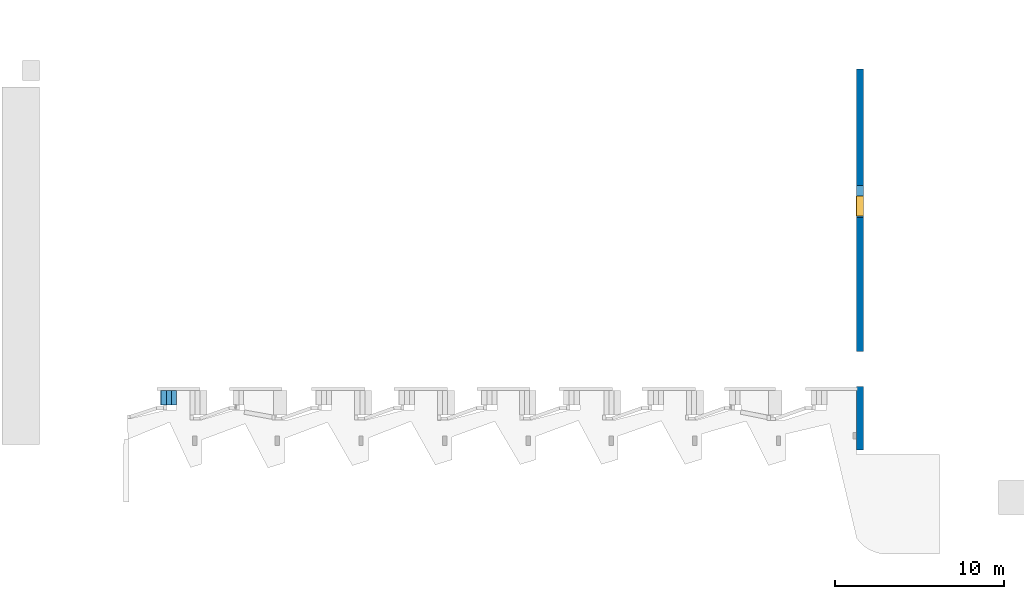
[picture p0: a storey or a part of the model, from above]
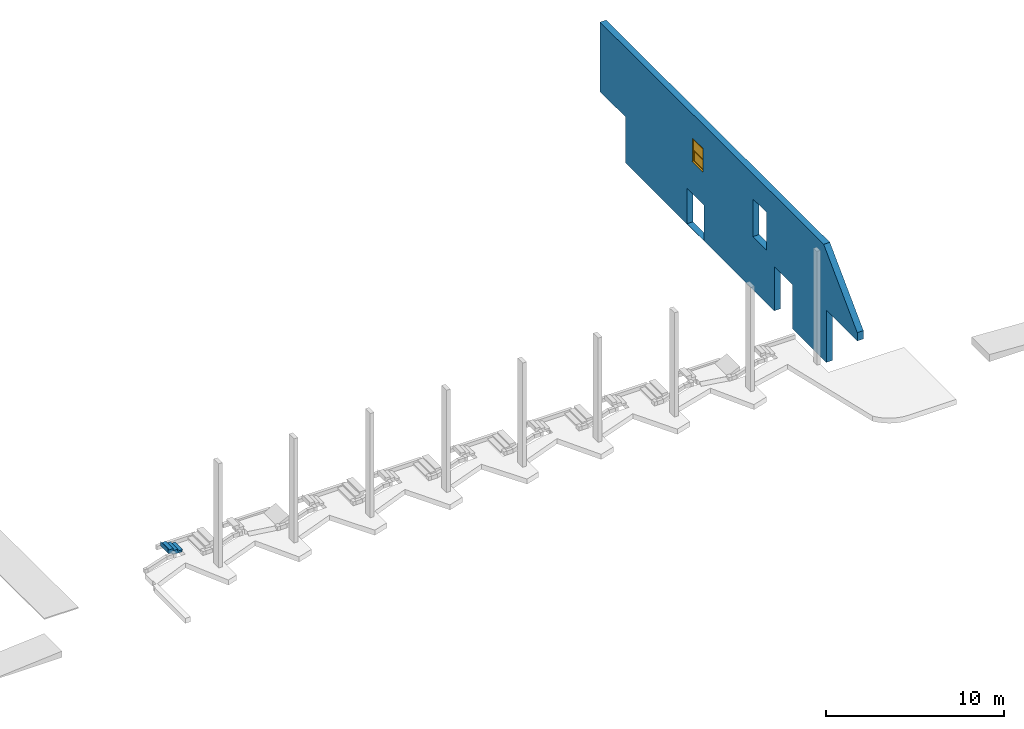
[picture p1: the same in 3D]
Properties of the parts of a building model (IFC4), part 1 of 3

# File
Description: ViewDefinition [ReferenceView_V1.2]
File name: 0001
Time: 2023-06-13T15:23:03-03:00
Written by: ODA SDAI 22.12
Made in: 23.0.11.19 - Exporter 23.0.11.19 - IU alternativa 23.0.11.19

# IfcProject, 0001
LongName: Nombre de proyecto; Phase: Estado de proyecto

# IfcSite, Superficie:305161
RefLatitude: 40, 25, 13, 9643; RefLongitude: -3, -42, -20, -772056; RefElevation: 0 m
Pset_SiteCommon - Reference: Superficie

# IfcBuilding
Pset_BuildingCommon - Reference: Información de proyecto; NumberOfStoreys: 5
Pset_BuildingElementProxyCommon - IsExternal: no; Reference: Información de proyecto
Pset_BuildingStoreyCommon - Reference: Información de proyecto; sets with these values: 2

# IfcBuildingStorey: Nivel:Nivel 1 (4)
Pset_BuildingStoreyCommon - Reference: Nivel 1
Name | LongName | Elevation (m)
Nivel -1 | Nivel -1 | -0.56
Nivel 0 | Nivel 0 | 0
Nivel 1 | Nivel 1 | 3.6
Nivel 2 | Nivel 2 | 7.25

# IfcSpace: Área:508666
In: Nivel 0
LongName: Área; PredefinedType: SPACE; Group: Área construida bruta
Pset_SpaceCommon - Reference: Área; IsExternal: no
Pset_SpaceHeaterTypeCommon - Reference: Área

# IfcSpace: Área:508668
In: Nivel 0
LongName: Área; PredefinedType: SPACE; Group: Área construida bruta
Pset_SpaceCommon - Reference: Área; IsExternal: no
Pset_SpaceHeaterTypeCommon - Reference: Área

# IfcSpace: Área:508670
In: Nivel 0
LongName: Área; PredefinedType: SPACE; Group: Área construida bruta
Pset_SpaceCommon - Reference: Área; IsExternal: no
Pset_SpaceHeaterTypeCommon - Reference: Área

# IfcSpace: Área:508672
In: Nivel 0
LongName: Área; PredefinedType: SPACE; Group: Área construida bruta
Pset_SpaceCommon - Reference: Área; IsExternal: no
Pset_SpaceHeaterTypeCommon - Reference: Área

# IfcSpace: Área:508674
In: Nivel 0
LongName: Área; PredefinedType: SPACE; Group: Área construida bruta
Pset_SpaceCommon - Reference: Área; IsExternal: no
Pset_SpaceHeaterTypeCommon - Reference: Área

# IfcSpace: Área:508676
In: Nivel 0
LongName: Área; PredefinedType: SPACE; Group: Área construida bruta
Pset_SpaceCommon - Reference: Área; IsExternal: no
Pset_SpaceHeaterTypeCommon - Reference: Área

# IfcSpace: Área:508678
In: Nivel 0
LongName: Área; PredefinedType: SPACE; Group: Área construida bruta
Pset_SpaceCommon - Reference: Área; IsExternal: no
Pset_SpaceHeaterTypeCommon - Reference: Área

# IfcSpace: Área:508680
In: Nivel 0
LongName: Área; PredefinedType: SPACE; Group: Área construida bruta
Pset_SpaceCommon - Reference: Área; IsExternal: no
Pset_SpaceHeaterTypeCommon - Reference: Área

# IfcSpace: Área:508682
In: Nivel 0
LongName: Área; PredefinedType: SPACE; Group: Área construida bruta
Pset_SpaceCommon - Reference: Área; IsExternal: no
Pset_SpaceHeaterTypeCommon - Reference: Área

# IfcSpace: Área:508726
In: Nivel 1
LongName: Área; PredefinedType: SPACE; Group: Área construida bruta
Pset_SpaceCommon - Reference: Área; IsExternal: no
Pset_SpaceHeaterTypeCommon - Reference: Área

# IfcSpace: Área:508728
In: Nivel 1
LongName: Área; PredefinedType: SPACE; Group: Área construida bruta
Pset_SpaceCommon - Reference: Área; IsExternal: no
Pset_SpaceHeaterTypeCommon - Reference: Área

# IfcSpace: Área:508730
In: Nivel 1
LongName: Área; PredefinedType: SPACE; Group: Área construida bruta
Pset_SpaceCommon - Reference: Área; IsExternal: no
Pset_SpaceHeaterTypeCommon - Reference: Área

# IfcSpace: Área:508752
In: Nivel -1
LongName: Área; PredefinedType: SPACE; Group: Área construida bruta
Pset_SpaceCommon - Reference: Área; IsExternal: no
Pset_SpaceHeaterTypeCommon - Reference: Área

# IfcSpace: Área:508754
In: Nivel -1
LongName: Área; PredefinedType: SPACE; Group: Área construida bruta
Pset_SpaceCommon - Reference: Área; IsExternal: no
Pset_SpaceHeaterTypeCommon - Reference: Área

# IfcSpace: Área:524344
In: Nivel 0
LongName: Área; PredefinedType: SPACE; Group: De alquiler
Pset_SpaceCommon - Reference: Área; IsExternal: no
Pset_SpaceHeaterTypeCommon - Reference: Área

# IfcSpace: Área:524351
In: Nivel 0
LongName: Área; PredefinedType: SPACE; Group: De alquiler
Pset_SpaceCommon - Reference: Área; IsExternal: no
Pset_SpaceHeaterTypeCommon - Reference: Área

# IfcSpace: Área:524354
In: Nivel 0
LongName: Área; PredefinedType: SPACE; Group: De alquiler
Pset_SpaceCommon - Reference: Área; IsExternal: no
Pset_SpaceHeaterTypeCommon - Reference: Área

# IfcSpace: Área:524357
In: Nivel 0
LongName: Área; PredefinedType: SPACE; Group: De alquiler
Pset_SpaceCommon - Reference: Área; IsExternal: no
Pset_SpaceHeaterTypeCommon - Reference: Área

# IfcSpace: Área:524360
In: Nivel 0
LongName: Área; PredefinedType: SPACE; Group: De alquiler
Pset_SpaceCommon - Reference: Área; IsExternal: no
Pset_SpaceHeaterTypeCommon - Reference: Área

# IfcSpace: Área:524363
In: Nivel 0
LongName: Área; PredefinedType: SPACE; Group: De alquiler
Pset_SpaceCommon - Reference: Área; IsExternal: no
Pset_SpaceHeaterTypeCommon - Reference: Área

# IfcSpace: Área:524366
In: Nivel 0
LongName: Área; PredefinedType: SPACE; Group: De alquiler
Pset_SpaceCommon - Reference: Área; IsExternal: no
Pset_SpaceHeaterTypeCommon - Reference: Área

# IfcSpace: Área:524373
In: Nivel 0
LongName: Área; PredefinedType: SPACE; Group: De alquiler
Pset_SpaceCommon - Reference: Área; IsExternal: no
Pset_SpaceHeaterTypeCommon - Reference: Área

# IfcSpace: Área:524435
In: Nivel 1
LongName: Área; PredefinedType: SPACE; Group: De alquiler
Pset_SpaceCommon - Reference: Área; IsExternal: no
Pset_SpaceHeaterTypeCommon - Reference: Área

# IfcSpace: Área:524438
In: Nivel 1
LongName: Área; PredefinedType: SPACE; Group: De alquiler
Pset_SpaceCommon - Reference: Área; IsExternal: no
Pset_SpaceHeaterTypeCommon - Reference: Área

# IfcSpace: Área:524441
In: Nivel 1
LongName: Área; PredefinedType: SPACE; Group: De alquiler
Pset_SpaceCommon - Reference: Área; IsExternal: no
Pset_SpaceHeaterTypeCommon - Reference: Área

# IfcSpace: Área:525715
In: Nivel 1
LongName: Área; PredefinedType: SPACE; Group: De alquiler
Pset_SpaceCommon - Reference: Área; IsExternal: no
Pset_SpaceHeaterTypeCommon - Reference: Área

# IfcSpace: Área:529661
In: Nivel 0
LongName: Área; PredefinedType: SPACE; Group: De alquiler
Pset_SpaceCommon - Reference: Área; IsExternal: no
Pset_SpaceHeaterTypeCommon - Reference: Área

# IfcBeam: Calibre delgado-Ángulos:L140 x 40 (64)
In: Nivel 1
Type - PredefinedType: BEAM; Classification: B10 Superstructure (Uniformat); Material: Metal - Calibre delgado
Type - Pset_BeamCommon - IsExternal: no; LoadBearing: yes
Pset_BeamCommon - Slope: 0 deg; Roll: 0 deg; Reference: L140 x 40
Pset_EnvironmentalImpactIndicators - Reference: L140 x 40; sets with these values: 2
Name (Calibre delgado-Ángulos:L140 x 40:...) | Span (m)
473266 | 5.8
473267 | 5.8
475000 | 5.8
475001 | 5.8
475056 | 5.8
475057 | 5.8
475089 | 5.8
475090 | 5.8
475131 | 5.8
475132 | 5.8
475164 | 5.8
475165 | 5.8
475208 | 5.8
475209 | 5.8
475241 | 5.8
475242 | 5.8
475287 | 5.8
475288 | 5.8
475320 | 5.8
475321 | 5.8
475362 | 5.8
475363 | 5.8
475395 | 5.8
475396 | 5.8
475441 | 5.8
475442 | 5.8
475474 | 5.8
475475 | 5.8
475514 | 5.8
475515 | 5.8
475547 | 5.8
475548 | 5.8
476010 | 3.745
476011 | 3.745
476043 | 3.245
476044 | 3.245
484346 | 3.745
484347 | 3.745
484379 | 3.245
484380 | 3.245
484423 | 3.745
484424 | 3.745
484456 | 3.245
484457 | 3.245
484496 | 3.745
484497 | 3.745
484529 | 3.245
484530 | 3.245
484571 | 3.745
484572 | 3.745
484604 | 3.245
484605 | 3.245
484646 | 3.745
484647 | 3.745
484679 | 3.245
484680 | 3.245
484721 | 3.745
484722 | 3.745
484754 | 3.245
484755 | 3.245
484798 | 3.745
484799 | 3.745
484831 | 3.245
484832 | 3.245

# IfcBeam: Familia4:Familia4, Familia4:Familia4:477913
In: Nivel 2
Type - PredefinedType: BEAM; Material: <Unnamed>
Type - Pset_BeamCommon - IsExternal: no; LoadBearing: yes
Pset_BeamCommon - Slope: 0 deg; Roll: 0 deg; Reference: Familia4; Span: 34.29 m
Pset_EnvironmentalImpactIndicators - Reference: Familia4; sets with these values: 2

# IfcBeam: Glulam-Pino del sur:127X279 (14)
In: Nivel 2
Type - PredefinedType: BEAM; Material: Madera - Madera de construcción
Type - Pset_BeamCommon - IsExternal: no; LoadBearing: yes
Pset_BeamCommon - Slope: 0 deg; Roll: 0 deg; Reference: 127X279; Span: 31.09 m
Pset_EnvironmentalImpactIndicators - Reference: 127X279; sets with these values: 2
Name (Glulam-Pino del sur:127X279:...)
500644
500646
500648
500650
500652
500654
500905
502043
502045
502047
502049
502051
502053
502055

# IfcBeam: Glulam-Pino del sur:76X140 (20)
Type - PredefinedType: BEAM; Material: Madera - Madera de construcción
Type - Pset_BeamCommon - IsExternal: no; LoadBearing: yes
Pset_BeamCommon - Roll: 0 deg; Reference: 76X140
Pset_EnvironmentalImpactIndicators - Reference: 76X140; sets with these values: 2
Name (Glulam-Pino del sur:76X140:...) | In | Span (m) | Slope (deg)
502747 | Nivel 1 | 2.012 | 29.5898
502748 | Nivel 1 | 2.018 | 29.8998
503400 | Nivel 1 | 2.012 | 29.5898
503401 | Nivel 1 | 2.018 | 29.8998
503442 | Nivel 1 | 2.012 | 29.5898
503443 | Nivel 1 | 2.018 | 29.8998
503513 | Nivel 1 | 2.012 | 29.5898
503514 | Nivel 1 | 2.018 | 29.8998
503559 | Nivel 1 | 2.012 | 29.5898
503560 | Nivel 1 | 2.018 | 29.8998
503611 | Nivel 1 | 2.012 | 29.5898
503612 | Nivel 1 | 2.018 | 29.8998
503664 | Nivel 1 | 2.012 | 29.5898
503665 | Nivel 1 | 2.018 | 29.8998
503721 | Nivel 1 | 2.012 | 29.5898
503722 | Nivel 1 | 2.018 | 29.8998
505065 | Nivel 0 | 34.1 | 0
505956 | Nivel 1 | 18 | 0
506497 | Nivel 1 | 4.8 | 0
506699 | Nivel 1 | 4.8 | 0

# IfcBeam: Hormigón-Viga rectangular:500 x 550mm 2 (3)
In: Nivel 1
Type - PredefinedType: BEAM; Material: <Unnamed>
Type - Pset_BeamCommon - IsExternal: no; LoadBearing: yes
Pset_BeamCommon - Slope: 0 deg; Roll: 0 deg; Reference: 500 x 550mm 2
Pset_EnvironmentalImpactIndicators - Reference: 500 x 550mm 2; sets with these values: 2
Name (Hormigón-Viga rectangular:500 x 550mm 2:...) | Span (m)
478072 | 43.197
478593 | 4.33
478989 | 4

# IfcBeam: MT-T estructural:MT65X14.05 (40)
In: Nivel 2
Type - PredefinedType: BEAM; Material: Metal - Acero - 345 MPa
Type - Pset_BeamCommon - IsExternal: no; LoadBearing: yes
Pset_BeamCommon - Roll: 0 deg; Reference: MT65X14.05
Pset_EnvironmentalImpactIndicators - Reference: MT65X14.05; sets with these values: 2
Name (MT-T estructural:MT65X14.05:...) | Slope (deg) | Span (m)
482733 | 0 | 7.735
482734 | 0 | 7.735
482735 | 28.4535 | 8.797
482736 | 28.4535 | 8.797
483913 | 1.20936 | 9.804
483914 | 24.2173 | 10.747
483987 | 0.636424 | 9.786
483988 | 23.772 | 10.693
484069 | 1.21062 | 9.793
484070 | 24.2396 | 10.738
484078 | 0.641706 | 9.706
484079 | 23.9472 | 10.619
499890 | 0 | 7.735
499891 | 0 | 7.735
499892 | 28.4535 | 8.797
499893 | 28.4535 | 8.797
499908 | 0 | 7.735
499909 | 0 | 7.735
499910 | 28.4535 | 8.797
499911 | 28.4535 | 8.797
588031 | 0 | 7.735
588032 | 0 | 7.735
588033 | 28.4535 | 8.797
588034 | 28.4535 | 8.797
588049 | 0 | 7.735
588050 | 0 | 7.735
588051 | 28.4535 | 8.797
588052 | 28.4535 | 8.797
588069 | 0 | 7.735
588070 | 0 | 7.735
588071 | 28.4535 | 8.797
588072 | 28.4535 | 8.797
588089 | 0 | 7.735
588090 | 0 | 7.735
588091 | 28.4535 | 8.797
588092 | 28.4535 | 8.797
588111 | 0 | 7.735
588112 | 0 | 7.735
588113 | 28.4535 | 8.797
588114 | 28.4535 | 8.797

# IfcBeam: UB-Perfil universal:203x133x25UB (2)
In: Nivel 0
Type - PredefinedType: BEAM; Material: Metal - Acero - 345 MPa
Type - Pset_BeamCommon - IsExternal: no; LoadBearing: yes
Pset_BeamCommon - Slope: 0 deg; Reference: 203x133x25UB; Span: 11.76 m; Roll: 0 deg
Pset_EnvironmentalImpactIndicators - Reference: 203x133x25UB; sets with these values: 2
Name (UB-Perfil universal:203x133x25UB:...)
254423
257939

# IfcBeam: UB-Perfil universal:305x165x40UB (9)
Type - PredefinedType: BEAM; Material: Metal - Acero - 345 MPa
Type - Pset_BeamCommon - IsExternal: no; LoadBearing: yes
Pset_BeamCommon - Roll: 0 deg; Reference: 305x165x40UB
Pset_EnvironmentalImpactIndicators - Reference: 305x165x40UB; sets with these values: 2
Name (UB-Perfil universal:305x165x40UB:...) | In | Slope (deg) | Span (m)
258424 | Nivel 0 | 0 | 11.71
484929 | Nivel 1 | 42.7094 | 4.422
485413 | Nivel 1 | 42.7094 | 4.422
485424 | Nivel 1 | 42.7094 | 4.422
485439 | Nivel 1 | 42.7094 | 4.422
485452 | Nivel 1 | 42.7094 | 4.422
485461 | Nivel 1 | 42.7094 | 4.422
485474 | Nivel 1 | 42.7094 | 4.422
485487 | Nivel 1 | 42.7094 | 4.422

# IfcColumn: Pilar rectangular hormigón:100 x 180 mm 2 (9)
In: Nivel 0
Type - PredefinedType: COLUMN; Material: <Unnamed>
Type - Pset_ColumnCommon - IsExternal: no; LoadBearing: yes
Pset_ColumnCommon - Reference: 100 x 180 mm 2
Pset_EnvironmentalImpactIndicators - Reference: 100 x 180 mm 2; sets with these values: 2
Name (Pilar rectangular hormigón:100 x 180 mm 2:...)
185699
185760
307513
307828
307911
307978
307991
310705 | Pset_ColumnCommon - Slope: 0 deg
313675

# IfcColumn: Pilar rectangular hormigón:100 x 200 mm 3, Pilar rectangular hormigón:100 x 200 mm 3:292656
In: Nivel 0
Type - PredefinedType: COLUMN; Material: <Unnamed>
Type - Pset_ColumnCommon - IsExternal: no; LoadBearing: yes
Pset_ColumnCommon - Reference: 100 x 200 mm 3
Pset_EnvironmentalImpactIndicators - Reference: 100 x 200 mm 3; sets with these values: 2

# IfcColumn: Pilar rectangular hormigón:110 x 110 mm 3 (10)
In: Nivel 1
Type - PredefinedType: COLUMN; Material: <Unnamed>
Type - Pset_ColumnCommon - IsExternal: no; LoadBearing: yes
Pset_ColumnCommon - Reference: 110 x 110 mm 3
Pset_EnvironmentalImpactIndicators - Reference: 110 x 110 mm 3; sets with these values: 2
Name (Pilar rectangular hormigón:110 x 110 mm 3:...)
356811
357788
362148
362694
366528
366587
405644
405647
405773
405776

# IfcColumn: Pilar rectangular hormigón:120 x 160 mm 4 (8)
In: Nivel 0
Type - PredefinedType: COLUMN; Material: <Unnamed>
Type - Pset_ColumnCommon - IsExternal: no; LoadBearing: yes
Pset_ColumnCommon - Reference: 120 x 160 mm 4
Pset_EnvironmentalImpactIndicators - Reference: 120 x 160 mm 4; sets with these values: 2
Name (Pilar rectangular hormigón:120 x 160 mm 4:...)
185893
185971
186019
186042
186062
186096
219436
219437

# IfcColumn: Pilar rectangular hormigón:120 x 180 mm 3 (6)
In: Nivel 0
Type - PredefinedType: COLUMN; Material: <Unnamed>
Type - Pset_ColumnCommon - IsExternal: no; LoadBearing: yes
Pset_ColumnCommon - Reference: 120 x 180 mm 3
Pset_EnvironmentalImpactIndicators - Reference: 120 x 180 mm 3; sets with these values: 2
Name (Pilar rectangular hormigón:120 x 180 mm 3:...)
185724
185850
267552
267672
267702
279104

# IfcColumn: Pilar rectangular hormigón:160 x 250 mm 4 (2)
In: Nivel 0
Type - PredefinedType: COLUMN; Material: <Unnamed>
Type - Pset_ColumnCommon - IsExternal: no; LoadBearing: yes
Pset_ColumnCommon - Reference: 160 x 250 mm 4
Pset_EnvironmentalImpactIndicators - Reference: 160 x 250 mm 4; sets with these values: 2
Name (Pilar rectangular hormigón:160 x 250 mm 4:...)
214045
214521

# IfcColumn: Pilar rectangular hormigón:180 x 180 mm 3 (5)
In: Nivel 0
Type - PredefinedType: COLUMN; Material: <Unnamed>
Type - Pset_ColumnCommon - IsExternal: no; LoadBearing: yes
Pset_ColumnCommon - Reference: 180 x 180 mm 3
Pset_EnvironmentalImpactIndicators - Reference: 180 x 180 mm 3; sets with these values: 2
Name (Pilar rectangular hormigón:180 x 180 mm 3:...)
186938
187138
226451
267727
327475

# IfcColumn: Pilar rectangular hormigón:200 x 370 mm 3 (2)
Type - PredefinedType: COLUMN; Material: <Unnamed>
Type - Pset_ColumnCommon - IsExternal: no; LoadBearing: yes
Pset_ColumnCommon - Reference: 200 x 370 mm 3
Pset_EnvironmentalImpactIndicators - Reference: 200 x 370 mm 3; sets with these values: 2
Name (Pilar rectangular hormigón:200 x 370 mm 3:...) | In
184023 | Nivel 0
184345 | Nivel -1

# IfcColumn: Pilar rectangular hormigón:250 x 500 mm 4, Pilar rectangular hormigón:250 x 500 mm 4:272511
In: Nivel 0
Type - PredefinedType: COLUMN; Material: <Unnamed>
Type - Pset_ColumnCommon - IsExternal: no; LoadBearing: yes
Pset_ColumnCommon - Reference: 250 x 500 mm 4
Pset_EnvironmentalImpactIndicators - Reference: 250 x 500 mm 4; sets with these values: 2

# IfcColumn: Pilar rectangular hormigón:250 x 560 mm 2 (16)
Type - PredefinedType: COLUMN; Material: <Unnamed>
Type - Pset_ColumnCommon - IsExternal: no; LoadBearing: yes
Pset_ColumnCommon - Reference: 250 x 560 mm 2
Pset_EnvironmentalImpactIndicators - Reference: 250 x 560 mm 2; sets with these values: 2
Name (Pilar rectangular hormigón:250 x 560 mm 2:...) | In
181776 | Nivel -1
181876 | Nivel -1
182387 | Nivel -1
182528 | Nivel -1
182604 | Nivel -1
182714 | Nivel -1
182718 | Nivel -1
182881 | Nivel -1
182939 | Nivel 0
183344 | Nivel 0
183365 | Nivel 0
183386 | Nivel 0
183398 | Nivel 0
183424 | Nivel 0
183438 | Nivel 0
183450 | Nivel 0

# IfcColumn: Pilar rectangular hormigón:280 x 280 mm 2 (4)
In: Nivel 0
Type - PredefinedType: COLUMN; Material: <Unnamed>
Type - Pset_ColumnCommon - IsExternal: no; LoadBearing: yes
Pset_ColumnCommon - Reference: 280 x 280 mm 2
Pset_EnvironmentalImpactIndicators - Reference: 280 x 280 mm 2; sets with these values: 2
Name (Pilar rectangular hormigón:280 x 280 mm 2:...)
185399
185660
185670
225717 | Pset_ColumnCommon - Slope: 0 deg

# IfcColumn: Pilar rectangular hormigón:300 x 300 mm (6)
In: Nivel 0
Type - PredefinedType: COLUMN; Material: <Unnamed>
Type - Pset_ColumnCommon - IsExternal: no; LoadBearing: yes
Pset_ColumnCommon - Reference: 300 x 300 mm
Pset_EnvironmentalImpactIndicators - Reference: 300 x 300 mm; sets with these values: 2
Name (Pilar rectangular hormigón:300 x 300 mm:...)
185258
185382
275395
275464
275476
275490

# IfcColumn: Pilar rectangular hormigón:310 x 560 mm 2 (10)
In: Nivel 0
Type - PredefinedType: COLUMN; Material: <Unnamed>
Type - Pset_ColumnCommon - IsExternal: no; LoadBearing: yes
Pset_ColumnCommon - Reference: 310 x 560 mm 2
Pset_EnvironmentalImpactIndicators - Reference: 310 x 560 mm 2; sets with these values: 2
Name (Pilar rectangular hormigón:310 x 560 mm 2:...)
428051
428371
428669
428751
428786
428787
428956
428984
429018
429059

# IfcColumn: Pilar rectangular hormigón:600 x 700 mm 5, Pilar rectangular hormigón:600 x 700 mm 5:427090
In: Nivel 0
Type - PredefinedType: COLUMN; Material: <Unnamed>
Type - Pset_ColumnCommon - IsExternal: no; LoadBearing: yes
Pset_ColumnCommon - Reference: 600 x 700 mm 5
Pset_EnvironmentalImpactIndicators - Reference: 600 x 700 mm 5; sets with these values: 2

# IfcColumn: Pilar rectangular hormigón:630 x 740 mm 4, Pilar rectangular hormigón:630 x 740 mm 4:314824
In: Nivel 0
Type - PredefinedType: COLUMN; Material: <Unnamed>
Type - Pset_ColumnCommon - IsExternal: no; LoadBearing: yes
Pset_ColumnCommon - Reference: 630 x 740 mm 4
Pset_EnvironmentalImpactIndicators - Reference: 630 x 740 mm 4; sets with these values: 2

# IfcCovering: Techo compuesto:Falso techo 2 de placa de yeso laminado (6)
Type - PredefinedType: CEILING
Type - Pset_CoveringCommon - IsExternal: no
Material: Lámina de enlucido perforada
Pset_CoveringCommon - Reference: Falso techo 2 de placa de yeso laminado; Finish: Lámina de enlucido perforada;
Pset_EnvironmentalImpactIndicators - Reference: Falso techo 2 de placa de yeso laminado
Name (Techo compuesto:Falso techo 2 de placa de yeso laminado:...) | In
222428 | Nivel 1
224767 | Nivel 0
253870 | Nivel 0
409967 | Nivel 1
509764 | Nivel 0
564613 | Nivel 1

# IfcCurtainWall: Muro básico:Por defecto - 10 cm (90)
Type - Pset_CurtainWallCommon - IsExternal: yes
Material: <Unnamed>
Pset_CurtainWallCommon - Reference: Por defecto - 10 cm
Pset_EnvironmentalImpactIndicators - Reference: Por defecto - 10 cm
Name (Muro básico:Por defecto - 10 cm:...) | In
250650 | Nivel 0
250606 | Nivel 0
250574 | Nivel 0
253623 | Nivel 0
252925 | Nivel 0
269627 | Nivel 0
269625 | Nivel 0
270698 | Nivel 0
272088 | Nivel 0
271545 | Nivel 0
271903 | Nivel 0
271904 | Nivel 0
273407 | Nivel 0
274762 | Nivel 0
275557 | Nivel 0
275646 | Nivel 0
275693 | Nivel 0
279073 | Nivel 0
276852 | Nivel 0
277248 | Nivel 0
277247 | Nivel 0
289521 | Nivel 0
289540 | Nivel 0
289566 | Nivel 0
289577 | Nivel 0
289587 | Nivel 0
289594 | Nivel 0
289596 | Nivel 0
519957 | Nivel 0
519993 | Nivel 0
510679 | Nivel 0
308412 | Nivel 0
432963 | Nivel 0
432965 | Nivel 0
515756 | Nivel 0
310866 | Nivel 0
326347 | Nivel 0
326358 | Nivel 0
326326 | Nivel 0
326357 | Nivel 0
329254 | Nivel 0
329256 | Nivel 0
329252 | Nivel 0
329257 | Nivel 0
357591 | Nivel 1
358342 | Nivel 1
361881 | Nivel 1
359012 | Nivel 1
362881 | Nivel 1
362736 | Nivel 1
362778 | Nivel 1
366689 | Nivel 1
366627 | Nivel 1
367036 | Nivel 1
366669 | Nivel 1
386155 | Nivel 0
386154 | Nivel 0
389050 | Nivel 0
389048 | Nivel 0
389031 | Nivel 0
389051 | Nivel 0
389053 | Nivel 0
389237 | Nivel 0
389172 | Nivel 0
389198 | Nivel 0
389215 | Nivel 0
405749 | Nivel 1
405687 | Nivel 1
632068 | Nivel 1
405729 | Nivel 1
405816 | Nivel 1
535234 | Nivel 1
405883 | Nivel 1
405858 | Nivel 1
512644 | Nivel 0
512694 | Nivel 0
512769 | Nivel 0
513380 | Nivel 0
513801 | Nivel 0
513947 | Nivel 0
514220 | Nivel 0
516324 | Nivel 0
518640 | Nivel 0
518642 | Nivel 0
516101 | Nivel 0
519531 | Nivel 0
519533 | Nivel 0
532224 | Nivel 0
532621 | Nivel 0
532585 | Nivel 0

# IfcCurtainWall: Muro básico:Por defecto - 12 cm 2 (15)
In: Nivel 0
Type - Pset_CurtainWallCommon - IsExternal: yes
Material: <Unnamed>
Pset_CurtainWallCommon - Reference: Por defecto - 12 cm 2
Pset_EnvironmentalImpactIndicators - Reference: Por defecto - 12 cm 2
Name (Muro básico:Por defecto - 12 cm 2:...)
222609
222542
211875
212557
212708
215758
215760
215864
215865
216034
216035
219531
219886
220863
220864

# IfcCurtainWall: Muro básico:Por defecto - 5 cm 2 (2)
In: Nivel 0
Type - Pset_CurtainWallCommon - IsExternal: yes
Material: <Unnamed>
Pset_CurtainWallCommon - Reference: Por defecto - 5 cm 2
Pset_EnvironmentalImpactIndicators - Reference: Por defecto - 5 cm 2
Name (Muro básico:Por defecto - 5 cm 2:...)
396029
433225

# IfcCurtainWall: Muro cortina:Muro cortina - simple (69)
Type - Pset_CurtainWallCommon - IsExternal: yes
Pset_CurtainWallCommon - Reference: Muro cortina - simple
Pset_EnvironmentalImpactIndicators - Reference: Muro cortina - simple
Name (Muro cortina:Muro cortina - simple:...) | In
206558 | Nivel 0
211066 | Nivel 0
212552 | Nivel 0
212704 | Nivel 0
214658 | Nivel 0
215856 | Nivel 0
216026 | Nivel 0
219526 | Nivel 0
219882 | Nivel 0
220350 | Nivel 0
233194 | Nivel 0
240171 | Nivel 0
249432 | Nivel 0
251173 | Nivel 0
252332 | Nivel 0
268531 | Nivel 0
270169 | Nivel 0
271016 | Nivel 0
271862 | Nivel 0
273371 | Nivel 0
274169 | Nivel 0
275532 | Nivel 0
275621 | Nivel 0
275668 | Nivel 0
275809 | Nivel 0
277203 | Nivel 0
278219 | Nivel 0
280223 | Nivel 0
280855 | Nivel 0
288782 | Nivel 0
289975 | Nivel 0
293080 | Nivel 0
308048 | Nivel 0
308113 | Nivel 0
310834 | Nivel 0
325444 | Nivel 0
328564 | Nivel 0
352709 | Nivel 1
355699 | Nivel 1
357075 | Nivel 1
357720 | Nivel 1
358403 | Nivel 1
362692 | Nivel 1
362737 | Nivel 1
363124 | Nivel 1
366585 | Nivel 1
366628 | Nivel 1
385507 | Nivel 0
387263 | Nivel 0
387446 | Nivel 0
387636 | Nivel 0
387770 | Nivel 0
390942 | Nivel 0
404725 | Nivel 1
405645 | Nivel 1
405688 | Nivel 1
405750 | Nivel 1
405774 | Nivel 1
405817 | Nivel 1
405885 | Nivel 1
408320 | Nivel 1
408454 | Nivel 1
409654 | Nivel 1
511763 | Nivel 0
516071 | Nivel 0
530913 | Nivel 0
531747 | Nivel 0
589380 | Nivel 1
589845 | Nivel 1

# IfcDoor: Puerta atamborada de 2 hojas:1200 x 2100 mm 2 (4)
In: Nivel 1
Type - PredefinedType: DOOR; Material: Puerta - Panel, Puerta - Marco
Type - Pset_DoorCommon - IsExternal: no; ThermalTransmittance: 3.7021 kg/K/s3
OverallHeight: 2.1 m; OverallWidth: 1.2 m
Pset_DoorCommon - Reference: 1200 x 2100 mm 2
Pset_EnvironmentalImpactIndicators - Reference: 1200 x 2100 mm 2
Name (Puerta atamborada de 2 hojas:1200 x 2100 mm 2:...)
419465
419806
419989
632473

# IfcDoor: Puerta corredera simple con guía deslizante:1330 x 2100mm 2, Puerta corredera simple con guía deslizante:1330 x 2100mm 2:195537
In: Nivel 0
Type - PredefinedType: DOOR; Material: <Unnamed>, Madera - Castaño (3)
Type - Pset_DoorCommon - IsExternal: no; ThermalTransmittance: 3.7021 kg/K/s3
OverallHeight: 2.1 m; OverallWidth: 1.33 m; Material: <Unnamed>, Madera - Castaño
Pset_DoorCommon - Reference: 1330 x 2100mm 2
Pset_EnvironmentalImpactIndicators - Reference: 1330 x 2100mm 2

# IfcDoor: Puerta de 1 hoja:116 x 210 cm 2, Puerta de 1 hoja:116 x 210 cm 2:424842
In: Nivel 1
Type - PredefinedType: DOOR; Material: Madera - Castaño
Type - Pset_DoorCommon - IsExternal: no
OverallHeight: 2.1 m; OverallWidth: 1.16 m
Pset_DoorCommon - IsExternal: yes; Reference: 116 x 210 cm 2
Pset_EnvironmentalImpactIndicators - Reference: 116 x 210 cm 2

# IfcDoor: Puerta de 1 hoja:120 x 210 cm 3 (2)
In: Nivel 1
Type - PredefinedType: DOOR; Material: Madera - Castaño
Type - Pset_DoorCommon - IsExternal: no
OverallHeight: 2.1 m; OverallWidth: 1.2 m
Pset_DoorCommon - Reference: 120 x 210 cm 3
Pset_EnvironmentalImpactIndicators - Reference: 120 x 210 cm 3
Name (Puerta de 1 hoja:120 x 210 cm 3:...)
485995 | Pset_DoorCommon - IsExternal: yes
632139

# IfcDoor: Puerta de 1 hoja:70 x 210 cm (2)
In: Nivel 1
Type - PredefinedType: DOOR; Material: Madera - Castaño
Type - Pset_DoorCommon - IsExternal: no; ThermalTransmittance: 3.7021 kg/K/s3
OverallHeight: 2.1 m; OverallWidth: 0.7 m
Pset_DoorCommon - Reference: 70 x 210 cm
Pset_EnvironmentalImpactIndicators - Reference: 70 x 210 cm
Name (Puerta de 1 hoja:70 x 210 cm:...)
487238
487425

# IfcDoor: Puerta de 1 hoja:80 x 210 cm (7)
Type - PredefinedType: DOOR; Material: Madera - Castaño
Type - Pset_DoorCommon - IsExternal: no; ThermalTransmittance: 3.7021 kg/K/s3
OverallHeight: 2.1 m; OverallWidth: 0.8 m
Pset_DoorCommon - Reference: 80 x 210 cm
Pset_EnvironmentalImpactIndicators - Reference: 80 x 210 cm
Name (Puerta de 1 hoja:80 x 210 cm:...) | In
186584 | Nivel 0
230418 | Nivel 0
230466 | Nivel 0
284672 | Nivel 0
485675 | Nivel 1
549885 | Nivel 1
628626 | Nivel 0

# IfcDoor: Puerta de 1 hoja:83 x 210 cm 3 (3)
In: Nivel 1
Type - PredefinedType: DOOR; Material: Madera - Castaño
Type - Pset_DoorCommon - IsExternal: no
OverallHeight: 2.1 m; OverallWidth: 0.83 m
Pset_DoorCommon - Reference: 83 x 210 cm 3
Pset_EnvironmentalImpactIndicators - Reference: 83 x 210 cm 3
Name (Puerta de 1 hoja:83 x 210 cm 3:...)
485802 | Pset_DoorCommon - IsExternal: yes
487307
487385

# IfcDoor: Puerta de 1 hoja:85 x 210 cm 2 (8)
Type - PredefinedType: DOOR; Material: Madera - Castaño
Type - Pset_DoorCommon - IsExternal: no
OverallHeight: 2.1 m; OverallWidth: 0.85 m
Pset_DoorCommon - Reference: 85 x 210 cm 2
Pset_EnvironmentalImpactIndicators - Reference: 85 x 210 cm 2
Name (Puerta de 1 hoja:85 x 210 cm 2:...) | In
425604 | Nivel 1 | Pset_DoorCommon - IsExternal: yes
487824 | Nivel 1
550014 | Nivel 1
552133 | Nivel 1
626463 | Nivel 0
626503 | Nivel 0
628042 | Nivel 1
630606 | Nivel 0

# IfcDoor: Puerta de 1 hoja:88 x 210 cm 3, Puerta de 1 hoja:88 x 210 cm 3:536665
In: Nivel 1
Type - PredefinedType: DOOR; Material: Madera - Castaño
Type - Pset_DoorCommon - IsExternal: no
OverallHeight: 2.1 m; OverallWidth: 0.88 m
Pset_DoorCommon - IsExternal: yes; Reference: 88 x 210 cm 3
Pset_EnvironmentalImpactIndicators - Reference: 88 x 210 cm 3

# IfcDoor: Puerta de 1 hoja:90 x 210 cm (5)
Type - PredefinedType: DOOR; Material: Madera - Castaño
Type - Pset_DoorCommon - IsExternal: no; ThermalTransmittance: 3.7021 kg/K/s3
OverallHeight: 2.1 m; OverallWidth: 0.9 m
Pset_DoorCommon - Reference: 90 x 210 cm
Pset_EnvironmentalImpactIndicators - Reference: 90 x 210 cm
Name (Puerta de 1 hoja:90 x 210 cm:...) | In
223377 | Nivel 0
226842 | Nivel 0
230336 | Nivel 0
281908 | Nivel 0
632253 | Nivel 1

# IfcDoor: Puerta de cristal abatible en muro cortina:Puerta de chapa abatible en muro cortina 2 (4)
In: Nivel 0
Type - PredefinedType: DOOR; Material: Metal - Aluminio, Acero
Type - Pset_DoorCommon - IsExternal: yes; ThermalTransmittance: 5.5617 kg/K/s3
Pset_DoorCommon - Reference: Puerta de chapa abatible en muro cortina 2
Pset_EnvironmentalImpactIndicators - Reference: Puerta de chapa abatible en muro cortina 2
Name (Puerta de cristal abatible en muro cortina:Puerta de chapa abatible en muro cortina 2:...) | OverallHeight (m) | OverallWidth (m)
214659 | 2.35 | 0.875
215857 | 2.35 | 0.895
216027 | 2.3 | 0.91
220351 | 2.35 | 1.4258

# IfcDoor: Puerta de cristal abatible en muro cortina:Puerta de cristal abatible en muro cortina (23)
Type - PredefinedType: DOOR; Material: Metal - Aluminio, Vidrio
Type - Pset_DoorCommon - IsExternal: yes; ThermalTransmittance: 5.5617 kg/K/s3
Pset_DoorCommon - Reference: Puerta de cristal abatible en muro cortina
Pset_EnvironmentalImpactIndicators - Reference: Puerta de cristal abatible en muro cortina
Name (Puerta de cristal abatible en muro cortina:Puerta de cristal abatible en muro cortina:...) | In | OverallHeight (m) | OverallWidth (m)
398405 | Nivel 0 | 2.305 | 0.775
271036 | Nivel 0 | 2.255 | 0.85
271873 | Nivel 0 | 2.255 | 0.85
273378 | Nivel 0 | 2.255 | 0.825
400330 | Nivel 0 | 2.255 | 0.8
276440 | Nivel 0 | 2.285 | 0.85
277215 | Nivel 0 | 2.285 | 0.85
278709 | Nivel 0 | 2.285 | 0.85
395787 | Nivel 0 | 2.285 | 0.9
280662 | Nivel 0 | 2.285 | 1.075
328785 | Nivel 0 | 2.285 | 0.875
358215 | Nivel 1 | 2.235 | 0.85
362749 | Nivel 1 | 2.255 | 0.91
363386 | Nivel 1 | 2.25 | 0.825
385508 | Nivel 0 | 2.25 | 1.125
391729 | Nivel 0 | 2.25 | 0.9
404732 | Nivel 1 | 2.25 | 0.825
405757 | Nivel 1 | 2.25 | 0.825
405890 | Nivel 1 | 2.25 | 0.825
409252 | Nivel 1 | 2.25 | 0.95
409130 | Nivel 1 | 2.25 | 0.95
518969 | Nivel 0 | 2.34 | 0.745
531748 | Nivel 0 | 2.47903 | 0.825

# IfcElementAssembly: Cercha 3:Cercha 3 (8)
In: Nivel 2
PredefinedType: TRUSS
Pset_ElementAssemblyCommon - Reference: Cercha 3; sets with these values: 2
Name (Cercha 3:Cercha 3:...)
482732
499889
499907
588030
588048
588068
588088
588110

# IfcElementAssembly: Cercha esquina:Cercha esquina (4)
In: Nivel 2
PredefinedType: TRUSS
Pset_ElementAssemblyCommon - Reference: Cercha esquina; sets with these values: 2
Name (Cercha esquina:Cercha esquina:...)
483911
483986
484068
484077

# IfcElementAssembly: Cercha superior:Cercha superior (8)
In: Nivel 1
PredefinedType: TRUSS
Pset_ElementAssemblyCommon - Reference: Cercha superior; sets with these values: 2
Name (Cercha superior:Cercha superior:...)
502745
503399
503441
503512
503558
503610
503663
503720

# IfcElementAssembly: Sistema de vigas estructurales:Sistema de vigas estructurales (2)
In: Nivel 2
PredefinedType: BEAM_GRID
Pset_ElementAssemblyCommon - Reference: Sistema de vigas estructurales; sets with these values: 2
Name (Sistema de vigas estructurales:Sistema de vigas estructurales:...)
500557
501715

# IfcElementAssembly: Viga de celosia 13:Viga de celosia 13 (32)
In: Nivel 1
PredefinedType: TRUSS
Pset_ElementAssemblyCommon - Reference: Viga de celosia 13; sets with these values: 2
Name (Viga de celosia 13:Viga de celosia 13:...)
473264
474999
475055
475088
475130
475163
475207
475240
475286
475319
475361
475394
475440
475473
475513
475546
476009
476042
484345
484378
484422
484455
484495
484528
484570
484603
484645
484678
484720
484753
484797
484830

# IfcFlowTerminal: Asiento de WC con cisterna - Basado en muro (1):700 x 370 mm (16)
In: Nivel 0
Type - Material: <Unnamed>
Pset_EnvironmentalImpactIndicators - Reference: 700 x 370 mm
Name (Asiento de WC con cisterna - Basado en muro (1):700 x 370 mm:...)
623194
623218
623241
625145
625169
625190
626348
626388
626406
626971
627004
627030
627457
627473
627494
627529

# IfcFlowTerminal: Grifo:Grifo (21)
Type - Material: <Unnamed>
Pset_EnvironmentalImpactIndicators - Reference: Grifo
Name (Grifo:Grifo:...) | In
562905 | Nivel 1
562997 | Nivel 1
563027 | Nivel 1
565132 | Nivel 1
565296 | Nivel 1
565433 | Nivel 1
565471 | Nivel 1
621730 | Nivel 0
621760 | Nivel 0
621781 | Nivel 0
621794 | Nivel 0
621813 | Nivel 0
625254 | Nivel 0
625290 | Nivel 0
626241 | Nivel 0
626298 | Nivel 0
626318 | Nivel 0
626560 | Nivel 0
626588 | Nivel 0
626661 | Nivel 0
626794 | Nivel 0

# IfcFlowTerminal: Lavamanos suspendido-3D:450 x 390mm (21)
Type - Material: <Unnamed>
Pset_EnvironmentalImpactIndicators - Reference: 450 x 390mm
Name (Lavamanos suspendido-3D:450 x 390mm:...) | In
562903 | Nivel 1
562996 | Nivel 1
563026 | Nivel 1
565130 | Nivel 1
565294 | Nivel 1
565431 | Nivel 1
565469 | Nivel 1
621728 | Nivel 0
621758 | Nivel 0
621779 | Nivel 0
621792 | Nivel 0
621811 | Nivel 0
625252 | Nivel 0
625288 | Nivel 0
626239 | Nivel 0
626296 | Nivel 0
626316 | Nivel 0
626558 | Nivel 0
626586 | Nivel 0
626660 | Nivel 0
626793 | Nivel 0

# IfcFlowTerminal: Urinario:Urinario (7)
In: Nivel 0
Type - Material: Metal - Cromo pulido, Porcelana
Pset_EnvironmentalImpactIndicators - Reference: Urinario
Name (Urinario:Urinario:...)
624132
624201
624386
624604
624703
624738
625027

# IfcFurniture: Aberturas1:Aberturas, Aberturas1:Aberturas:490165
In: Nivel 1
Type - Material: Madera - Listel
Pset_EnvironmentalImpactIndicators - Reference: Aberturas; sets with these values: 2

# IfcFurniture: Aberturas2:Aberturas, Aberturas2:Aberturas:491270
In: Nivel 1
Type - Material: Madera - Listel
Pset_EnvironmentalImpactIndicators - Reference: Aberturas; sets with these values: 2

# IfcFurniture: Aberturas3:Aberturas, Aberturas3:Aberturas:491869
In: Nivel 1
Type - Material: Madera - Listel
Pset_EnvironmentalImpactIndicators - Reference: Aberturas; sets with these values: 2

# IfcFurniture: Aberturas4:Aberturas, Aberturas4:Aberturas:498450
In: Nivel 1
Type - Material: Madera - Listel
Pset_EnvironmentalImpactIndicators - Reference: Aberturas; sets with these values: 2

# IfcFurniture: Aberturas5:Aberturas, Aberturas5:Aberturas:492102
In: Nivel 1
Type - Material: Madera - Listel
Pset_EnvironmentalImpactIndicators - Reference: Aberturas; sets with these values: 2

# IfcFurniture: Aberturas6:Aberturas, Aberturas6:Aberturas:492195
In: Nivel 1
Type - Material: Madera - Listel
Pset_EnvironmentalImpactIndicators - Reference: Aberturas; sets with these values: 2

# IfcFurniture: Aberturas7:Aberturas, Aberturas7:Aberturas:492298
In: Nivel 1
Type - Material: Madera - Listel
Pset_EnvironmentalImpactIndicators - Reference: Aberturas; sets with these values: 2

# IfcFurniture: Aberturas8:Aberturas, Aberturas8:Aberturas:498536
In: Nivel 1
Type - Material: Madera - Listel
Pset_EnvironmentalImpactIndicators - Reference: Aberturas; sets with these values: 2

# IfcFurniture: Aberturas9:Aberturas, Aberturas9:Aberturas:635416
In: Nivel 1
Type - Material: Madera - Listel
Pset_EnvironmentalImpactIndicators - Reference: Aberturas; sets with these values: 2

# IfcFurniture: Aberturas:Aberturas, Aberturas:Aberturas:489963
In: Nivel 1
Type - Material: Madera - Listel
Pset_EnvironmentalImpactIndicators - Reference: Aberturas; sets with these values: 2

# IfcFurniture: Baranda n1:Baranda n1, Baranda n1:Baranda n1:434863
In: Nivel 1
Type - Material: Madera - Listel
Pset_EnvironmentalImpactIndicators - Reference: Baranda n1; sets with these values: 2

# IfcFurniture: Mobiliario 10:Mobiliario 4, Mobiliario 10:Mobiliario 4:329585
In: Nivel 0
Type - Material: Madera - Listel
Pset_EnvironmentalImpactIndicators - Reference: Mobiliario 4; sets with these values: 2

# IfcFurniture: Mobiliario 11:Mobiliario 4, Mobiliario 11:Mobiliario 4:330382
In: Nivel 0
Type - Material: Madera - Listel
Pset_EnvironmentalImpactIndicators - Reference: Mobiliario 4; sets with these values: 2

# IfcFurniture: Mobiliario 12:Mobiliario 4, Mobiliario 12:Mobiliario 4:330767
In: Nivel 0
Type - Material: Madera - Listel
Pset_EnvironmentalImpactIndicators - Reference: Mobiliario 4; sets with these values: 2

# IfcFurniture: Mobiliario 13:Mobiliario 4, Mobiliario 13:Mobiliario 4:330915
In: Nivel 0
Type - Material: Madera - Listel
Pset_EnvironmentalImpactIndicators - Reference: Mobiliario 4; sets with these values: 2

# IfcFurniture: Mobiliario 14:Mobiliario 4, Mobiliario 14:Mobiliario 4:331273
In: Nivel 0
Type - Material: Madera - Listel
Pset_EnvironmentalImpactIndicators - Reference: Mobiliario 4; sets with these values: 2

# IfcFurniture: Mobiliario 15:Mobiliario 15, Mobiliario 15:Mobiliario 15:365632
In: Nivel 1
Type - Material: Madera - Listel
Pset_EnvironmentalImpactIndicators - Reference: Mobiliario 15; sets with these values: 2

# IfcFurniture: Mobiliario 16:Mobiliario 4, Mobiliario 16:Mobiliario 4:386492
In: Nivel 0
Type - Material: Madera - Listel
Pset_EnvironmentalImpactIndicators - Reference: Mobiliario 4; sets with these values: 2

# IfcFurniture: Mobiliario 17:Mobiliario 4, Mobiliario 17:Mobiliario 4:396938
In: Nivel 0
Type - Material: Madera - Listel
Pset_EnvironmentalImpactIndicators - Reference: Mobiliario 4; sets with these values: 2

# IfcFurniture: Mobiliario 18:Mobiliario 15, Mobiliario 18:Mobiliario 15:406033
In: Nivel 1
Type - Material: Madera - Listel
Pset_EnvironmentalImpactIndicators - Reference: Mobiliario 15; sets with these values: 2

# IfcFurniture: Mobiliario 3:Mobiliario 4, Mobiliario 3:Mobiliario 4:323959
In: Nivel 0
Type - Material: Madera - Listel
Pset_EnvironmentalImpactIndicators - Reference: Mobiliario 4; sets with these values: 2

# IfcFurniture: Mobiliario 4:Mobiliario 4, Mobiliario 4:Mobiliario 4:322888
In: Nivel 0
Type - Material: Madera - Listel
Pset_EnvironmentalImpactIndicators - Reference: Mobiliario 4; sets with these values: 2

# IfcFurniture: Mobiliario 5:Mobiliario 4, Mobiliario 5:Mobiliario 4:323998
In: Nivel 0
Type - Material: Madera - Listel
Pset_EnvironmentalImpactIndicators - Reference: Mobiliario 4; sets with these values: 2

# IfcFurniture: Mobiliario 6:Mobiliario 4, Mobiliario 6:Mobiliario 4:326470
In: Nivel 0
Type - Material: Madera - Listel
Pset_EnvironmentalImpactIndicators - Reference: Mobiliario 4; sets with these values: 2

# IfcFurniture: Mobiliario 7:Mobiliario 4, Mobiliario 7:Mobiliario 4:327865
In: Nivel 0
Type - Material: Madera - Listel
Pset_EnvironmentalImpactIndicators - Reference: Mobiliario 4; sets with these values: 2

# IfcFurniture: Mobiliario 8:Mobiliario 4, Mobiliario 8:Mobiliario 4:327900
In: Nivel 0
Type - Material: Madera - Listel
Pset_EnvironmentalImpactIndicators - Reference: Mobiliario 4; sets with these values: 2

# IfcFurniture: Mobiliario 9:Mobiliario 4, Mobiliario 9:Mobiliario 4:329458
In: Nivel 0
Type - Material: Madera - Listel
Pset_EnvironmentalImpactIndicators - Reference: Mobiliario 4; sets with these values: 2

# IfcFurniture: Mostrador:Mostrador, Mostrador:Mostrador:391982
In: Nivel 0
Type - Material: Madera - Listel
Pset_EnvironmentalImpactIndicators - Reference: Mostrador; sets with these values: 2

# IfcFurniture: Pasamanos escalera1:Pasamanos escalera, Pasamanos escalera1:Pasamanos escalera:465624
In: Nivel 0
Type - Material: Madera - Listel
Pset_EnvironmentalImpactIndicators - Reference: Pasamanos escalera; sets with these values: 2

# IfcFurniture: Pasamanos escalera2:Pasamanos escalera, Pasamanos escalera2:Pasamanos escalera:466609
In: Nivel 0
Type - Material: Madera - Listel
Pset_EnvironmentalImpactIndicators - Reference: Pasamanos escalera; sets with these values: 2

# IfcFurniture: Pasamanos escalera6:Pasamanos escalera, Pasamanos escalera6:Pasamanos escalera:467864
In: Nivel 0
Type - Material: Madera - Listel
Pset_EnvironmentalImpactIndicators - Reference: Pasamanos escalera; sets with these values: 2

# IfcFurniture: Pasamanos escalera:Pasamanos escalera, Pasamanos escalera:Pasamanos escalera:464051
In: Nivel 0
Type - Material: Madera - Listel
Pset_EnvironmentalImpactIndicators - Reference: Pasamanos escalera; sets with these values: 2

# IfcFurniture: baranda andenes10:baranda andenes, baranda andenes10:baranda andenes:451687
In: Nivel 0
Type - Material: Madera - Listel
Pset_EnvironmentalImpactIndicators - Reference: baranda andenes; sets with these values: 2

# IfcFurniture: baranda andenes11:baranda andenes, baranda andenes11:baranda andenes:452551
In: Nivel 0
Type - Material: Madera - Listel
Pset_EnvironmentalImpactIndicators - Reference: baranda andenes; sets with these values: 2

# IfcFurniture: baranda andenes12:baranda andenes, baranda andenes12:baranda andenes:452738
In: Nivel 0
Type - Material: Madera - Listel
Pset_EnvironmentalImpactIndicators - Reference: baranda andenes; sets with these values: 2

# IfcFurniture: baranda andenes13:baranda andenes, baranda andenes13:baranda andenes:453983
In: Nivel 0
Type - Material: Madera - Listel
Pset_EnvironmentalImpactIndicators - Reference: baranda andenes; sets with these values: 2

# IfcFurniture: baranda andenes14:baranda andenes, baranda andenes14:baranda andenes:454493
In: Nivel 0
Type - Material: Madera - Listel
Pset_EnvironmentalImpactIndicators - Reference: baranda andenes; sets with these values: 2

# IfcFurniture: baranda andenes15:baranda andenes, baranda andenes15:baranda andenes:455679
In: Nivel 0
Type - Material: Madera - Listel
Pset_EnvironmentalImpactIndicators - Reference: baranda andenes; sets with these values: 2

# IfcFurniture: baranda andenes16:baranda andenes, baranda andenes16:baranda andenes:456913
In: Nivel 0
Type - Material: Madera - Listel
Pset_EnvironmentalImpactIndicators - Reference: baranda andenes; sets with these values: 2

# IfcFurniture: baranda andenes17:baranda andenes, baranda andenes17:baranda andenes:457929
In: Nivel 0
Type - Material: Madera - Listel
Pset_EnvironmentalImpactIndicators - Reference: baranda andenes; sets with these values: 2

# IfcFurniture: baranda andenes1:baranda andenes, baranda andenes1:baranda andenes:445004
In: Nivel 0
Type - Material: Madera - Listel
Pset_EnvironmentalImpactIndicators - Reference: baranda andenes; sets with these values: 2

# IfcFurniture: baranda andenes2:baranda andenes, baranda andenes2:baranda andenes:445253
In: Nivel 0
Type - Material: Madera - Listel
Pset_EnvironmentalImpactIndicators - Reference: baranda andenes; sets with these values: 2

# IfcFurniture: baranda andenes3:baranda andenes, baranda andenes3:baranda andenes:445381
In: Nivel 0
Type - Material: Madera - Listel
Pset_EnvironmentalImpactIndicators - Reference: baranda andenes; sets with these values: 2

# IfcFurniture: baranda andenes4:baranda andenes, baranda andenes4:baranda andenes:445509
In: Nivel 0
Type - Material: Madera - Listel
Pset_EnvironmentalImpactIndicators - Reference: baranda andenes; sets with these values: 2

# IfcFurniture: baranda andenes5:baranda andenes, baranda andenes5:baranda andenes:445641
In: Nivel 0
Type - Material: Madera - Listel
Pset_EnvironmentalImpactIndicators - Reference: baranda andenes; sets with these values: 2

# IfcFurniture: baranda andenes6:baranda andenes, baranda andenes6:baranda andenes:445978
In: Nivel 0
Type - Material: Madera - Listel
Pset_EnvironmentalImpactIndicators - Reference: baranda andenes; sets with these values: 2

# IfcFurniture: baranda andenes7:baranda andenes, baranda andenes7:baranda andenes:446546
In: Nivel 0
Type - Material: Madera - Listel
Pset_EnvironmentalImpactIndicators - Reference: baranda andenes; sets with these values: 2

# IfcFurniture: baranda andenes8:baranda andenes, baranda andenes8:baranda andenes:447317
In: Nivel 0
Type - Material: Madera - Listel
Pset_EnvironmentalImpactIndicators - Reference: baranda andenes; sets with these values: 2

# IfcFurniture: baranda andenes9:baranda andenes, baranda andenes9:baranda andenes:447842
In: Nivel 0
Type - Material: Madera - Listel
Pset_EnvironmentalImpactIndicators - Reference: baranda andenes; sets with these values: 2

# IfcFurniture: baranda andenes:baranda andenes, baranda andenes:baranda andenes:442400
In: Nivel 0
Type - Material: Madera - Listel
Pset_EnvironmentalImpactIndicators - Reference: baranda andenes; sets with these values: 2

# IfcFurniture: baranda hueco1:baranda hueco, baranda hueco1:baranda hueco:439424
In: Nivel 1
Type - Material: Madera - Listel
Pset_EnvironmentalImpactIndicators - Reference: baranda hueco; sets with these values: 2

# IfcFurniture: baranda hueco2:baranda hueco, baranda hueco2:baranda hueco:439885
In: Nivel 1
Type - Material: Madera - Listel
Pset_EnvironmentalImpactIndicators - Reference: baranda hueco; sets with these values: 2

# IfcFurniture: baranda hueco:baranda hueco, baranda hueco:baranda hueco:439282
In: Nivel 1
Type - Material: Madera - Listel
Pset_EnvironmentalImpactIndicators - Reference: baranda hueco; sets with these values: 2

# IfcFurniture: fachada:fachada, fachada:fachada:494475
In: Nivel 0
Type - Material: Madera - Listel
Pset_EnvironmentalImpactIndicators - Reference: fachada; sets with these values: 2

# IfcFurniture: tramo 2:tramo 1, tramo 2:tramo 1:219288
In: Nivel 0
Type - Material: Madera - Listel
Pset_EnvironmentalImpactIndicators - Reference: tramo 1; sets with these values: 2

# IfcMember: Glulam-Pino del sur:76X140 (24)
In: Nivel 1
Type - PredefinedType: BRACE; Material: Madera - Madera de construcción
Type - Pset_MemberCommon - IsExternal: no; LoadBearing: yes
Pset_EnvironmentalImpactIndicators - Reference: 76X140
Pset_MemberCommon - Slope: 0 deg; Roll: 0 deg; Reference: 76X140
Name (Glulam-Pino del sur:76X140:...) | Span (m)
502749 | 1
502750 | 1
502751 | 1
503402 | 1
503403 | 1
503404 | 1
503444 | 1
503445 | 1
503446 | 1
503515 | 1
503516 | 1
503517 | 1
503561 | 1
503562 | 1
503563 | 1
503613 | 1
503614 | 1
503615 | 1
503666 | 1
503667 | 1
503668 | 1
503723 | 1
503724 | 1.022
503725 | 1

# IfcMember: HSS-Sección estructural hueca:HSS41.3X41.3X4.8 (60)
In: Nivel 2
Type - PredefinedType: BRACE; Material: Metal - Acero - 345 MPa
Type - Pset_MemberCommon - IsExternal: no; LoadBearing: yes
Pset_EnvironmentalImpactIndicators - Reference: HSS41.3X41.3X4.8
Pset_MemberCommon - Roll: 0 deg; Reference: HSS41.3X41.3X4.8
Name (HSS-Sección estructural hueca:HSS41.3X41.3X4.8:...) | Slope (deg) | Span (m)
482737 | 0 | 4.192
482738 | 67.5111 | 2.268
482739 | 67.5111 | 2.268
482740 | 54.4061 | 5.154
482741 | 54.4061 | 5.154
483915 | 0 | 4.202
483916 | 0 | 1.4
483917 | 0 | 2.801
483918 | 52.5826 | 5.377
483919 | 41.2977 | 4.349
483989 | 0 | 4.202
483990 | 0 | 1.401
483991 | 0 | 2.801
483992 | 52.4141 | 5.348
483993 | 41.0177 | 4.323
484071 | 0 | 4.202
484072 | 0 | 1.4
484073 | 0 | 2.801
484074 | 52.6114 | 5.375
484075 | 41.3273 | 4.346
484080 | 0 | 4.202
484081 | 0 | 1.401
484082 | 0 | 2.801
484083 | 52.6428 | 5.332
484084 | 41.2523 | 4.303
499894 | 0 | 4.192
499895 | 67.5111 | 2.268
499896 | 67.5111 | 2.268
499897 | 54.4061 | 5.154
499898 | 54.4061 | 5.154
499912 | 0 | 4.192
499913 | 67.5111 | 2.268
499914 | 67.5111 | 2.268
499915 | 54.4061 | 5.154
499916 | 54.4061 | 5.154
588035 | 0 | 4.192
588036 | 67.5111 | 2.268
588037 | 67.5111 | 2.268
588038 | 54.4061 | 5.154
588039 | 54.4061 | 5.154
588053 | 0 | 4.192
588054 | 67.5111 | 2.268
588055 | 67.5111 | 2.268
588056 | 54.4061 | 5.154
588057 | 54.4061 | 5.154
588073 | 0 | 4.192
588074 | 67.5111 | 2.268
588075 | 67.5111 | 2.268
588076 | 54.4061 | 5.154
588077 | 54.4061 | 5.154
588093 | 0 | 4.192
588094 | 67.5111 | 2.268
588095 | 67.5111 | 2.268
588096 | 54.4061 | 5.154
588097 | 54.4061 | 5.154
588115 | 0 | 4.192
588116 | 67.5111 | 2.268
588117 | 67.5111 | 2.268
588118 | 54.4061 | 5.154
588119 | 54.4061 | 5.154

# IfcMember: HSS-Tubo estructural redondo:HSS 0.01 (928)
In: Nivel 1
Type - PredefinedType: BRACE; Material: Metal - Calibre delgado
Type - Pset_MemberCommon - IsExternal: no; LoadBearing: yes
Pset_EnvironmentalImpactIndicators - Reference: HSS 0.01
Pset_MemberCommon - Roll: 0 deg; Reference: HSS 0.01
Name (HSS-Tubo estructural redondo:HSS 0.01:...) | Slope (deg) | Span (m)
473268 | 0 | 0.5
473269 | 0 | 0.5
473270 | 0 | 0.5
473271 | 0 | 0.5
473272 | 0 | 0.5
473273 | 0 | 0.5
473274 | 0 | 0.5
473275 | 0 | 0.5
473276 | 0 | 0.5
473277 | 0 | 0.5
473278 | 0 | 0.5
473279 | 0 | 0.5
473280 | 0 | 0.5
473281 | 0 | 0.5
473282 | 0 | 0.5
473283 | 50.3517 | 0.65
473284 | 50.3517 | 0.65
473285 | 50.3517 | 0.65
473286 | 50.3517 | 0.65
473287 | 50.3517 | 0.65
473288 | 50.3517 | 0.65
473289 | 50.3517 | 0.65
473290 | 50.3517 | 0.65
473291 | 50.3517 | 0.65
473292 | 50.3517 | 0.65
473293 | 50.3517 | 0.65
473294 | 50.3517 | 0.65
473295 | 50.3517 | 0.65
473296 | 50.3517 | 0.65
475002 | 0 | 0.5
475003 | 0 | 0.5
475004 | 0 | 0.5
475005 | 0 | 0.5
475006 | 0 | 0.5
475007 | 0 | 0.5
475008 | 0 | 0.5
475009 | 0 | 0.5
475010 | 0 | 0.5
475011 | 0 | 0.5
475012 | 0 | 0.5
475013 | 0 | 0.5
475014 | 0 | 0.5
475015 | 0 | 0.5
475016 | 0 | 0.5
475017 | 50.3517 | 0.65
475018 | 50.3517 | 0.65
475019 | 50.3517 | 0.65
475020 | 50.3517 | 0.65
475021 | 50.3517 | 0.65
475022 | 50.3517 | 0.65
475023 | 50.3517 | 0.65
475024 | 50.3517 | 0.65
475025 | 50.3517 | 0.65
475026 | 50.3517 | 0.65
475027 | 50.3517 | 0.65
475028 | 50.3517 | 0.65
475029 | 50.3517 | 0.65
475030 | 50.3517 | 0.65
475058 | 0 | 0.5
475059 | 0 | 0.5
475060 | 0 | 0.5
475061 | 0 | 0.5
475062 | 0 | 0.5
475063 | 0 | 0.5
475064 | 0 | 0.5
475065 | 0 | 0.5
475066 | 0 | 0.5
475067 | 0 | 0.5
475068 | 0 | 0.5
475069 | 0 | 0.5
475070 | 0 | 0.5
475071 | 0 | 0.5
475072 | 0 | 0.5
475073 | 50.3517 | 0.65
475074 | 50.3517 | 0.65
475075 | 50.3517 | 0.65
475076 | 50.3517 | 0.65
475077 | 50.3517 | 0.65
475078 | 50.3517 | 0.65
475079 | 50.3517 | 0.65
475080 | 50.3517 | 0.65
475081 | 50.3517 | 0.65
475082 | 50.3517 | 0.65
475083 | 50.3517 | 0.65
475084 | 50.3517 | 0.65
475085 | 50.3517 | 0.65
475086 | 50.3517 | 0.65
475091 | 0 | 0.5
475092 | 0 | 0.5
475093 | 0 | 0.5
475094 | 0 | 0.5
475095 | 0 | 0.5
475096 | 0 | 0.5
475097 | 0 | 0.5
475098 | 0 | 0.5
475099 | 0 | 0.5
475100 | 0 | 0.5
475101 | 0 | 0.5
475102 | 0 | 0.5
475103 | 0 | 0.5
475104 | 0 | 0.5
475105 | 0 | 0.5
475106 | 50.3517 | 0.65
475107 | 50.3517 | 0.65
475108 | 50.3517 | 0.65
475109 | 50.3517 | 0.65
475110 | 50.3517 | 0.65
475111 | 50.3517 | 0.65
475112 | 50.3517 | 0.65
475113 | 50.3517 | 0.65
475114 | 50.3517 | 0.65
475115 | 50.3517 | 0.65
475116 | 50.3517 | 0.65
475117 | 50.3517 | 0.65
475118 | 50.3517 | 0.65
475119 | 50.3517 | 0.65
475133 | 0 | 0.5
475134 | 0 | 0.5
475135 | 0 | 0.5
475136 | 0 | 0.5
475137 | 0 | 0.5
475138 | 0 | 0.5
475139 | 0 | 0.5
475140 | 0 | 0.5
475141 | 0 | 0.5
475142 | 0 | 0.5
475143 | 0 | 0.5
475144 | 0 | 0.5
475145 | 0 | 0.5
475146 | 0 | 0.5
475147 | 0 | 0.5
475148 | 50.3517 | 0.65
475149 | 50.3517 | 0.65
475150 | 50.3517 | 0.65
475151 | 50.3517 | 0.65
475152 | 50.3517 | 0.65
475153 | 50.3517 | 0.65
475154 | 50.3517 | 0.65
475155 | 50.3517 | 0.65
475156 | 50.3517 | 0.65
475157 | 50.3517 | 0.65
475158 | 50.3517 | 0.65
475159 | 50.3517 | 0.65
475160 | 50.3517 | 0.65
475161 | 50.3517 | 0.65
475166 | 0 | 0.5
475167 | 0 | 0.5
475168 | 0 | 0.5
475169 | 0 | 0.5
475170 | 0 | 0.5
475171 | 0 | 0.5
475172 | 0 | 0.5
475173 | 0 | 0.5
475174 | 0 | 0.5
475175 | 0 | 0.5
475176 | 0 | 0.5
475177 | 0 | 0.5
475178 | 0 | 0.5
475179 | 0 | 0.5
475180 | 0 | 0.5
475181 | 50.3517 | 0.65
475182 | 50.3517 | 0.65
475183 | 50.3517 | 0.65
475184 | 50.3517 | 0.65
475185 | 50.3517 | 0.65
475186 | 50.3517 | 0.65
475187 | 50.3517 | 0.65
475188 | 50.3517 | 0.65
475189 | 50.3517 | 0.65
475190 | 50.3517 | 0.65
475191 | 50.3517 | 0.65
475192 | 50.3517 | 0.65
475193 | 50.3517 | 0.65
475194 | 50.3517 | 0.65
475210 | 0 | 0.5
475211 | 0 | 0.5
475212 | 0 | 0.5
475213 | 0 | 0.5
475214 | 0 | 0.5
475215 | 0 | 0.5
475216 | 0 | 0.5
475217 | 0 | 0.5
475218 | 0 | 0.5
475219 | 0 | 0.5
475220 | 0 | 0.5
475221 | 0 | 0.5
475222 | 0 | 0.5
475223 | 0 | 0.5
475224 | 0 | 0.5
475225 | 50.3517 | 0.65
475226 | 50.3517 | 0.65
475227 | 50.3517 | 0.65
475228 | 50.3517 | 0.65
475229 | 50.3517 | 0.65
475230 | 50.3517 | 0.65
475231 | 50.3517 | 0.65
475232 | 50.3517 | 0.65
475233 | 50.3517 | 0.65
475234 | 50.3517 | 0.65
475235 | 50.3517 | 0.65
475236 | 50.3517 | 0.65
475237 | 50.3517 | 0.65
475238 | 50.3517 | 0.65
475243 | 0 | 0.5
475244 | 0 | 0.5
475245 | 0 | 0.5
475246 | 0 | 0.5
475247 | 0 | 0.5
475248 | 0 | 0.5
475249 | 0 | 0.5
475250 | 0 | 0.5
475251 | 0 | 0.5
475252 | 0 | 0.5
475253 | 0 | 0.5
475254 | 0 | 0.5
475255 | 0 | 0.5
475256 | 0 | 0.5
475257 | 0 | 0.5
475258 | 50.3517 | 0.65
475259 | 50.3517 | 0.65
475260 | 50.3517 | 0.65
475261 | 50.3517 | 0.65
475262 | 50.3517 | 0.65
475263 | 50.3517 | 0.65
475264 | 50.3517 | 0.65
475265 | 50.3517 | 0.65
475266 | 50.3517 | 0.65
475267 | 50.3517 | 0.65
475268 | 50.3517 | 0.65
475269 | 50.3517 | 0.65
475270 | 50.3517 | 0.65
475271 | 50.3517 | 0.65
475289 | 0 | 0.5
475290 | 0 | 0.5
475291 | 0 | 0.5
475292 | 0 | 0.5
475293 | 0 | 0.5
475294 | 0 | 0.5
475295 | 0 | 0.5
475296 | 0 | 0.5
475297 | 0 | 0.5
475298 | 0 | 0.5
475299 | 0 | 0.5
475300 | 0 | 0.5
475301 | 0 | 0.5
475302 | 0 | 0.5
475303 | 0 | 0.5
475304 | 50.3517 | 0.65
475305 | 50.3517 | 0.65
475306 | 50.3517 | 0.65
475307 | 50.3517 | 0.65
475308 | 50.3517 | 0.65
475309 | 50.3517 | 0.65
475310 | 50.3517 | 0.65
475311 | 50.3517 | 0.65
475312 | 50.3517 | 0.65
475313 | 50.3517 | 0.65
475314 | 50.3517 | 0.65
475315 | 50.3517 | 0.65
475316 | 50.3517 | 0.65
475317 | 50.3517 | 0.65
475322 | 0 | 0.5
475323 | 0 | 0.5
475324 | 0 | 0.5
475325 | 0 | 0.5
475326 | 0 | 0.5
475327 | 0 | 0.5
475328 | 0 | 0.5
475329 | 0 | 0.5
475330 | 0 | 0.5
475331 | 0 | 0.5
475332 | 0 | 0.5
475333 | 0 | 0.5
475334 | 0 | 0.5
475335 | 0 | 0.5
475336 | 0 | 0.5
475337 | 50.3517 | 0.65
475338 | 50.3517 | 0.65
475339 | 50.3517 | 0.65
475340 | 50.3517 | 0.65
475341 | 50.3517 | 0.65
475342 | 50.3517 | 0.65
475343 | 50.3517 | 0.65
475344 | 50.3517 | 0.65
475345 | 50.3517 | 0.65
475346 | 50.3517 | 0.65
475347 | 50.3517 | 0.65
475348 | 50.3517 | 0.65
475349 | 50.3517 | 0.65
475350 | 50.3517 | 0.65
475364 | 0 | 0.5
475365 | 0 | 0.5
475366 | 0 | 0.5
475367 | 0 | 0.5
475368 | 0 | 0.5
475369 | 0 | 0.5
475370 | 0 | 0.5
475371 | 0 | 0.5
475372 | 0 | 0.5
475373 | 0 | 0.5
475374 | 0 | 0.5
475375 | 0 | 0.5
475376 | 0 | 0.5
475377 | 0 | 0.5
475378 | 0 | 0.5
475379 | 50.3517 | 0.65
475380 | 50.3517 | 0.65
475381 | 50.3517 | 0.65
475382 | 50.3517 | 0.65
475383 | 50.3517 | 0.65
475384 | 50.3517 | 0.65
475385 | 50.3517 | 0.65
475386 | 50.3517 | 0.65
475387 | 50.3517 | 0.65
475388 | 50.3517 | 0.65
475389 | 50.3517 | 0.65
475390 | 50.3517 | 0.65
475391 | 50.3517 | 0.65
475392 | 50.3517 | 0.65
475397 | 0 | 0.5
475398 | 0 | 0.5
475399 | 0 | 0.5
475400 | 0 | 0.5
475401 | 0 | 0.5
475402 | 0 | 0.5
475403 | 0 | 0.5
475404 | 0 | 0.5
475405 | 0 | 0.5
475406 | 0 | 0.5
475407 | 0 | 0.5
475408 | 0 | 0.5
475409 | 0 | 0.5
475410 | 0 | 0.5
475411 | 0 | 0.5
475412 | 50.3517 | 0.65
475413 | 50.3517 | 0.65
475414 | 50.3517 | 0.65
475415 | 50.3517 | 0.65
475416 | 50.3517 | 0.65
475417 | 50.3517 | 0.65
475418 | 50.3517 | 0.65
475419 | 50.3517 | 0.65
475420 | 50.3517 | 0.65
475421 | 50.3517 | 0.65
475422 | 50.3517 | 0.65
475423 | 50.3517 | 0.65
475424 | 50.3517 | 0.65
475425 | 50.3517 | 0.65
475443 | 0 | 0.5
475444 | 0 | 0.5
475445 | 0 | 0.5
475446 | 0 | 0.5
475447 | 0 | 0.5
475448 | 0 | 0.5
475449 | 0 | 0.5
475450 | 0 | 0.5
475451 | 0 | 0.5
475452 | 0 | 0.5
475453 | 0 | 0.5
475454 | 0 | 0.5
475455 | 0 | 0.5
475456 | 0 | 0.5
475457 | 0 | 0.5
475458 | 50.3517 | 0.65
475459 | 50.3517 | 0.65
475460 | 50.3517 | 0.65
475461 | 50.3517 | 0.65
475462 | 50.3517 | 0.65
475463 | 50.3517 | 0.65
475464 | 50.3517 | 0.65
475465 | 50.3517 | 0.65
475466 | 50.3517 | 0.65
475467 | 50.3517 | 0.65
475468 | 50.3517 | 0.65
475469 | 50.3517 | 0.65
475470 | 50.3517 | 0.65
475471 | 50.3517 | 0.65
475476 | 0 | 0.5
475477 | 0 | 0.5
475478 | 0 | 0.5
475479 | 0 | 0.5
475480 | 0 | 0.5
475481 | 0 | 0.5
475482 | 0 | 0.5
475483 | 0 | 0.5
475484 | 0 | 0.5
475485 | 0 | 0.5
475486 | 0 | 0.5
475487 | 0 | 0.5
475488 | 0 | 0.5
475489 | 0 | 0.5
475490 | 0 | 0.5
475491 | 50.3517 | 0.65
475492 | 50.3517 | 0.65
475493 | 50.3517 | 0.65
475494 | 50.3517 | 0.65
475495 | 50.3517 | 0.65
475496 | 50.3517 | 0.65
475497 | 50.3517 | 0.65
475498 | 50.3517 | 0.65
475499 | 50.3517 | 0.65
475500 | 50.3517 | 0.65
475501 | 50.3517 | 0.65
475502 | 50.3517 | 0.65
475503 | 50.3517 | 0.65
475504 | 50.3517 | 0.65
475516 | 0 | 0.5
475517 | 0 | 0.5
475518 | 0 | 0.5
475519 | 0 | 0.5
475520 | 0 | 0.5
475521 | 0 | 0.5
475522 | 0 | 0.5
475523 | 0 | 0.5
475524 | 0 | 0.5
475525 | 0 | 0.5
475526 | 0 | 0.5
475527 | 0 | 0.5
475528 | 0 | 0.5
475529 | 0 | 0.5
475530 | 0 | 0.5
475531 | 50.3517 | 0.65
475532 | 50.3517 | 0.65
475533 | 50.3517 | 0.65
475534 | 50.3517 | 0.65
475535 | 50.3517 | 0.65
475536 | 50.3517 | 0.65
475537 | 50.3517 | 0.65
475538 | 50.3517 | 0.65
475539 | 50.3517 | 0.65
475540 | 50.3517 | 0.65
475541 | 50.3517 | 0.65
475542 | 50.3517 | 0.65
475543 | 50.3517 | 0.65
475544 | 50.3517 | 0.65
475549 | 0 | 0.5
475550 | 0 | 0.5
475551 | 0 | 0.5
475552 | 0 | 0.5
475553 | 0 | 0.5
475554 | 0 | 0.5
475555 | 0 | 0.5
475556 | 0 | 0.5
475557 | 0 | 0.5
475558 | 0 | 0.5
475559 | 0 | 0.5
475560 | 0 | 0.5
475561 | 0 | 0.5
475562 | 0 | 0.5
475563 | 0 | 0.5
475564 | 50.3517 | 0.65
475565 | 50.3517 | 0.65
475566 | 50.3517 | 0.65
475567 | 50.3517 | 0.65
475568 | 50.3517 | 0.65
475569 | 50.3517 | 0.65
475570 | 50.3517 | 0.65
475571 | 50.3517 | 0.65
475572 | 50.3517 | 0.65
475573 | 50.3517 | 0.65
475574 | 50.3517 | 0.65
475575 | 50.3517 | 0.65
475576 | 50.3517 | 0.65
475577 | 50.3517 | 0.65
476012 | 0 | 0.5
476013 | 0 | 0.5
476014 | 0 | 0.5
476015 | 0 | 0.5
476016 | 0 | 0.5
476017 | 0 | 0.5
476018 | 0 | 0.5
476019 | 0 | 0.5
476020 | 0 | 0.5
476021 | 0 | 0.5
476022 | 0 | 0.5
476023 | 0 | 0.5
476024 | 0 | 0.5
476025 | 0 | 0.5
476026 | 0 | 0.5
476027 | 61.8532 | 0.567
476028 | 61.8532 | 0.567
476029 | 61.8532 | 0.567
476030 | 61.8532 | 0.567
476031 | 61.8532 | 0.567
476032 | 61.8532 | 0.567
476033 | 61.8532 | 0.567
476034 | 61.8532 | 0.567
476035 | 61.8532 | 0.567
476036 | 61.8532 | 0.567
476037 | 61.8532 | 0.567
476038 | 61.8532 | 0.567
476039 | 61.8532 | 0.567
476040 | 61.8532 | 0.567
476045 | 0 | 0.5
476046 | 0 | 0.5
476047 | 0 | 0.5
476048 | 0 | 0.5
476049 | 0 | 0.5
476050 | 0 | 0.5
476051 | 0 | 0.5
476052 | 0 | 0.5
476053 | 0 | 0.5
476054 | 0 | 0.5
476055 | 0 | 0.5
476056 | 0 | 0.5
476057 | 0 | 0.5
476058 | 0 | 0.5
476059 | 0 | 0.5
476060 | 65.1289 | 0.551
476061 | 65.1289 | 0.551
476062 | 65.1289 | 0.551
476063 | 65.1289 | 0.551
476064 | 65.1289 | 0.551
476065 | 65.1289 | 0.551
476066 | 65.1289 | 0.551
476067 | 65.1289 | 0.551
476068 | 65.1289 | 0.551
476069 | 65.1289 | 0.551
476070 | 65.1289 | 0.551
476071 | 65.1289 | 0.551
476072 | 65.1289 | 0.551
476073 | 65.1289 | 0.551
484348 | 0 | 0.5
484349 | 0 | 0.5
484350 | 0 | 0.5
484351 | 0 | 0.5
484352 | 0 | 0.5
484353 | 0 | 0.5
484354 | 0 | 0.5
484355 | 0 | 0.5
484356 | 0 | 0.5
484357 | 0 | 0.5
484358 | 0 | 0.5
484359 | 0 | 0.5
484360 | 0 | 0.5
484361 | 0 | 0.5
484362 | 0 | 0.5
484363 | 61.8532 | 0.567
484364 | 61.8532 | 0.567
484365 | 61.8532 | 0.567
484366 | 61.8532 | 0.567
484367 | 61.8532 | 0.567
484368 | 61.8532 | 0.567
484369 | 61.8532 | 0.567
484370 | 61.8532 | 0.567
484371 | 61.8532 | 0.567
484372 | 61.8532 | 0.567
484373 | 61.8532 | 0.567
484374 | 61.8532 | 0.567
484375 | 61.8532 | 0.567
484376 | 61.8532 | 0.567
484381 | 0 | 0.5
484382 | 0 | 0.5
484383 | 0 | 0.5
484384 | 0 | 0.5
484385 | 0 | 0.5
484386 | 0 | 0.5
484387 | 0 | 0.5
484388 | 0 | 0.5
484389 | 0 | 0.5
484390 | 0 | 0.5
484391 | 0 | 0.5
484392 | 0 | 0.5
484393 | 0 | 0.5
484394 | 0 | 0.5
484395 | 0 | 0.5
484396 | 65.1289 | 0.551
484397 | 65.1289 | 0.551
484398 | 65.1289 | 0.551
484399 | 65.1289 | 0.551
484400 | 65.1289 | 0.551
484401 | 65.1289 | 0.551
484402 | 65.1289 | 0.551
484403 | 65.1289 | 0.551
484404 | 65.1289 | 0.551
484405 | 65.1289 | 0.551
484406 | 65.1289 | 0.551
484407 | 65.1289 | 0.551
484408 | 65.1289 | 0.551
484409 | 65.1289 | 0.551
484425 | 0 | 0.5
484426 | 0 | 0.5
484427 | 0 | 0.5
484428 | 0 | 0.5
484429 | 0 | 0.5
484430 | 0 | 0.5
484431 | 0 | 0.5
484432 | 0 | 0.5
484433 | 0 | 0.5
484434 | 0 | 0.5
484435 | 0 | 0.5
484436 | 0 | 0.5
484437 | 0 | 0.5
484438 | 0 | 0.5
484439 | 0 | 0.5
484440 | 61.8532 | 0.567
484441 | 61.8532 | 0.567
484442 | 61.8532 | 0.567
484443 | 61.8532 | 0.567
484444 | 61.8532 | 0.567
484445 | 61.8532 | 0.567
484446 | 61.8532 | 0.567
484447 | 61.8532 | 0.567
484448 | 61.8532 | 0.567
484449 | 61.8532 | 0.567
484450 | 61.8532 | 0.567
484451 | 61.8532 | 0.567
484452 | 61.8532 | 0.567
484453 | 61.8532 | 0.567
484458 | 0 | 0.5
484459 | 0 | 0.5
484460 | 0 | 0.5
484461 | 0 | 0.5
484462 | 0 | 0.5
484463 | 0 | 0.5
484464 | 0 | 0.5
484465 | 0 | 0.5
484466 | 0 | 0.5
484467 | 0 | 0.5
484468 | 0 | 0.5
484469 | 0 | 0.5
484470 | 0 | 0.5
484471 | 0 | 0.5
484472 | 0 | 0.5
484473 | 65.1289 | 0.551
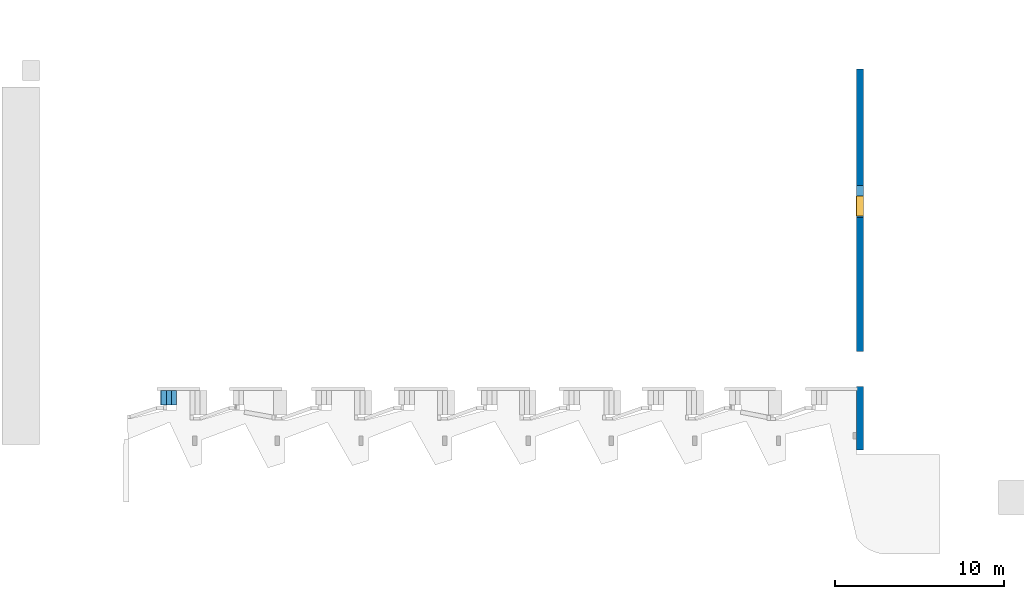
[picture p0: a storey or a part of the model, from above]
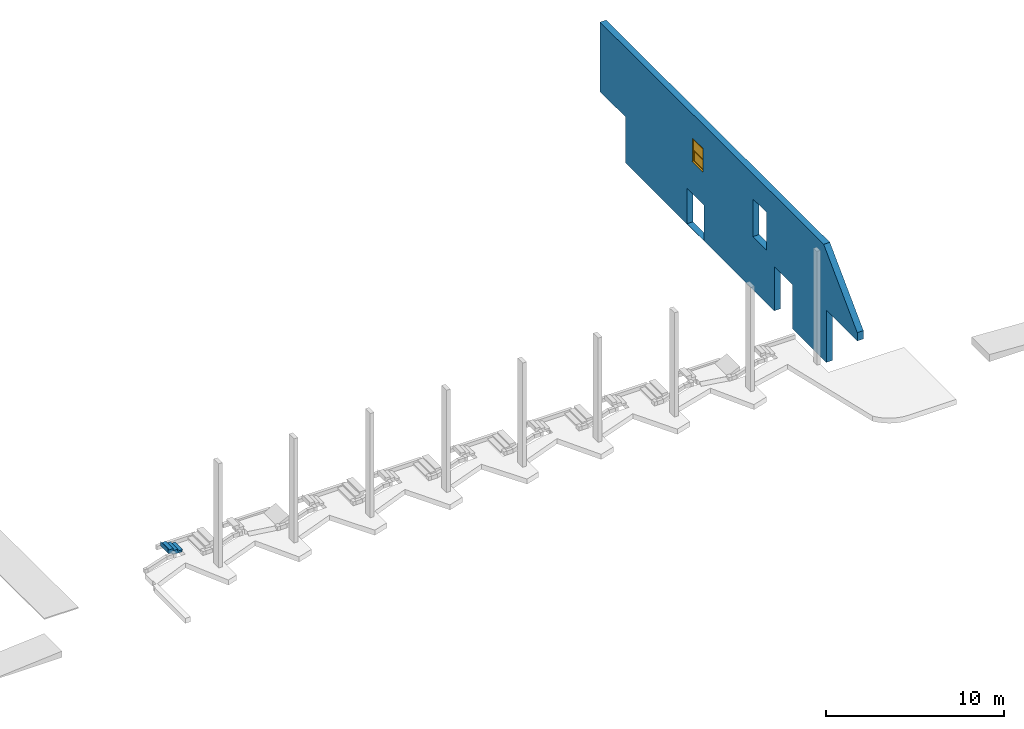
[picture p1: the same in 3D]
Properties of the parts of a building model (IFC4), part 2 of 3

# IfcMember: HSS-Tubo estructural redondo:HSS 0.01 (928)
Name (HSS-Tubo estructural redondo:HSS 0.01:...) | Slope (deg) | Span (m)
484474 | 65.1289 | 0.551
484475 | 65.1289 | 0.551
484476 | 65.1289 | 0.551
484477 | 65.1289 | 0.551
484478 | 65.1289 | 0.551
484479 | 65.1289 | 0.551
484480 | 65.1289 | 0.551
484481 | 65.1289 | 0.551
484482 | 65.1289 | 0.551
484483 | 65.1289 | 0.551
484484 | 65.1289 | 0.551
484485 | 65.1289 | 0.551
484486 | 65.1289 | 0.551
484498 | 0 | 0.5
484499 | 0 | 0.5
484500 | 0 | 0.5
484501 | 0 | 0.5
484502 | 0 | 0.5
484503 | 0 | 0.5
484504 | 0 | 0.5
484505 | 0 | 0.5
484506 | 0 | 0.5
484507 | 0 | 0.5
484508 | 0 | 0.5
484509 | 0 | 0.5
484510 | 0 | 0.5
484511 | 0 | 0.5
484512 | 0 | 0.5
484513 | 61.8532 | 0.567
484514 | 61.8532 | 0.567
484515 | 61.8532 | 0.567
484516 | 61.8532 | 0.567
484517 | 61.8532 | 0.567
484518 | 61.8532 | 0.567
484519 | 61.8532 | 0.567
484520 | 61.8532 | 0.567
484521 | 61.8532 | 0.567
484522 | 61.8532 | 0.567
484523 | 61.8532 | 0.567
484524 | 61.8532 | 0.567
484525 | 61.8532 | 0.567
484526 | 61.8532 | 0.567
484531 | 0 | 0.5
484532 | 0 | 0.5
484533 | 0 | 0.5
484534 | 0 | 0.5
484535 | 0 | 0.5
484536 | 0 | 0.5
484537 | 0 | 0.5
484538 | 0 | 0.5
484539 | 0 | 0.5
484540 | 0 | 0.5
484541 | 0 | 0.5
484542 | 0 | 0.5
484543 | 0 | 0.5
484544 | 0 | 0.5
484545 | 0 | 0.5
484546 | 65.1289 | 0.551
484547 | 65.1289 | 0.551
484548 | 65.1289 | 0.551
484549 | 65.1289 | 0.551
484550 | 65.1289 | 0.551
484551 | 65.1289 | 0.551
484552 | 65.1289 | 0.551
484553 | 65.1289 | 0.551
484554 | 65.1289 | 0.551
484555 | 65.1289 | 0.551
484556 | 65.1289 | 0.551
484557 | 65.1289 | 0.551
484558 | 65.1289 | 0.551
484559 | 65.1289 | 0.551
484573 | 0 | 0.5
484574 | 0 | 0.5
484575 | 0 | 0.5
484576 | 0 | 0.5
484577 | 0 | 0.5
484578 | 0 | 0.5
484579 | 0 | 0.5
484580 | 0 | 0.5
484581 | 0 | 0.5
484582 | 0 | 0.5
484583 | 0 | 0.5
484584 | 0 | 0.5
484585 | 0 | 0.5
484586 | 0 | 0.5
484587 | 0 | 0.5
484588 | 61.8532 | 0.567
484589 | 61.8532 | 0.567
484590 | 61.8532 | 0.567
484591 | 61.8532 | 0.567
484592 | 61.8532 | 0.567
484593 | 61.8532 | 0.567
484594 | 61.8532 | 0.567
484595 | 61.8532 | 0.567
484596 | 61.8532 | 0.567
484597 | 61.8532 | 0.567
484598 | 61.8532 | 0.567
484599 | 61.8532 | 0.567
484600 | 61.8532 | 0.567
484601 | 61.8532 | 0.567
484606 | 0 | 0.5
484607 | 0 | 0.5
484608 | 0 | 0.5
484609 | 0 | 0.5
484610 | 0 | 0.5
484611 | 0 | 0.5
484612 | 0 | 0.5
484613 | 0 | 0.5
484614 | 0 | 0.5
484615 | 0 | 0.5
484616 | 0 | 0.5
484617 | 0 | 0.5
484618 | 0 | 0.5
484619 | 0 | 0.5
484620 | 0 | 0.5
484621 | 65.1289 | 0.551
484622 | 65.1289 | 0.551
484623 | 65.1289 | 0.551
484624 | 65.1289 | 0.551
484625 | 65.1289 | 0.551
484626 | 65.1289 | 0.551
484627 | 65.1289 | 0.551
484628 | 65.1289 | 0.551
484629 | 65.1289 | 0.551
484630 | 65.1289 | 0.551
484631 | 65.1289 | 0.551
484632 | 65.1289 | 0.551
484633 | 65.1289 | 0.551
484634 | 65.1289 | 0.551
484648 | 0 | 0.5
484649 | 0 | 0.5
484650 | 0 | 0.5
484651 | 0 | 0.5
484652 | 0 | 0.5
484653 | 0 | 0.5
484654 | 0 | 0.5
484655 | 0 | 0.5
484656 | 0 | 0.5
484657 | 0 | 0.5
484658 | 0 | 0.5
484659 | 0 | 0.5
484660 | 0 | 0.5
484661 | 0 | 0.5
484662 | 0 | 0.5
484663 | 61.8532 | 0.567
484664 | 61.8532 | 0.567
484665 | 61.8532 | 0.567
484666 | 61.8532 | 0.567
484667 | 61.8532 | 0.567
484668 | 61.8532 | 0.567
484669 | 61.8532 | 0.567
484670 | 61.8532 | 0.567
484671 | 61.8532 | 0.567
484672 | 61.8532 | 0.567
484673 | 61.8532 | 0.567
484674 | 61.8532 | 0.567
484675 | 61.8532 | 0.567
484676 | 61.8532 | 0.567
484681 | 0 | 0.5
484682 | 0 | 0.5
484683 | 0 | 0.5
484684 | 0 | 0.5
484685 | 0 | 0.5
484686 | 0 | 0.5
484687 | 0 | 0.5
484688 | 0 | 0.5
484689 | 0 | 0.5
484690 | 0 | 0.5
484691 | 0 | 0.5
484692 | 0 | 0.5
484693 | 0 | 0.5
484694 | 0 | 0.5
484695 | 0 | 0.5
484696 | 65.1289 | 0.551
484697 | 65.1289 | 0.551
484698 | 65.1289 | 0.551
484699 | 65.1289 | 0.551
484700 | 65.1289 | 0.551
484701 | 65.1289 | 0.551
484702 | 65.1289 | 0.551
484703 | 65.1289 | 0.551
484704 | 65.1289 | 0.551
484705 | 65.1289 | 0.551
484706 | 65.1289 | 0.551
484707 | 65.1289 | 0.551
484708 | 65.1289 | 0.551
484709 | 65.1289 | 0.551
484723 | 0 | 0.5
484724 | 0 | 0.5
484725 | 0 | 0.5
484726 | 0 | 0.5
484727 | 0 | 0.5
484728 | 0 | 0.5
484729 | 0 | 0.5
484730 | 0 | 0.5
484731 | 0 | 0.5
484732 | 0 | 0.5
484733 | 0 | 0.5
484734 | 0 | 0.5
484735 | 0 | 0.5
484736 | 0 | 0.5
484737 | 0 | 0.5
484738 | 61.8532 | 0.567
484739 | 61.8532 | 0.567
484740 | 61.8532 | 0.567
484741 | 61.8532 | 0.567
484742 | 61.8532 | 0.567
484743 | 61.8532 | 0.567
484744 | 61.8532 | 0.567
484745 | 61.8532 | 0.567
484746 | 61.8532 | 0.567
484747 | 61.8532 | 0.567
484748 | 61.8532 | 0.567
484749 | 61.8532 | 0.567
484750 | 61.8532 | 0.567
484751 | 61.8532 | 0.567
484756 | 0 | 0.5
484757 | 0 | 0.5
484758 | 0 | 0.5
484759 | 0 | 0.5
484760 | 0 | 0.5
484761 | 0 | 0.5
484762 | 0 | 0.5
484763 | 0 | 0.5
484764 | 0 | 0.5
484765 | 0 | 0.5
484766 | 0 | 0.5
484767 | 0 | 0.5
484768 | 0 | 0.5
484769 | 0 | 0.5
484770 | 0 | 0.5
484771 | 65.1289 | 0.551
484772 | 65.1289 | 0.551
484773 | 65.1289 | 0.551
484774 | 65.1289 | 0.551
484775 | 65.1289 | 0.551
484776 | 65.1289 | 0.551
484777 | 65.1289 | 0.551
484778 | 65.1289 | 0.551
484779 | 65.1289 | 0.551
484780 | 65.1289 | 0.551
484781 | 65.1289 | 0.551
484782 | 65.1289 | 0.551
484783 | 65.1289 | 0.551
484784 | 65.1289 | 0.551
484800 | 0 | 0.5
484801 | 0 | 0.5
484802 | 0 | 0.5
484803 | 0 | 0.5
484804 | 0 | 0.5
484805 | 0 | 0.5
484806 | 0 | 0.5
484807 | 0 | 0.5
484808 | 0 | 0.5
484809 | 0 | 0.5
484810 | 0 | 0.5
484811 | 0 | 0.5
484812 | 0 | 0.5
484813 | 0 | 0.5
484814 | 0 | 0.5
484815 | 61.8532 | 0.567
484816 | 61.8532 | 0.567
484817 | 61.8532 | 0.567
484818 | 61.8532 | 0.567
484819 | 61.8532 | 0.567
484820 | 61.8532 | 0.567
484821 | 61.8532 | 0.567
484822 | 61.8532 | 0.567
484823 | 61.8532 | 0.567
484824 | 61.8532 | 0.567
484825 | 61.8532 | 0.567
484826 | 61.8532 | 0.567
484827 | 61.8532 | 0.567
484828 | 61.8532 | 0.567
484833 | 0 | 0.5
484834 | 0 | 0.5
484835 | 0 | 0.5
484836 | 0 | 0.5
484837 | 0 | 0.5
484838 | 0 | 0.5
484839 | 0 | 0.5
484840 | 0 | 0.5
484841 | 0 | 0.5
484842 | 0 | 0.5
484843 | 0 | 0.5
484844 | 0 | 0.5
484845 | 0 | 0.5
484846 | 0 | 0.5
484847 | 0 | 0.5
484848 | 65.1289 | 0.551
484849 | 65.1289 | 0.551
484850 | 65.1289 | 0.551
484851 | 65.1289 | 0.551
484852 | 65.1289 | 0.551
484853 | 65.1289 | 0.551
484854 | 65.1289 | 0.551
484855 | 65.1289 | 0.551
484856 | 65.1289 | 0.551
484857 | 65.1289 | 0.551
484858 | 65.1289 | 0.551
484859 | 65.1289 | 0.551
484860 | 65.1289 | 0.551
484861 | 65.1289 | 0.551

# IfcMember: Montante circular:Montante circular 1 (2)
In: Nivel 0
Type - PredefinedType: MULLION; Material: <Unnamed>
Type - Pset_MemberCommon - IsExternal: no
Pset_EnvironmentalImpactIndicators - Reference: Montante circular 1
Pset_MemberCommon - Reference: Montante circular 1
Name (Montante circular:Montante circular 1:...) | Span (m)
209721 | 0.015
219548 | 0.02

# IfcMember: Montante rectangular:Montante rectangular - 5 x 10 cm (1038)
Type - PredefinedType: MULLION; Material: <Unnamed>
Type - Pset_MemberCommon - IsExternal: no
Pset_EnvironmentalImpactIndicators - Reference: Montante rectangular - 5 x 10 cm
Pset_MemberCommon - Reference: Montante rectangular - 5 x 10 cm
Name (Montante rectangular:Montante rectangular - 5 x 10 cm:...) | In | Span (m)
206809 | Nivel 0 | 0.015
208829 | Nivel 0 | 1.25
209052 | Nivel 0 | 1.655
209390 | Nivel 0 | 1.25
209640 | Nivel 0 | 0.025
209641 | Nivel 0 | 0.025
209720 | Nivel 0 | 1.655
222634 | Nivel 0 | 1.705
222635 | Nivel 0 | 0.04
211328 | Nivel 0 | 0.02
211435 | Nivel 0 | 2.33
211522 | Nivel 0 | 1.87647
211642 | Nivel 0 | 2.355
212562 | Nivel 0 | 1.79853
212571 | Nivel 0 | 0.025
212573 | Nivel 0 | 1.79853
212644 | Nivel 0 | 1.25
213123 | Nivel 0 | 1.275
213291 | Nivel 0 | 0.02
213376 | Nivel 0 | 1.23
213511 | Nivel 0 | 1.71635
213573 | Nivel 0 | 1.255
213583 | Nivel 0 | 1.71635
214994 | Nivel 0 | 2.35
214998 | Nivel 0 | 2.35
215862 | Nivel 0 | 2.35
215863 | Nivel 0 | 2.35
216032 | Nivel 0 | 2.35
216033 | Nivel 0 | 2.35
387981 | Nivel 0 | 1.105
387982 | Nivel 0 | 1.71
387983 | Nivel 0 | 0.91
219530 | Nivel 0 | 0.02
219535 | Nivel 0 | 1.25
219536 | Nivel 0 | 1.655
219540 | Nivel 0 | 1.25
219545 | Nivel 0 | 0.025
219546 | Nivel 0 | 0.025
219547 | Nivel 0 | 1.655
219893 | Nivel 0 | 0.02
219897 | Nivel 0 | 1.23
219903 | Nivel 0 | 1.89488
219905 | Nivel 0 | 1.89488
220163 | Nivel 0 | 1.255
221190 | Nivel 0 | 2.26
221273 | Nivel 0 | 2.26
221229 | Nivel 0 | 0.809203
220356 | Nivel 0 | 0.025
220357 | Nivel 0 | 0.025
220593 | Nivel 0 | 1.35
220594 | Nivel 0 | 1.35
220728 | Nivel 0 | 0.809203
220729 | Nivel 0 | 2.26
220866 | Nivel 0 | 0.975
220867 | Nivel 0 | 0.975
220956 | Nivel 0 | 0.809203
220957 | Nivel 0 | 2.26
390321 | Nivel 0 | 2.0469
390324 | Nivel 0 | 2.35
390348 | Nivel 0 | 2.0469
241494 | Nivel 0 | 0.02
310116 | Nivel 0 | 2.025
310117 | Nivel 0 | 0.02
310231 | Nivel 0 | 2.05
310232 | Nivel 0 | 0.02
310328 | Nivel 0 | 2.315
250117 | Nivel 0 | 0.875
250169 | Nivel 0 | 1
250255 | Nivel 0 | 0.875
250438 | Nivel 0 | 1.13
250439 | Nivel 0 | 0.834435
250440 | Nivel 0 | 0.834435
250498 | Nivel 0 | 1.155
250499 | Nivel 0 | 1.13
250500 | Nivel 0 | 0.875
250538 | Nivel 0 | 0.665
250539 | Nivel 0 | 1.025
250550 | Nivel 0 | 0.665
250551 | Nivel 0 | 1.025
250682 | Nivel 0 | 0.665
250683 | Nivel 0 | 0.665
250711 | Nivel 0 | 1.13
250712 | Nivel 0 | 0.834435
250713 | Nivel 0 | 0.875
250820 | Nivel 0 | 1.13
250821 | Nivel 0 | 1.155
250822 | Nivel 0 | 1.13
250823 | Nivel 0 | 1.13
250857 | Nivel 0 | 0.665
250858 | Nivel 0 | 0.69
252058 | Nivel 0 | 1.57128
252060 | Nivel 0 | 1.31
252062 | Nivel 0 | 1.025
252108 | Nivel 0 | 1.025
252109 | Nivel 0 | 1.31
253574 | Nivel 0 | 1.49628
253605 | Nivel 0 | 1.49628
252746 | Nivel 0 | 1.025
252749 | Nivel 0 | 1.72298
252753 | Nivel 0 | 1.025
252756 | Nivel 0 | 1.72298
252881 | Nivel 0 | 1.335
252882 | Nivel 0 | 1.335
252910 | Nivel 0 | 1.72298
269160 | Nivel 0 | 0.875
269246 | Nivel 0 | 0.875
269247 | Nivel 0 | 1.85
269323 | Nivel 0 | 1.85
269324 | Nivel 0 | 0.775
269358 | Nivel 0 | 1.025
269531 | Nivel 0 | 0.665
269603 | Nivel 0 | 1.85
269604 | Nivel 0 | 0.875
270732 | Nivel 0 | 0.665
270938 | Nivel 0 | 1.85
398533 | Nivel 0 | 0.665
398534 | Nivel 0 | 0.665
398535 | Nivel 0 | 1.025
270600 | Nivel 0 | 1.87723
270602 | Nivel 0 | 1.025
270605 | Nivel 0 | 1.82723
270609 | Nivel 0 | 1.025
270666 | Nivel 0 | 1.31
270667 | Nivel 0 | 1.31
270688 | Nivel 0 | 1.82723
271026 | Nivel 0 | 0.85
271027 | Nivel 0 | 1.025
271037 | Nivel 0 | 2.41953
271038 | Nivel 0 | 0.85
271040 | Nivel 0 | 1.025
271047 | Nivel 0 | 0.665
271049 | Nivel 0 | 0.665
271060 | Nivel 0 | 0.665
271062 | Nivel 0 | 0.665
271408 | Nivel 0 | 0.83
271409 | Nivel 0 | 2.41953
271410 | Nivel 0 | 2.41953
271473 | Nivel 0 | 0.665
271474 | Nivel 0 | 0.665
271475 | Nivel 0 | 1.025
271488 | Nivel 0 | 2.41953
272089 | Nivel 0 | 0.83
272090 | Nivel 0 | 0.83
272176 | Nivel 0 | 0.665
272177 | Nivel 0 | 0.665
272178 | Nivel 0 | 1.025
271869 | Nivel 0 | 0.85
271870 | Nivel 0 | 1.025
271874 | Nivel 0 | 1.91047
271875 | Nivel 0 | 0.85
271876 | Nivel 0 | 1.025
271881 | Nivel 0 | 0.665
271882 | Nivel 0 | 0.665
271887 | Nivel 0 | 0.665
271888 | Nivel 0 | 0.665
271889 | Nivel 0 | 0.875
271890 | Nivel 0 | 0.875
271896 | Nivel 0 | 0.875
271897 | Nivel 0 | 1.91047
271898 | Nivel 0 | 1.91047
271902 | Nivel 0 | 1.91047
399874 | Nivel 0 | 0.665
399875 | Nivel 0 | 0.665
399876 | Nivel 0 | 1.025
400488 | Nivel 0 | 2.305
400491 | Nivel 0 | 0.8
400614 | Nivel 0 | 2.305
273387 | Nivel 0 | 0.825
273388 | Nivel 0 | 2.425
273392 | Nivel 0 | 2.425
273393 | Nivel 0 | 0.9
273405 | Nivel 0 | 2.425
400595 | Nivel 0 | 0.665
400596 | Nivel 0 | 1.025
400597 | Nivel 0 | 0.665
400603 | Nivel 0 | 0.825
400608 | Nivel 0 | 0.9
400609 | Nivel 0 | 2.45
400610 | Nivel 0 | 0.9
400621 | Nivel 0 | 0.665
400622 | Nivel 0 | 0.665
400623 | Nivel 0 | 1.025
274576 | Nivel 0 | 1.81609
274580 | Nivel 0 | 1.29
274581 | Nivel 0 | 1.025
274586 | Nivel 0 | 1.81609
274588 | Nivel 0 | 1.29
274589 | Nivel 0 | 1.025
274613 | Nivel 0 | 0.02
274614 | Nivel 0 | 0.02
274742 | Nivel 0 | 1.81609
275546 | Nivel 0 | 1.87723
275547 | Nivel 0 | 1.025
275549 | Nivel 0 | 1.025
275554 | Nivel 0 | 1.31
275555 | Nivel 0 | 1.31
275556 | Nivel 0 | 1.82723
594707 | Nivel 0 | 1.82723
275635 | Nivel 0 | 1.87723
275636 | Nivel 0 | 1.025
275637 | Nivel 0 | 1.82723
275638 | Nivel 0 | 1.025
275643 | Nivel 0 | 1.31
275644 | Nivel 0 | 1.31
275645 | Nivel 0 | 1.82723
275682 | Nivel 0 | 1.87723
275683 | Nivel 0 | 1.025
275684 | Nivel 0 | 1.82723
275685 | Nivel 0 | 1.025
275690 | Nivel 0 | 1.31
275691 | Nivel 0 | 1.31
275692 | Nivel 0 | 1.82723
279069 | Nivel 0 | 0.85
276363 | Nivel 0 | 0.9
276365 | Nivel 0 | 1.025
276368 | Nivel 0 | 0.85
276372 | Nivel 0 | 1.025
276448 | Nivel 0 | 1.68
276449 | Nivel 0 | 0.85
276555 | Nivel 0 | 1.63
276556 | Nivel 0 | 0.9
276585 | Nivel 0 | 1.025
276589 | Nivel 0 | 1.025
276653 | Nivel 0 | 0.655
276654 | Nivel 0 | 0.655
276655 | Nivel 0 | 0.655
276656 | Nivel 0 | 0.655
276735 | Nivel 0 | 1.63
276903 | Nivel 0 | 0.655
276904 | Nivel 0 | 0.655
276905 | Nivel 0 | 0.655
276906 | Nivel 0 | 0.655
276993 | Nivel 0 | 1.63
277219 | Nivel 0 | 0.85
277220 | Nivel 0 | 1.025
277225 | Nivel 0 | 1.81025
277226 | Nivel 0 | 0.825
277231 | Nivel 0 | 1.76025
277232 | Nivel 0 | 0.9
277233 | Nivel 0 | 1.025
277242 | Nivel 0 | 0.655
277243 | Nivel 0 | 0.655
277245 | Nivel 0 | 1.76025
277246 | Nivel 0 | 0.825
277256 | Nivel 0 | 0.655
277257 | Nivel 0 | 0.655
277259 | Nivel 0 | 1.76025
277486 | Nivel 0 | 0.655
277487 | Nivel 0 | 0.655
277488 | Nivel 0 | 1.025
277495 | Nivel 0 | 0.9
277497 | Nivel 0 | 0.825
277501 | Nivel 0 | 0.655
277502 | Nivel 0 | 0.655
277503 | Nivel 0 | 1.025
278640 | Nivel 0 | 1.025
278643 | Nivel 0 | 0.9
278645 | Nivel 0 | 0.85
278649 | Nivel 0 | 1.025
278717 | Nivel 0 | 2.02
278718 | Nivel 0 | 0.85
278818 | Nivel 0 | 1.97
278819 | Nivel 0 | 0.9
278844 | Nivel 0 | 1.025
278848 | Nivel 0 | 1.025
278900 | Nivel 0 | 1.31
278901 | Nivel 0 | 1.31
278902 | Nivel 0 | 1.31
278903 | Nivel 0 | 1.31
278957 | Nivel 0 | 1.97
278958 | Nivel 0 | 0.85
395820 | Nivel 0 | 2.285
280607 | Nivel 0 | 0.95
280608 | Nivel 0 | 2.365
280670 | Nivel 0 | 2.39
280671 | Nivel 0 | 1.075
280781 | Nivel 0 | 2.365
395723 | Nivel 0 | 0.95
395825 | Nivel 0 | 1.1
395877 | Nivel 0 | 1.31
395878 | Nivel 0 | 0.825
395954 | Nivel 0 | 0.2
396025 | Nivel 0 | 2.365
280869 | Nivel 0 | 1.93853
280871 | Nivel 0 | 1.88853
280872 | Nivel 0 | 1.025
280878 | Nivel 0 | 1.31
280879 | Nivel 0 | 1.93853
280959 | Nivel 0 | 1.285
280960 | Nivel 0 | 1
289186 | Nivel 0 | 0.425
289189 | Nivel 0 | 0.57821
289195 | Nivel 0 | 0.425
289235 | Nivel 0 | 1.51
289236 | Nivel 0 | 1.51
289300 | Nivel 0 | 0.57821
289301 | Nivel 0 | 0.62821
289349 | Nivel 0 | 0.62821
289350 | Nivel 0 | 0.44858
289401 | Nivel 0 | 0.4
289402 | Nivel 0 | 0.4
289484 | Nivel 0 | 0.4
289485 | Nivel 0 | 1.51
289486 | Nivel 0 | 0.425
289492 | Nivel 0 | 0.57821
289497 | Nivel 0 | 0.4
289498 | Nivel 0 | 1.51
289499 | Nivel 0 | 0.425
289502 | Nivel 0 | 0.44858
289503 | Nivel 0 | 0.57821
289504 | Nivel 0 | 0.57821
289989 | Nivel 0 | 1.78762
289990 | Nivel 0 | 1.025
289997 | Nivel 0 | 1.31
616844 | Nivel 0 | 1.025
616845 | Nivel 0 | 1.31
616850 | Nivel 0 | 1.71262
519790 | Nivel 0 | 2.155
519791 | Nivel 0 | 1.045
519792 | Nivel 0 | 0.875
519794 | Nivel 0 | 0.125
519803 | Nivel 0 | 0.2
519804 | Nivel 0 | 1.325
519805 | Nivel 0 | 0.835
519815 | Nivel 0 | 0.2
519816 | Nivel 0 | 1.325
519817 | Nivel 0 | 0.835
519836 | Nivel 0 | 0.2
519837 | Nivel 0 | 1.325
519838 | Nivel 0 | 0.835
519863 | Nivel 0 | 2.155
519864 | Nivel 0 | 1.045
519876 | Nivel 0 | 2.155
519877 | Nivel 0 | 1.045
519887 | Nivel 0 | 2.155
519888 | Nivel 0 | 1.045
519889 | Nivel 0 | 0.875
519890 | Nivel 0 | 0.125
617863 | Nivel 0 | 0.2
617864 | Nivel 0 | 1.325
617865 | Nivel 0 | 0.835
510549 | Nivel 0 | 1.71872
308320 | Nivel 0 | 0.65
308321 | Nivel 0 | 0.65
308413 | Nivel 0 | 0.95
308414 | Nivel 0 | 0.975
308526 | Nivel 0 | 1.71872
308531 | Nivel 0 | 1.71872
431126 | Nivel 0 | 0.383867
510351 | Nivel 0 | 0.72612
510410 | Nivel 0 | 1.76872
320576 | Nivel 0 | 0.2
320593 | Nivel 0 | 0.2
320614 | Nivel 0 | 1.90402
320615 | Nivel 0 | 0.89
320617 | Nivel 0 | 0.88
431761 | Nivel 0 | 0.593649
431765 | Nivel 0 | 0.566816
431769 | Nivel 0 | 1.9542
431770 | Nivel 0 | 0.940089
431772 | Nivel 0 | 0.95509
432447 | Nivel 0 | 0.0500047
433015 | Nivel 0 | 0.606763
433018 | Nivel 0 | 2.13571
433047 | Nivel 0 | 0.89
433048 | Nivel 0 | 0.88
433049 | Nivel 0 | 1.90402
433050 | Nivel 0 | 0.025
433106 | Nivel 0 | 2.13571
433107 | Nivel 0 | 2.13571
433109 | Nivel 0 | 0.2
511463 | Nivel 0 | 0.2
511464 | Nivel 0 | 2.13571
511465 | Nivel 0 | 0.553908
310848 | Nivel 0 | 0.71
310849 | Nivel 0 | 1.705
310851 | Nivel 0 | 0.71
310860 | Nivel 0 | 0.65
310861 | Nivel 0 | 0.65
310867 | Nivel 0 | 0.95
310868 | Nivel 0 | 0.95
310869 | Nivel 0 | 1.705
310870 | Nivel 0 | 1.705
515643 | Nivel 0 | 1.80543
515646 | Nivel 0 | 0.331414
515733 | Nivel 0 | 0.292177
326267 | Nivel 0 | 0.2
326268 | Nivel 0 | 1.435
326269 | Nivel 0 | 0.725
326279 | Nivel 0 | 0.2
326280 | Nivel 0 | 1.435
326281 | Nivel 0 | 0.725
326285 | Nivel 0 | 0.85
326286 | Nivel 0 | 1.91
326295 | Nivel 0 | 0.85
326296 | Nivel 0 | 1.91
326302 | Nivel 0 | 0.2
326303 | Nivel 0 | 1.435
326304 | Nivel 0 | 0.725
326308 | Nivel 0 | 0.85
326309 | Nivel 0 | 1.91
326318 | Nivel 0 | 0.85
326319 | Nivel 0 | 1.91
329179 | Nivel 0 | 2.29
329180 | Nivel 0 | 0.930292
329189 | Nivel 0 | 2.29
329190 | Nivel 0 | 0.930292
329196 | Nivel 0 | 0.2
329197 | Nivel 0 | 1.41
329198 | Nivel 0 | 0.725
329207 | Nivel 0 | 0.2
329208 | Nivel 0 | 1.41
329209 | Nivel 0 | 0.725
329214 | Nivel 0 | 2.29
329215 | Nivel 0 | 0.930292
329216 | Nivel 0 | 0.875
329225 | Nivel 0 | 0.9
329226 | Nivel 0 | 2.34
329229 | Nivel 0 | 0.7
329230 | Nivel 0 | 0.2
329231 | Nivel 0 | 1.41
353873 | Nivel 1 | 1.02139
353876 | Nivel 1 | 0.35
353883 | Nivel 1 | 1.02139
354491 | Nivel 1 | 0.4
354534 | Nivel 1 | 0.35
354535 | Nivel 1 | 1.185
354604 | Nivel 1 | 1.135
354605 | Nivel 1 | 0.4
354651 | Nivel 1 | 0.4
354652 | Nivel 1 | 0.4
354773 | Nivel 1 | 0.4
354774 | Nivel 1 | 1.02139
354781 | Nivel 1 | 1.135
354782 | Nivel 1 | 0.35
354783 | Nivel 1 | 0.35
354792 | Nivel 1 | 0.4
354793 | Nivel 1 | 1.02139
356232 | Nivel 1 | 0.425
356233 | Nivel 1 | 1.05948
356240 | Nivel 1 | 0.425
356241 | Nivel 1 | 1.05948
356244 | Nivel 1 | 1.1
356245 | Nivel 1 | 0.35
356246 | Nivel 1 | 0.35
356255 | Nivel 1 | 1.1
356256 | Nivel 1 | 0.35
356257 | Nivel 1 | 0.35
356261 | Nivel 1 | 0.425
356262 | Nivel 1 | 1.05948
356264 | Nivel 1 | 0.425
356265 | Nivel 1 | 1.05948
356266 | Nivel 1 | 1.1
356267 | Nivel 1 | 0.35
356268 | Nivel 1 | 0.35
357571 | Nivel 1 | 2.295
357573 | Nivel 1 | 0.2
357574 | Nivel 1 | 1.25
357575 | Nivel 1 | 0.81
357579 | Nivel 1 | 2.295
357585 | Nivel 1 | 2.295
357588 | Nivel 1 | 2.295
361430 | Nivel 1 | 0.2
361431 | Nivel 1 | 1.25
361432 | Nivel 1 | 0.835
361433 | Nivel 1 | 0.07
361444 | Nivel 1 | 0.07
403375 | Nivel 1 | 0.2
403376 | Nivel 1 | 1.25
403377 | Nivel 1 | 0.835
358304 | Nivel 1 | 0.2
358305 | Nivel 1 | 1.25
358306 | Nivel 1 | 0.835
358311 | Nivel 1 | 0.2
358312 | Nivel 1 | 1.25
358313 | Nivel 1 | 0.835
358324 | Nivel 1 | 1.895
358329 | Nivel 1 | 1.895
358332 | Nivel 1 | 0.85
358333 | Nivel 1 | 1.895
358337 | Nivel 1 | 0.81
358338 | Nivel 1 | 0.2
358339 | Nivel 1 | 1.25
361361 | Nivel 1 | 1.92
361362 | Nivel 1 | 0.875
361408 | Nivel 1 | 0.07
361441 | Nivel 1 | 0.07
358973 | Nivel 1 | 2.15616
358978 | Nivel 1 | 2.15616
358981 | Nivel 1 | 0.2
358982 | Nivel 1 | 1.32
358983 | Nivel 1 | 0.835
358988 | Nivel 1 | 2.15616
358989 | Nivel 1 | 0.91
358993 | Nivel 1 | 0.91
358997 | Nivel 1 | 0.81
358998 | Nivel 1 | 0.2
360148 | Nivel 1 | 0.2
360149 | Nivel 1 | 1.32
360150 | Nivel 1 | 0.835
361413 | Nivel 1 | 0.2
361414 | Nivel 1 | 1.32
361416 | Nivel 1 | 0.835
361872 | Nivel 1 | 0.91
361875 | Nivel 1 | 0.91
536141 | Nivel 1 | 2.15616
362876 | Nivel 1 | 0.85
362721 | Nivel 1 | 0.2
362722 | Nivel 1 | 1.25
362723 | Nivel 1 | 0.835
362724 | Nivel 1 | 0.2
362725 | Nivel 1 | 1.25
362726 | Nivel 1 | 0.835
362729 | Nivel 1 | 1.895
362730 | Nivel 1 | 1.895
362731 | Nivel 1 | 0.85
362732 | Nivel 1 | 1.895
362733 | Nivel 1 | 0.81
362734 | Nivel 1 | 0.2
362735 | Nivel 1 | 1.25
362782 | Nivel 1 | 1.92
362783 | Nivel 1 | 0.875
362786 | Nivel 1 | 0.07
362871 | Nivel 1 | 0.85
362766 | Nivel 1 | 2.14431
362767 | Nivel 1 | 2.14431
362768 | Nivel 1 | 0.2
362769 | Nivel 1 | 1.32
362770 | Nivel 1 | 0.835
362771 | Nivel 1 | 2.14431
362772 | Nivel 1 | 0.91
362773 | Nivel 1 | 0.91
362775 | Nivel 1 | 0.81
362776 | Nivel 1 | 0.2
362779 | Nivel 1 | 0.2
362780 | Nivel 1 | 1.32
362781 | Nivel 1 | 0.835
362787 | Nivel 1 | 0.2
362788 | Nivel 1 | 1.32
362790 | Nivel 1 | 0.835
536274 | Nivel 1 | 2.14431
363460 | Nivel 1 | 2.3
363466 | Nivel 1 | 1.675
363467 | Nivel 1 | 0.9
363477 | Nivel 1 | 0.825
363478 | Nivel 1 | 1.625
363479 | Nivel 1 | 0.875
363489 | Nivel 1 | 2.3
364244 | Nivel 1 | 2.3
364245 | Nivel 1 | 0.05
404577 | Nivel 1 | 2.3
366688 | Nivel 1 | 0.85
366614 | Nivel 1 | 0.2
366615 | Nivel 1 | 1.25
366616 | Nivel 1 | 0.835
366617 | Nivel 1 | 0.2
366618 | Nivel 1 | 1.25
366619 | Nivel 1 | 0.835
366620 | Nivel 1 | 1.895
366621 | Nivel 1 | 1.895
366622 | Nivel 1 | 0.85
366623 | Nivel 1 | 1.895
366624 | Nivel 1 | 0.81
366625 | Nivel 1 | 0.2
366626 | Nivel 1 | 1.25
366673 | Nivel 1 | 1.92
366674 | Nivel 1 | 0.875
366675 | Nivel 1 | 0.07
366687 | Nivel 1 | 0.85
366657 | Nivel 1 | 2.14431
366658 | Nivel 1 | 2.14431
366659 | Nivel 1 | 0.2
366660 | Nivel 1 | 1.32
366661 | Nivel 1 | 0.835
366662 | Nivel 1 | 2.14431
366663 | Nivel 1 | 0.91
366664 | Nivel 1 | 0.91
366666 | Nivel 1 | 0.81
366667 | Nivel 1 | 0.2
366670 | Nivel 1 | 0.2
366671 | Nivel 1 | 1.32
366672 | Nivel 1 | 0.835
366676 | Nivel 1 | 0.2
366677 | Nivel 1 | 1.32
366679 | Nivel 1 | 0.835
366720 | Nivel 1 | 0.91
367026 | Nivel 1 | 0.91
535799 | Nivel 1 | 2.14431
385822 | Nivel 0 | 0.55
385825 | Nivel 0 | 0.675
386047 | Nivel 0 | 1.125
386048 | Nivel 0 | 0.55
386098 | Nivel 0 | 1.125
386099 | Nivel 0 | 0.55
386106 | Nivel 0 | 0.875
386107 | Nivel 0 | 2.37
386123 | Nivel 0 | 1.125
386124 | Nivel 0 | 0.55
386131 | Nivel 0 | 2.37
386132 | Nivel 0 | 1.125
386133 | Nivel 0 | 0.875
386142 | Nivel 0 | 0.875
386143 | Nivel 0 | 2.37
386144 | Nivel 0 | 1.125
386219 | Nivel 0 | 1.125
386220 | Nivel 0 | 0.675
386221 | Nivel 0 | 0.675
386222 | Nivel 0 | 0.675
386273 | Nivel 0 | 2.37
387970 | Nivel 0 | 1.05
387973 | Nivel 0 | 1.19333
387977 | Nivel 0 | 0.65
387991 | Nivel 0 | 1.19333
388252 | Nivel 0 | 1.21833
388253 | Nivel 0 | 1.19333
388331 | Nivel 0 | 1.21833
388332 | Nivel 0 | 1.19333
388819 | Nivel 0 | 0.65
388820 | Nivel 0 | 1.05
388848 | Nivel 0 | 0.65
388849 | Nivel 0 | 1.05
388860 | Nivel 0 | 0.65
388861 | Nivel 0 | 1.05
388864 | Nivel 0 | 1.19333
388865 | Nivel 0 | 1.21833
388866 | Nivel 0 | 1.19333
389378 | Nivel 0 | 0.65
389379 | Nivel 0 | 0.65
389380 | Nivel 0 | 0.65
389381 | Nivel 0 | 0.65
389596 | Nivel 0 | 1.19333
389597 | Nivel 0 | 1.21833
389598 | Nivel 0 | 1.19333
387996 | Nivel 0 | 0.885
388002 | Nivel 0 | 0.65
388006 | Nivel 0 | 1.05
388010 | Nivel 0 | 0.885
388404 | Nivel 0 | 0.885
388405 | Nivel 0 | 0.885
388737 | Nivel 0 | 1.05
388738 | Nivel 0 | 0.65
388879 | Nivel 0 | 0.65
388880 | Nivel 0 | 1.05
388891 | Nivel 0 | 0.885
388892 | Nivel 0 | 0.885
389443 | Nivel 0 | 0.65
389444 | Nivel 0 | 0.65
389445 | Nivel 0 | 0.65
389607 | Nivel 0 | 0.885
389608 | Nivel 0 | 0.885
387999 | Nivel 0 | 1.6
388013 | Nivel 0 | 0.65
388017 | Nivel 0 | 1.05
388021 | Nivel 0 | 1.6
388674 | Nivel 0 | 1.05
388675 | Nivel 0 | 0.65
388887 | Nivel 0 | 1.6
389506 | Nivel 0 | 0.65
389507 | Nivel 0 | 0.65
389610 | Nivel 0 | 1.6
388024 | Nivel 0 | 0.875
388027 | Nivel 0 | 0.65
388031 | Nivel 0 | 0.875
388034 | Nivel 0 | 1.05
388488 | Nivel 0 | 1.725
388489 | Nivel 0 | 0.875
388537 | Nivel 0 | 1.725
388538 | Nivel 0 | 0.875
388607 | Nivel 0 | 1.05
388608 | Nivel 0 | 0.65
388896 | Nivel 0 | 0.65
388897 | Nivel 0 | 1.05
388905 | Nivel 0 | 0.65
388906 | Nivel 0 | 1.05
388911 | Nivel 0 | 1.725
388912 | Nivel 0 | 0.875
388913 | Nivel 0 | 0.875
389552 | Nivel 0 | 0.65
389553 | Nivel 0 | 0.65
389554 | Nivel 0 | 0.65
389555 | Nivel 0 | 0.65
389612 | Nivel 0 | 1.725
389613 | Nivel 0 | 0.875
389614 | Nivel 0 | 0.875
391328 | Nivel 0 | 1.43
391329 | Nivel 0 | 0.38
391393 | Nivel 0 | 2.77843
391394 | Nivel 0 | 0.919828
391401 | Nivel 0 | 0.975
391529 | Nivel 0 | 0.919828
391530 | Nivel 0 | 1.84
391658 | Nivel 0 | 1.84
391659 | Nivel 0 | 1.125
391679 | Nivel 0 | 1.125
391680 | Nivel 0 | 1.31174
391697 | Nivel 0 | 0.975
391704 | Nivel 0 | 0.975
391737 | Nivel 0 | 0.9
391738 | Nivel 0 | 0.43
391786 | Nivel 0 | 0.9
391787 | Nivel 0 | 2.77843
391812 | Nivel 0 | 0.975
391819 | Nivel 0 | 0.975
392240 | Nivel 0 | 1.175
392241 | Nivel 0 | 1.43
392297 | Nivel 0 | 1.15
392298 | Nivel 0 | 1.33674
392439 | Nivel 0 | 0.975
392570 | Nivel 0 | 0.5875
392571 | Nivel 0 | 0.5875
392572 | Nivel 0 | 0.5875
392573 | Nivel 0 | 0.5875
392574 | Nivel 0 | 0.5875
392575 | Nivel 0 | 0.5875
392655 | Nivel 0 | 0.919828
392656 | Nivel 0 | 1.43
392657 | Nivel 0 | 0.38
392729 | Nivel 0 | 0.2
392730 | Nivel 0 | 0.2
392731 | Nivel 0 | 0.2
392732 | Nivel 0 | 0.2
392733 | Nivel 0 | 0.2
392734 | Nivel 0 | 0.2
392817 | Nivel 0 | 1.15
392831 | Nivel 0 | 0.225
392832 | Nivel 0 | 0.5875
392931 | Nivel 0 | 1.31174
393513 | Nivel 0 | 0.5875
393514 | Nivel 0 | 0.5875
393515 | Nivel 0 | 0.5875
393516 | Nivel 0 | 0.5875
393517 | Nivel 0 | 0.5875
393518 | Nivel 0 | 0.5875
393519 | Nivel 0 | 0.5875
393602 | Nivel 0 | 1.43
404734 | Nivel 1 | 1.89
404735 | Nivel 1 | 0.9
404736 | Nivel 1 | 0.825
404737 | Nivel 1 | 1.84
404739 | Nivel 1 | 2.3
404745 | Nivel 1 | 2.3
404746 | Nivel 1 | 0.05
404747 | Nivel 1 | 2.3
404871 | Nivel 1 | 2.3
404876 | Nivel 1 | 0.825
405748 | Nivel 1 | 0.825
405677 | Nivel 1 | 0.2
405679 | Nivel 1 | 0.835
405680 | Nivel 1 | 2.04116
405681 | Nivel 1 | 2.04116
405682 | Nivel 1 | 0.72884
405683 | Nivel 1 | 2.04116
405684 | Nivel 1 | 0.81
405685 | Nivel 1 | 0.2
405686 | Nivel 1 | 1.25
405733 | Nivel 1 | 2.06616
405734 | Nivel 1 | 0.72884
405735 | Nivel 1 | 0.07
631976 | Nivel 1 | 1.25
631982 | Nivel 1 | 0.75384
631983 | Nivel 1 | 2.06616
631984 | Nivel 1 | 0.14616
632012 | Nivel 1 | 0.2
632013 | Nivel 1 | 1.25
632014 | Nivel 1 | 0.81
632015 | Nivel 1 | 0.07
632022 | Nivel 1 | 0.72884
632023 | Nivel 1 | 0.0961604
405717 | Nivel 1 | 2.15616
405718 | Nivel 1 | 2.15616
405719 | Nivel 1 | 0.2
405720 | Nivel 1 | 1.32
405721 | Nivel 1 | 0.835
405722 | Nivel 1 | 2.15616
405724 | Nivel 1 | 0.77884
405726 | Nivel 1 | 0.835
405727 | Nivel 1 | 0.2
405730 | Nivel 1 | 0.2
405731 | Nivel 1 | 1.32
405732 | Nivel 1 | 0.835
535826 | Nivel 1 | 2.15616
632029 | Nivel 1 | 0.77884
632034 | Nivel 1 | 0.77884
632039 | Nivel 1 | 1.32
632070 | Nivel 1 | 0.77884
405758 | Nivel 1 | 2.3
405759 | Nivel 1 | 1.675
405760 | Nivel 1 | 0.9
405761 | Nivel 1 | 0.825
405762 | Nivel 1 | 1.625
405763 | Nivel 1 | 0.875
405764 | Nivel 1 | 2.3
405771 | Nivel 1 | 2.3
405772 | Nivel 1 | 0.05
405884 | Nivel 1 | 2.3
535157 | Nivel 1 | 0.825
405806 | Nivel 1 | 0.2
405809 | Nivel 1 | 2.04616
405810 | Nivel 1 | 2.04616
405811 | Nivel 1 | 0.825
405812 | Nivel 1 | 2.04616
405813 | Nivel 1 | 0.81
405814 | Nivel 1 | 0.2
405815 | Nivel 1 | 1.25
405862 | Nivel 1 | 2.07116
405876 | Nivel 1 | 0.825
535213 | Nivel 1 | 0.2
535214 | Nivel 1 | 1.25
535215 | Nivel 1 | 0.835
535216 | Nivel 1 | 0.07
535236 | Nivel 1 | 1.25
535237 | Nivel 1 | 0.835
405845 | Nivel 1 | 0.175
405846 | Nivel 1 | 1.93
405847 | Nivel 1 | 1.88
405848 | Nivel 1 | 0.2
405849 | Nivel 1 | 1.25
405850 | Nivel 1 | 0.835
405851 | Nivel 1 | 1.88
405852 | Nivel 1 | 0.91
405853 | Nivel 1 | 0.935
405854 | Nivel 1 | 1.905
405855 | Nivel 1 | 0.81
405856 | Nivel 1 | 0.2
405857 | Nivel 1 | 1.25
405859 | Nivel 1 | 0.2
405860 | Nivel 1 | 1.25
405861 | Nivel 1 | 0.81
405865 | Nivel 1 | 0.2
405866 | Nivel 1 | 1.25
405867 | Nivel 1 | 0.07
405868 | Nivel 1 | 0.835
405869 | Nivel 1 | 1.225
405870 | Nivel 1 | 0.07
405871 | Nivel 1 | 0.835
405881 | Nivel 1 | 0.91
405882 | Nivel 1 | 0.91
405891 | Nivel 1 | 1.89
405892 | Nivel 1 | 0.9
405893 | Nivel 1 | 0.825
405894 | Nivel 1 | 1.84
405895 | Nivel 1 | 2.3
405900 | Nivel 1 | 2.3
405901 | Nivel 1 | 0.05
405902 | Nivel 1 | 2.3
405903 | Nivel 1 | 2.3
405904 | Nivel 1 | 0.825
408800 | Nivel 1 | 1.875
408803 | Nivel 1 | 1.35
408892 | Nivel 1 | 1
408941 | Nivel 1 | 1.875
409040 | Nivel 1 | 0.95
409264 | Nivel 1 | 0.95
409266 | Nivel 1 | 1.875
409401 | Nivel 1 | 1.35
409402 | Nivel 1 | 1
409423 | Nivel 1 | 1.35
409424 | Nivel 1 | 1
408782 | Nivel 1 | 1.35
408785 | Nivel 1 | 2.55
408789 | Nivel 1 | 2.55
408793 | Nivel 1 | 1
408831 | Nivel 1 | 1
408832 | Nivel 1 | 1.35
408934 | Nivel 1 | 2.55
408797 | Nivel 1 | 1.95115
409141 | Nivel 1 | 0.95
409346 | Nivel 1 | 0.95
409347 | Nivel 1 | 1.95115
409348 | Nivel 1 | 1.95115
409413 | Nivel 1 | 1.35
409414 | Nivel 1 | 1
409435 | Nivel 1 | 1.35
409436 | Nivel 1 | 1
512000 | Nivel 0 | 0.100973
512001 | Nivel 0 | 2.52648
512006 | Nivel 0 | 0.825
512695 | Nivel 0 | 2.15
512697 | Nivel 0 | 0.825
512770 | Nivel 0 | 2.15
512771 | Nivel 0 | 0.85
512803 | Nivel 0 | 2.52648
512804 | Nivel 0 | 0.100973
512811 | Nivel 0 | 2.52648
512812 | Nivel 0 | 0.100973
513381 | Nivel 0 | 0.85
513382 | Nivel 0 | 0.1
513411 | Nivel 0 | 2.52648
513412 | Nivel 0 | 0.100973
513802 | Nivel 0 | 0.1
513803 | Nivel 0 | 0.85
513899 | Nivel 0 | 2.52648
513900 | Nivel 0 | 0.100973
513948 | Nivel 0 | 0.85
513949 | Nivel 0 | 1.84
513992 | Nivel 0 | 2.52648
513993 | Nivel 0 | 0.100973
514077 | Nivel 0 | 0.85
514179 | Nivel 0 | 2.52648
514180 | Nivel 0 | 0.100973
514221 | Nivel 0 | 0.85
514223 | Nivel 0 | 1.84
514260 | Nivel 0 | 2.52648
514261 | Nivel 0 | 0.100973
517977 | Nivel 0 | 0.155
518135 | Nivel 0 | 0.865
518179 | Nivel 0 | 0.7
518291 | Nivel 0 | 1.49
518370 | Nivel 0 | 0.2
518409 | Nivel 0 | 0.155
518418 | Nivel 0 | 0.155
518083 | Nivel 0 | 2.15
518626 | Nivel 0 | 2.15
518630 | Nivel 0 | 2.15
518086 | Nivel 0 | 0.805
518249 | Nivel 0 | 0.7
518548 | Nivel 0 | 1.49
518607 | Nivel 0 | 0.2
518633 | Nivel 0 | 0.805
518637 | Nivel 0 | 0.805
518938 | Nivel 0 | 0.055
518973 | Nivel 0 | 0.745
519021 | Nivel 0 | 2.39
518941 | Nivel 0 | 1.84
519518 | Nivel 0 | 1.84
519528 | Nivel 0 | 1.84
518944 | Nivel 0 | 0.85
519522 | Nivel 0 | 0.85
519525 | Nivel 0 | 0.85
516075 | Nivel 0 | 0.100973
516076 | Nivel 0 | 2.33903
516086 | Nivel 0 | 1.07
516091 | Nivel 0 | 2.15
516094 | Nivel 0 | 2.33903
516095 | Nivel 0 | 0.100973
516096 | Nivel 0 | 2.33903
516097 | Nivel 0 | 0.100973
516102 | Nivel 0 | 0.85
516103 | Nivel 0 | 0.1
516105 | Nivel 0 | 2.33903
516106 | Nivel 0 | 0.100973
516111 | Nivel 0 | 0.1
516114 | Nivel 0 | 2.33903
516115 | Nivel 0 | 0.100973
516120 | Nivel 0 | 0.85
516123 | Nivel 0 | 2.33903
516124 | Nivel 0 | 0.100973
516128 | Nivel 0 | 0.85
516129 | Nivel 0 | 2.33903
516130 | Nivel 0 | 0.100973
516137 | Nivel 0 | 1.84
516138 | Nivel 0 | 2.33903
516139 | Nivel 0 | 0.100973
516327 | Nivel 0 | 0.825
516379 | Nivel 0 | 0.85
516456 | Nivel 0 | 2.33903
516457 | Nivel 0 | 0.100973
516468 | Nivel 0 | 2.33903
516469 | Nivel 0 | 0.100973
516501 | Nivel 0 | 1.94919
516530 | Nivel 0 | 2.33903
516531 | Nivel 0 | 0.100973
532073 | Nivel 0 | 1.71372
532077 | Nivel 0 | 1.71372
532080 | Nivel 0 | 1.71372
532083 | Nivel 0 | 1.4576
532084 | Nivel 0 | 0.2
532085 | Nivel 0 | 0.9
532093 | Nivel 0 | 0.2
532094 | Nivel 0 | 0.9
532095 | Nivel 0 | 1.4576
532104 | Nivel 0 | 1.71372
532415 | Nivel 0 | 1.47903
532416 | Nivel 0 | 0.2
532417 | Nivel 0 | 0.9
532422 | Nivel 0 | 1.47903
532423 | Nivel 0 | 0.2
532424 | Nivel 0 | 0.9
532432 | Nivel 0 | 1.47903
532433 | Nivel 0 | 0.2
532434 | Nivel 0 | 0.9
532459 | Nivel 0 | 2.7808
532460 | Nivel 0 | 0.825
532469 | Nivel 0 | 2.7808
532470 | Nivel 0 | 0.825
532477 | Nivel 0 | 2.7808
532478 | Nivel 0 | 0.825
532479 | Nivel 0 | 0.825
532485 | Nivel 0 | 0.2
532486 | Nivel 0 | 0.9
532487 | Nivel 0 | 1.47903
532491 | Nivel 0 | 0.825
532492 | Nivel 0 | 2.7808
532493 | Nivel 0 | 0.825
589510 | Nivel 1 | 0.3
589513 | Nivel 1 | 1.01822
589517 | Nivel 1 | 1.01071
589521 | Nivel 1 | 1.01822
589578 | Nivel 1 | 1.04322
589579 | Nivel 1 | 1.04322
589620 | Nivel 1 | 1.04322
589621 | Nivel 1 | 1.01822
589675 | Nivel 1 | 1.04322
589676 | Nivel 1 | 1.01822
589717 | Nivel 1 | 1.01071
589718 | Nivel 1 | 0.3
589763 | Nivel 1 | 1.04322
589764 | Nivel 1 | 1.01822
589765 | Nivel 1 | 1.04322
589766 | Nivel 1 | 1.01822
589778 | Nivel 1 | 0.3
589779 | Nivel 1 | 1.01071
589792 | Nivel 1 | 0.3
589793 | Nivel 1 | 1.01071
589797 | Nivel 1 | 0.3
589798 | Nivel 1 | 1.01071
589847 | Nivel 1 | 0.259285
589848 | Nivel 1 | 1.13687
589849 | Nivel 1 | 1.01071
589850 | Nivel 1 | 1.01822
589853 | Nivel 1 | 1.04322
589854 | Nivel 1 | 1.04322
589857 | Nivel 1 | 1.04322
589858 | Nivel 1 | 1.01822
589861 | Nivel 1 | 1.04322
589862 | Nivel 1 | 1.13687
589868 | Nivel 1 | 1.01071
589869 | Nivel 1 | 0.259285
589870 | Nivel 1 | 1.04322
589871 | Nivel 1 | 1.01822
589872 | Nivel 1 | 1.04322
589873 | Nivel 1 | 1.13687
589874 | Nivel 1 | 0.259285
589875 | Nivel 1 | 1.01071
589876 | Nivel 1 | 0.259285
589877 | Nivel 1 | 1.01071
589878 | Nivel 1 | 0.259285
589879 | Nivel 1 | 1.01071

# IfcOpeningElement (203)
PredefinedType: OPENING
Name | In | Reference | sets with these values
5 x Muro básico:Por defecto - 40 cm 2:183592 | Nivel 0 | Por defecto - 40 cm 2 | 2
Muro básico:Por defecto - 40 cm 2:183592 | Nivel 0 | 80 x 210 cm | 2
Muro básico:Por defecto - 40 cm 2:183475 | Nivel 0 | Por defecto - 40 cm 2 | 2
5 x Muro básico:Por defecto - 40 cm 2:184475 | Nivel -1 | Por defecto - 40 cm 2 | 2
Muro básico:Por defecto - 40 cm 2:184475 | Nivel -1 | 90 x 210 cm | 2
Muro básico:Por defecto - 40 cm 2:183475 | Nivel -1 | Por defecto - 40 cm 2 | 2
2 x Muro básico:Por defecto - 25 cm 2:184832 | Nivel 0 | Por defecto - 25 cm 2 | 2
2 x Muro básico:Por defecto - 30 cm:184906 | Nivel 0 | Por defecto - 30 cm | 2
2 x Muro básico:Por defecto - 25 cm 2:185040 | Nivel 0 | Por defecto - 25 cm 2 | 2
Muro básico:Por defecto - 25 cm 2:185120 | Nivel 0 | Por defecto - 25 cm 2 | 2
2 x Muro básico:Por defecto - 25 cm 2:185200 | Nivel 0 | Por defecto - 25 cm 2 | 2
Muro básico:Por defecto - 18 cm 2:186199 | Nivel 0 | Por defecto - 18 cm 2 | 2
61 x Muro básico:Por defecto - 18 cm 2:186643 | Nivel 0 | Por defecto - 18 cm 2 | 2
Muro básico:Por defecto - 18 cm 2:186491:1 | Nivel 0 | Por defecto - 18 cm 2 | 2
Muro básico:Por defecto - 18 cm 2:186491 | Nivel 0 | Por defecto - 18 cm 2 | 2
Muro básico:Por defecto - 18 cm 2:186764 | Nivel 0 | Por defecto - 18 cm 2 | 2
Muro básico:Por defecto - 25 cm 2:184778 | Nivel 0 | Por defecto - 25 cm 2 | 2
2 x Muro básico:Por defecto - 30 cm:219780 | Nivel 0 | Por defecto - 30 cm | 2
Muro básico:Por defecto - 30 cm:16251 | Nivel 0 | Por defecto - 30 cm | 2
4 x Muro básico:Por defecto - 10 cm:231013 | Nivel 0 | Por defecto - 10 cm | 2
3 x Muro básico:Por defecto - 10 cm:231345 | Nivel 0 | Por defecto - 10 cm | 2
Muro básico:Por defecto - 25 cm 2:253016 | Nivel 0 | Por defecto - 25 cm 2 | 2
Muro básico:Por defecto - 18 cm 2:253451 | Nivel 0 | Por defecto - 18 cm 2 | 2
4 x Muro básico:Por defecto - 18 cm 2:268105 | Nivel 0 | Por defecto - 18 cm 2 | 2
2 x Muro básico:Por defecto - 30 cm:271633 | Nivel 0 | Por defecto - 30 cm | 2
2 x Muro básico:Por defecto - 25 cm 2:272692 | Nivel 0 | Por defecto - 25 cm 2 | 2
Muro básico:Por defecto - 30 cm:282441 | Nivel 0 | Por defecto - 30 cm | 2
Muro básico:Por defecto - 30 cm:282785 | Nivel 0 | 60 x 1.15mm 2 | 2
3 x Muro básico:Por defecto - 10 cm:285087 | Nivel 0 | Por defecto - 10 cm | 2
Muro básico:Por defecto - 18 cm 2:327384 | Nivel 0 | Por defecto - 18 cm 2 | 2
Muro básico:Por defecto - 22 cm 2:342739 | Nivel 1 | Por defecto - 22 cm 2 | 2
Muro básico:Por defecto - 22 cm 2:350361 | Nivel 1 | Por defecto - 22 cm 2 | 2
Muro básico:Por defecto - 25 cm 2:351531 | Nivel 0 | Por defecto - 25 cm 2 | 2
Muro básico:Por defecto - 10 cm:384465 | Nivel 0 | Por defecto - 10 cm | 2
Muro básico:Por defecto - 10 cm:406418:1 | Nivel 1 | Por defecto - 10 cm | 2
Muro básico:Por defecto - 15 cm 2:410502 | Nivel 1 | Por defecto - 15 cm 2 | 2
Muro básico:Por defecto - 15 cm 2:417665 | Nivel 1 | 80 x 210 cm | 2
Muro básico:Por defecto - 36 cm 2:418173:1 | Nivel 1 | Por defecto - 36 cm 2 | 2
Muro básico:Por defecto - 36 cm 2:418173 | Nivel 1 | Por defecto - 36 cm 2 | 2
Muro básico:Por defecto - 36 cm 2:418411 | Nivel 1 | Por defecto - 36 cm 2 | 2
Muro básico:Por defecto - 36 cm 2:418411 | Nivel 1 | 116 x 210 cm 2 | 2
Muro básico:Por defecto - 15 cm 2:419558 | Nivel 1 | 85 x 210 cm 2 | 2
Muro básico:Por defecto - 36 cm 2:422187 | Nivel 1 | Por defecto - 36 cm 2 | 2
Muro básico:Por defecto - 36 cm 2:422187 | Nivel 1 | 1200 x 2100 mm 2 | 2
3 x Muro básico:Por defecto - 10 cm:559397 | Nivel 1 | Por defecto - 10 cm | 2
Muro básico:Por defecto - 15 cm 2:590990 | Nivel 1 | 83 x 210 cm 3 | 2
Muro básico:Por defecto - 15 cm 2:591698 | Nivel 1 | 85 x 210 cm 2 | 2
Muro básico:Por defecto - 30 cm:601536 | Nivel 0 | Por defecto - 30 cm | 2
4 x Muro básico:Por defecto - 10 cm:625969 | Nivel 0 | Por defecto - 10 cm | 2
2 x Muro básico:Por defecto - 40 cm 2:629450 | Nivel 0 | Por defecto - 40 cm 2 | 2
Puerta de 1 hoja:80 x 210 cm:230418:1 | Nivel 0
Ventana de guillotina de 2 hojas:1300x 1600mm 3:635270:1 | Nivel 0
Ventana de guillotina de 2 hojas:1200x 1600mm 2:488622:1 | Nivel -1
Puerta de 1 hoja:90 x 210 cm:223377:1 | Nivel 0
Puerta de 1 hoja:80 x 210 cm:186584:1 | Nivel 0
Puerta corredera simple con guía deslizante:1330 x 2100mm 2:195537:1 | Nivel 0
Puerta de 1 hoja:80 x 210 cm:628626:1 | Nivel 0
Puerta de 1 hoja:90 x 210 cm:226842:1 | Nivel 0
Puerta de 1 hoja:80 x 210 cm:230466:1 | Nivel 0
Puerta de 1 hoja:90 x 210 cm:230336:1 | Nivel 0
Puerta de 1 hoja:85 x 210 cm 2:626503:1 | Nivel 0
Puerta de 1 hoja:90 x 210 cm:281908:1 | Nivel 0
Puerta de 1 hoja:80 x 210 cm:284672:1 | Nivel 0
Ventana simple fija con cubrejuntas interior:0.6 x 2.05mm 2:576744:1 | Nivel 0
Deflector de ventilación simple:60 x 1.15mm 2:576743:1 | Nivel 0
Deflector de ventilación simple:60 x 1.15mm 2:576742:1 | Nivel 0
Puerta de 1 hoja:88 x 210 cm 3:536665:1 | Nivel 1
Ventana simple:109 x 100 cm 2:412077:1 | Nivel 1
Puerta de 1 hoja:85 x 210 cm 2:552133:1 | Nivel 1
Ventana basculante:35 x 60mm 3:565564:1 | Nivel 1
Ventana basculante:35 x 60mm 3:565604:1 | Nivel 1
Ventana basculante:35 x 60mm 3:565644:1 | Nivel 1
Puerta de 1 hoja:80 x 210 cm:549885:1 | Nivel 1
Puerta de 1 hoja:80 x 210 cm:485675:1 | Nivel 1
Puerta de 1 hoja:83 x 210 cm 3:485802:1 | Nivel 1
Puerta de 1 hoja:120 x 210 cm 3:485995:1 | Nivel 1
Ventana simple fija con cubrejuntas interior:1.15 x 1.20mm 2:612186:1 | Nivel 1
Puerta atamborada de 2 hojas:1200 x 2100 mm 2:419465:1 | Nivel 1
Puerta atamborada de 2 hojas:1200 x 2100 mm 2:419806:1 | Nivel 1
Puerta atamborada de 2 hojas:1200 x 2100 mm 2:419989:1 | Nivel 1
Puerta atamborada de 2 hojas:1200 x 2100 mm 2:632473:1 | Nivel 1
Ventana corredera de 2 hojas 2:1850 x 1300mm 2:551987:1 | Nivel 1
Ventana basculante:35 x 70mm 2:558207:1 | Nivel 1
Puerta de 1 hoja:85 x 210 cm 2:628042:1 | Nivel 1
Puerta de 1 hoja:116 x 210 cm 2:424842:1 | Nivel 1
Puerta de 1 hoja:85 x 210 cm 2:425604:1 | Nivel 1
Ventana de guillotina de 2 hojas:1500x 1600mm 4:489988:1 | Nivel 1
Ventana de guillotina de 2 hojas:1300x 1600mm 3:490493:1 | Nivel 1
Ventana de guillotina de 2 hojas:1300x 1600mm 3:491821:1 | Nivel 1
Ventana de guillotina de 2 hojas:1300x 1600mm 3:492054:1 | Nivel 1
Ventana de guillotina de 2 hojas:1500x 1600mm 4:492147:1 | Nivel 1
Ventana de guillotina de 2 hojas:1300x 1600mm 3:492250:1 | Nivel 1
Ventana de guillotina de 2 hojas:1300x 1600mm 3:498402:1 | Nivel 1
Ventana de guillotina de 2 hojas:1500x 1600mm 4:498488:1 | Nivel 1
Puerta de 1 hoja:85 x 210 cm 2:550014:1 | Nivel 1
Puerta de 1 hoja:70 x 210 cm:487238:1 | Nivel 1
Puerta de 1 hoja:83 x 210 cm 3:487307:1 | Nivel 1
Puerta de 1 hoja:83 x 210 cm 3:487385:1 | Nivel 1
Puerta de 1 hoja:70 x 210 cm:487425:1 | Nivel 1
Puerta de 1 hoja:85 x 210 cm 2:487824:1 | Nivel 1
Ventana corredera de 2 hojas 2:1600 x 1600mm:541523:1 | Nivel 1
Deflector de ventilación simple:60 x 1.15mm 2:573069:1 | Nivel 0
Deflector de ventilación simple:60 x 1.15mm 2:573105:1 | Nivel 0
Ventana simple fija con cubrejuntas interior:0.6 x 2.05mm 2:576462:1 | Nivel 0
Ventana simple fija con cubrejuntas interior:1900x 1200mm 2:596153:1 | Nivel 1
Ventana simple fija con cubrejuntas interior:1900x 1200mm 2:596059:1 | Nivel 1
Ventana simple fija con cubrejuntas interior:1900x 1200mm 2:592107:1 | Nivel 1
Ventana basculante:45 x 100mm 4:591360:1 | Nivel 1
Puerta de 1 hoja:85 x 210 cm 2:626463:1 | Nivel 0
Puerta de 1 hoja:85 x 210 cm 2:630606:1 | Nivel 0
Puerta de 1 hoja:120 x 210 cm 3:632139:1 | Nivel 1
Puerta de 1 hoja:90 x 210 cm:632253:1 | Nivel 1

# IfcPlate: Panel de sistema:Acristalado (323)
Type - PredefinedType: CURTAIN_PANEL; Material: Cristal
Type - Pset_PlateCommon - IsExternal: no; ThermalTransmittance: 6.7069 kg/K/s3
Pset_EnvironmentalImpactIndicators - Reference: Acristalado
Pset_PlateCommon - Reference: Acristalado
Name (Panel de sistema:Acristalado:...) | In
206559 | Nivel 0
206776 | Nivel 0
208347 | Nivel 0
211067 | Nivel 0
212560 | Nivel 0
213065 | Nivel 0
212707 | Nivel 0
213370 | Nivel 0
213498 | Nivel 0
212718 | Nivel 0
213233 | Nivel 0
219529 | Nivel 0
219534 | Nivel 0
219885 | Nivel 0
219901 | Nivel 0
219888 | Nivel 0
219892 | Nivel 0
220761 | Nivel 0
221259 | Nivel 0
220822 | Nivel 0
233195 | Nivel 0
240172 | Nivel 0
310098 | Nivel 0
310212 | Nivel 0
310297 | Nivel 0
310298 | Nivel 0
310299 | Nivel 0
249433 | Nivel 0
250159 | Nivel 0
250666 | Nivel 0
251787 | Nivel 0
252099 | Nivel 0
252037 | Nivel 0
252333 | Nivel 0
252721 | Nivel 0
252875 | Nivel 0
252597 | Nivel 0
252723 | Nivel 0
268532 | Nivel 0
268910 | Nivel 0
269513 | Nivel 0
269514 | Nivel 0
270714 | Nivel 0
270170 | Nivel 0
270429 | Nivel 0
270660 | Nivel 0
270559 | Nivel 0
270561 | Nivel 0
271017 | Nivel 0
271019 | Nivel 0
272079 | Nivel 0
271865 | Nivel 0
271878 | Nivel 0
274170 | Nivel 0
274354 | Nivel 0
274559 | Nivel 0
274439 | Nivel 0
274440 | Nivel 0
274441 | Nivel 0
275533 | Nivel 0
275535 | Nivel 0
275537 | Nivel 0
275552 | Nivel 0
275543 | Nivel 0
275545 | Nivel 0
275622 | Nivel 0
275626 | Nivel 0
275641 | Nivel 0
275632 | Nivel 0
275634 | Nivel 0
275669 | Nivel 0
275673 | Nivel 0
275688 | Nivel 0
275679 | Nivel 0
275681 | Nivel 0
275810 | Nivel 0
276104 | Nivel 0
279039 | Nivel 0
276266 | Nivel 0
276268 | Nivel 0
277204 | Nivel 0
277239 | Nivel 0
277253 | Nivel 0
277210 | Nivel 0
278220 | Nivel 0
278483 | Nivel 0
278574 | Nivel 0
278812 | Nivel 0
278890 | Nivel 0
278891 | Nivel 0
278418 | Nivel 0
278484 | Nivel 0
280600 | Nivel 0
280736 | Nivel 0
280856 | Nivel 0
280860 | Nivel 0
280862 | Nivel 0
281094 | Nivel 0
280864 | Nivel 0
280874 | Nivel 0
280875 | Nivel 0
280876 | Nivel 0
280866 | Nivel 0
280868 | Nivel 0
288783 | Nivel 0
289393 | Nivel 0
289041 | Nivel 0
289342 | Nivel 0
289980 | Nivel 0
289982 | Nivel 0
289994 | Nivel 0
289988 | Nivel 0
293312 | Nivel 0
293313 | Nivel 0
293595 | Nivel 0
293524 | Nivel 0
293597 | Nivel 0
293526 | Nivel 0
308049 | Nivel 0
510342 | Nivel 0
308603 | Nivel 0
308053 | Nivel 0
308057 | Nivel 0
432429 | Nivel 0
308132 | Nivel 0
308144 | Nivel 0
308138 | Nivel 0
432430 | Nivel 0
432431 | Nivel 0
310835 | Nivel 0
310871 | Nivel 0
310872 | Nivel 0
310839 | Nivel 0
310843 | Nivel 0
325445 | Nivel 0
325805 | Nivel 0
325859 | Nivel 0
326232 | Nivel 0
326118 | Nivel 0
326120 | Nivel 0
326121 | Nivel 0
325982 | Nivel 0
325984 | Nivel 0
328565 | Nivel 0
329055 | Nivel 0
329056 | Nivel 0
328929 | Nivel 0
328998 | Nivel 0
352710 | Nivel 1
353828 | Nivel 1
353793 | Nivel 1
354596 | Nivel 1
354526 | Nivel 1
354641 | Nivel 1
354642 | Nivel 1
354643 | Nivel 1
353756 | Nivel 1
353830 | Nivel 1
355700 | Nivel 1
356004 | Nivel 1
356049 | Nivel 1
356165 | Nivel 1
356098 | Nivel 1
356210 | Nivel 1
356211 | Nivel 1
356212 | Nivel 1
355906 | Nivel 1
356006 | Nivel 1
357076 | Nivel 1
357332 | Nivel 1
357432 | Nivel 1
357491 | Nivel 1
357379 | Nivel 1
357380 | Nivel 1
357721 | Nivel 1
357881 | Nivel 1
358045 | Nivel 1
358127 | Nivel 1
357987 | Nivel 1
358404 | Nivel 1
358699 | Nivel 1
358756 | Nivel 1
358828 | Nivel 1
358829 | Nivel 1
362693 | Nivel 1
362696 | Nivel 1
362705 | Nivel 1
362816 | Nivel 1
362709 | Nivel 1
362719 | Nivel 1
362700 | Nivel 1
362701 | Nivel 1
362738 | Nivel 1
362753 | Nivel 1
362758 | Nivel 1
363298 | Nivel 1
363333 | Nivel 1
364208 | Nivel 1
364209 | Nivel 1
366586 | Nivel 1
366589 | Nivel 1
366598 | Nivel 1
366684 | Nivel 1
366602 | Nivel 1
366612 | Nivel 1
366593 | Nivel 1
366594 | Nivel 1
366629 | Nivel 1
366706 | Nivel 1
366644 | Nivel 1
366648 | Nivel 1
366649 | Nivel 1
386039 | Nivel 0
389363 | Nivel 0
389364 | Nivel 0
389365 | Nivel 0
389431 | Nivel 0
389432 | Nivel 0
389499 | Nivel 0
389536 | Nivel 0
389537 | Nivel 0
389538 | Nivel 0
390943 | Nivel 0
391780 | Nivel 0
391229 | Nivel 0
392233 | Nivel 0
391673 | Nivel 0
391652 | Nivel 0
391523 | Nivel 0
392703 | Nivel 0
392704 | Nivel 0
392534 | Nivel 0
392542 | Nivel 0
393477 | Nivel 0
404726 | Nivel 1
404730 | Nivel 1
404741 | Nivel 1
405646 | Nivel 1
405658 | Nivel 1
405744 | Nivel 1
405662 | Nivel 1
405672 | Nivel 1
405653 | Nivel 1
405654 | Nivel 1
405655 | Nivel 1
405691 | Nivel 1
405704 | Nivel 1
405707 | Nivel 1
405709 | Nivel 1
405753 | Nivel 1
405755 | Nivel 1
405767 | Nivel 1
405768 | Nivel 1
405775 | Nivel 1
405787 | Nivel 1
405873 | Nivel 1
405791 | Nivel 1
405801 | Nivel 1
405782 | Nivel 1
405783 | Nivel 1
405818 | Nivel 1
405824 | Nivel 1
405880 | Nivel 1
405833 | Nivel 1
405837 | Nivel 1
405838 | Nivel 1
405830 | Nivel 1
405886 | Nivel 1
405888 | Nivel 1
405897 | Nivel 1
408321 | Nivel 1
408887 | Nivel 1
408455 | Nivel 1
408823 | Nivel 1
409336 | Nivel 1
409337 | Nivel 1
514067 | Nivel 0
511953 | Nivel 0
512685 | Nivel 0
512760 | Nivel 0
513373 | Nivel 0
513793 | Nivel 0
513940 | Nivel 0
514212 | Nivel 0
514068 | Nivel 0
516928 | Nivel 0
517894 | Nivel 0
517963 | Nivel 0
518131 | Nivel 0
518362 | Nivel 0
518284 | Nivel 0
518040 | Nivel 0
518452 | Nivel 0
518082 | Nivel 0
518542 | Nivel 0
518875 | Nivel 0
518917 | Nivel 0
519082 | Nivel 0
518927 | Nivel 0
519476 | Nivel 0
516100 | Nivel 0
530914 | Nivel 0
532050 | Nivel 0
532305 | Nivel 0
532258 | Nivel 0
532383 | Nivel 0
532384 | Nivel 0
589381 | Nivel 1
589668 | Nivel 1
589572 | Nivel 1
589613 | Nivel 1
589705 | Nivel 1
589706 | Nivel 1
589707 | Nivel 1
589708 | Nivel 1
589846 | Nivel 1
589860 | Nivel 1
589852 | Nivel 1
589856 | Nivel 1
589864 | Nivel 1
589865 | Nivel 1
589866 | Nivel 1
589867 | Nivel 1

# IfcRailing: Barandilla:Barrotes redondos (4)
In: Nivel 0
Material: Acero
Pset_EnvironmentalImpactIndicators - Reference: Barrotes redondos
Pset_RailingCommon - IsExternal: no; Reference: Barrotes redondos; Height: 0.9 m
Name (Barandilla:Barrotes redondos:...)
545007
545011
547803
547807

# IfcRailing: Barandilla:Montantes Horizontales (2)
In: Nivel 0
Material: Acero, Madera - Listel
Pset_EnvironmentalImpactIndicators - Reference: Montantes Horizontales
Pset_RailingCommon - IsExternal: no; Reference: Montantes Horizontales; Height: 0.9 m
Name (Barandilla:Montantes Horizontales:...)
628869
629095

# IfcRamp: Rampa:1.73 20% 2 (2)
In: Nivel -1
Pset_EnvironmentalImpactIndicators - Reference: 1.73 20% 2; sets with these values: 2
Pset_RampCommon - IsExternal: no; Reference: 1.73 20% 2
Name (Rampa:1.73 20% 2:...)
176928
181689

# IfcRamp: Rampa:Coches 20% (6)
In: Nivel -1
Pset_EnvironmentalImpactIndicators - Reference: Coches 20%; sets with these values: 2
Pset_RampCommon - IsExternal: no; Reference: Coches 20%
Name (Rampa:Coches 20%:...)
176575
177090
301956
302081
303218
582486

# IfcRampFlight: Rampa:1.73 20% 2 (2)
In: Nivel -1
Material: Asfalto, betún
Pset_EnvironmentalImpactIndicators - Reference: 1.73 20% 2; sets with these values: 2
Name (Rampa:1.73 20% 2:...)
176928:1
181689:1

# IfcRampFlight: Rampa:Coches 20% (6)
In: Nivel -1
Material: Asfalto, betún
Pset_EnvironmentalImpactIndicators - Reference: Coches 20%; sets with these values: 2
Name (Rampa:Coches 20%:...)
176575:1
177090:1
301956:1
302081:1
303218:1
582486:1

# IfcRoof: Cubierta básica:Cubierta - chapa- 0.05 cm 2, Cubierta básica:Cubierta - chapa- 0.05 cm 2:608178
In: Nivel 2
Type - Pset_RoofCommon - IsExternal: yes
Material: Cubierta por defecto
Pset_EnvironmentalImpactIndicators - Reference: Cubierta - chapa- 0.05 cm 2
Pset_RoofCommon - Reference: Cubierta - chapa- 0.05 cm 2

# IfcRoof: Cubierta básica:Pizarra sobre rastreles - 15 cm (2)
In: Nivel 2
Type - Pset_RoofCommon - IsExternal: yes
Material: Piedra - pizarra, Madera - Listel (2), Aislamiento térmico
Pset_EnvironmentalImpactIndicators - Reference: Pizarra sobre rastreles - 15 cm
Pset_RoofCommon - Reference: Pizarra sobre rastreles - 15 cm
Name (Cubierta básica:Pizarra sobre rastreles - 15 cm:...)
563063
570110

# IfcRoof: Cubierta básica:Plana tipo deck - 16 cm (2)
In: Nivel 1
Pset_EnvironmentalImpactIndicators - Reference: Plana tipo deck - 16 cm
Pset_RoofCommon - IsExternal: yes; Reference: Plana tipo deck - 16 cm
Name (Cubierta básica:Plana tipo deck - 16 cm:...)
508018
509383

# IfcRoof: Cubierta básica:Plana tipo deck - 16 cm, Cubierta básica:Plana tipo deck - 16 cm:506820
In: Nivel 2
Type - Pset_RoofCommon - IsExternal: yes
Material: Aislamiento térmico, Metal - Chapado (1)
Pset_EnvironmentalImpactIndicators - Reference: Plana tipo deck - 16 cm
Pset_RoofCommon - Reference: Plana tipo deck - 16 cm

# IfcRoof: Cubierta básica:Plana tradicional transitable - 30 cm 2 (13)
Pset_EnvironmentalImpactIndicators - Reference: Plana tradicional transitable - 30 cm 2
Pset_RoofCommon - IsExternal: yes; Reference: Plana tradicional transitable - 30 cm 2
Name (Cubierta básica:Plana tradicional transitable - 30 cm 2:...) | In
339801 | Nivel 0
340613 | Nivel 0
340883 | Nivel 0
341121 | Nivel 0
343434 | Nivel 1
343541 | Nivel 0
344028 | Nivel 1
345366 | Nivel 2
348709 | Nivel 1
348753 | Nivel 0
349230 | Nivel 2
349455 | Nivel 2
591938 | Nivel 2

# IfcSlab: Cubierta básica:Plana tipo deck - 16 cm (6)
In: Nivel 1
Type - PredefinedType: ROOF
Type - Pset_SlabCommon - IsExternal: yes
Material: Aislamiento térmico, Metal - Chapado (1)
Pset_EnvironmentalImpactIndicators - Reference: Plana tipo deck - 16 cm; sets with these values: 2
Pset_SlabCommon - Reference: Plana tipo deck - 16 cm
Name (Cubierta básica:Plana tipo deck - 16 cm:...) | PitchAngle (deg)
508018 | 28.3861
508018 | 36.6621
508018 | 29.0531
509383 | 28.28
509383 | 35.2114
509383 | 28.899

# IfcSlab: Cubierta básica:Plana tradicional transitable - 30 cm 2 (13)
Type - PredefinedType: ROOF
Type - Pset_SlabCommon - IsExternal: yes; ThermalTransmittance: 8.71667 kg/K/s3
Material: Cerámica blanca, Hormigón y arena, Aislamiento térmico, Hormigón
Pset_EnvironmentalImpactIndicators - Reference: Plana tradicional transitable - 30 cm 2; sets with these values: 2
Pset_SlabCommon - Reference: Plana tradicional transitable - 30 cm 2
Name (Cubierta básica:Plana tradicional transitable - 30 cm 2:...) | In | PitchAngle (deg)
339801 | Nivel 0 | 0
340613 | Nivel 0 | 0
340883 | Nivel 0 | 0
341121 | Nivel 0 | 0
343434 | Nivel 1 | 0
343541 | Nivel 0 | 0
344028 | Nivel 1 | 29.0042
345366 | Nivel 2 | 44.0096
348709 | Nivel 1 | 0
348753 | Nivel 0 | 0
349230 | Nivel 2 | 44.0096
349455 | Nivel 2 | 20.9824
591938 | Nivel 2 | 0

# IfcSlab: Descansillo monolítico:Grosor 200 mm (2)
In: Nivel 0
Type - PredefinedType: LANDING
Type - Pset_SlabCommon - IsExternal: no
Material: Cerámica blanca, Hormigón
Pset_EnvironmentalImpactIndicators - Reference: Grosor 200 mm; sets with these values: 2
Pset_SlabCommon - PitchAngle: 0 deg; Reference: Grosor 200 mm
Name (Escalera prefabricada:Escalera:...)
227558 Landing 1
336865 Landing 1

# IfcSlab: Suelo:Por defecto - 20 cm 2 (2)
In: Nivel 0
Pset_EnvironmentalImpactIndicators - Reference: Por defecto - 20 cm 2; sets with these values: 2
Pset_SlabCommon - IsExternal: no; LoadBearing: no; Reference: Por defecto - 20 cm 2
Name (Suelo:Por defecto - 20 cm 2:...) | PitchAngle (deg)
319010 | 1.1638
585609 | 2.66113

# IfcSlab: Suelo:Por defecto - 20 cm 2 (23)
Type - PredefinedType: FLOOR; Material: Suelos por defecto
Type - Pset_SlabCommon - IsExternal: no
Pset_EnvironmentalImpactIndicators - Reference: Por defecto - 20 cm 2; sets with these values: 2
Pset_SlabCommon - LoadBearing: no; Reference: Por defecto - 20 cm 2
Name (Suelo:Por defecto - 20 cm 2:...) | In | PitchAngle (deg)
256211 | Nivel 0 | 0
256383 | Nivel 0 | 0
295277 | Nivel 0 | 0
300869 | Nivel 0 | 0
302960 | Nivel 0 | 0
304307 | Nivel 0 | 0
305379 | Nivel 0 | 0
307170 | Nivel 0 | 0
309490 | Nivel 0 | 0.216726
315078 | Nivel 0 | 0.845195
315217 | Nivel 0 | 0
316882 | Nivel 0 | 5.93999
412267 | Nivel 1 | 0
425976 | Nivel 1 | 0
430200 | Nivel 0 | 1.24793
430366 | Nivel 0 | 0
486501 | Nivel 1 | 0
514404 | Nivel 0 | 4.74631
514504 | Nivel 0 | 1.26325
517426 | Nivel 0 | 0
577641 | Nivel 0 | 0
584378 | Nivel 0 | 0
631116 | Nivel 0 | 0

# IfcSlab: Suelo:Por defecto - 20 cm 2 (17)
In: Nivel 0
Type - PredefinedType: FLOOR
Type - Pset_SlabCommon - IsExternal: no
Material: Suelos por defecto
Pset_EnvironmentalImpactIndicators - Reference: Por defecto - 20 cm 2; sets with these values: 2
Pset_SlabCommon - LoadBearing: no; Reference: Por defecto - 20 cm 2
Name (Suelo:Por defecto - 20 cm 2:...) | PitchAngle (deg)
3 x 319010 | 1.1638
319010 | 0.141313
319010 | 0.44511
319010 | 0.602652
319010 | 0.694173
319010 | 0.90758
319010 | 5.81921
319010 | 0.377254
319010 | 0.211813
319010 | 0.821793
319010 | 0.242092
319010 | 0.946874
585609 | 2.83809
585609 | 2.66113
585609 | 1.45194

# IfcSlab: Suelo:Por defecto - 35 cm (4)
Type - PredefinedType: FLOOR; Material: Suelos por defecto
Type - Pset_SlabCommon - IsExternal: no
Pset_EnvironmentalImpactIndicators - Reference: Por defecto - 35 cm; sets with these values: 2
Pset_SlabCommon - Reference: Por defecto - 35 cm; PitchAngle: 0 deg; LoadBearing: no
Name (Suelo:Por defecto - 35 cm:...) | In
172255 | Nivel -1
176661 | Nivel -1
177103 | Nivel -1
247126 | Nivel 1

# IfcSlab: Suelo:Por defecto - 60 cm 2, Suelo:Por defecto - 60 cm 2:173709
In: Nivel 0
Type - PredefinedType: FLOOR; Material: Suelos por defecto
Type - Pset_SlabCommon - IsExternal: no
Pset_EnvironmentalImpactIndicators - Reference: Por defecto - 60 cm 2; sets with these values: 2
Pset_SlabCommon - PitchAngle: 0 deg; LoadBearing: no; Reference: Por defecto - 60 cm 2

# IfcStair: Escalera moldeada in situ:Losa de hormigón - C=17cm H=30cm, Escalera moldeada in situ:Escalera:411257
In: Nivel 1
Type - PredefinedType: STRAIGHT_RUN_STAIR
Type - Pset_StairCommon - IsExternal: no; NosingLength: 0 m; NumberOfRiser: 0; NumberOfTreads: 0
Type - Pset_StairFlightCommon - NosingLength: 0 m; NumberOfRiser: 0; NumberOfTreads: 0
Pset_EnvironmentalImpactIndicators - Reference: Losa de hormigón - C=17cm H=30cm
Pset_StairCommon - Reference: Losa de hormigón - C=17cm H=30cm; NumberOfRiser: 3; NumberOfTreads: 3; RiserHeight: 0.173333 m; TreadLength: 0.27 m; NosingLength: 0.03 m; WalkingLineOffset: 1.64042 m; TreadLengthAtOffset: 0.27 m; TreadLengthAtInnerSide: 0.27 m
Pset_StairFlightCommon - Reference: Losa de hormigón - C=17cm H=30cm; NumberOfRiser: 3; NumberOfTreads: 3; RiserHeight: 0.173333 m; TreadLength: 0.27 m; NosingLength: 0.03 m; WalkingLineOffset: 1.64042 m; TreadLengthAtOffset: 0.27 m; TreadLengthAtInnerSide: 0.27 m

# IfcStair: Escalera prefabricada:Escalera prefabricada (2)
In: Nivel 0
Type - PredefinedType: HALF_TURN_STAIR
Type - Pset_StairCommon - IsExternal: no; NosingLength: 0 m; NumberOfRiser: 0; NumberOfTreads: 0
Type - Pset_StairFlightCommon - NosingLength: 0 m; NumberOfRiser: 0; NumberOfTreads: 0
Pset_EnvironmentalImpactIndicators - Reference: Escalera prefabricada
Pset_StairCommon - Reference: Escalera prefabricada; NosingLength: 0.03 m; WalkingLineOffset: 3.5269 m
Pset_StairFlightCommon - Reference: Escalera prefabricada; NosingLength: 0.03 m; WalkingLineOffset: 3.5269 m
Name (Escalera prefabricada:Escalera:...) | Pset_StairCommon, NumberOfRiser = Pset_StairCommon, NumberOfTreads = Pset_StairFlightCommon, NumberOfRiser = Pset_StairFlightCommon, NumberOfTreads | Pset_StairCommon, RiserHeight (m) = Pset_StairFlightCommon, RiserHeight (m) | Pset_StairCommon, TreadLength (m) = Pset_StairCommon, TreadLengthAtOffset (m) = Pset_StairCommon, TreadLengthAtInnerSide (m) = Pset_StairFlightCommon, TreadLength (m) = Pset_StairFlightCommon, TreadLengthAtOffset (m) = Pset_StairFlightCommon, TreadLengthAtInnerSide (m)
227558 | 20 | 0.18 | 0.3
336865 | 21 | 0.171429 | 0.27

# IfcStair: Escalera prefabricada:Escalera prefabricada (17)
Type - PredefinedType: STRAIGHT_RUN_STAIR
Type - Pset_StairCommon - IsExternal: no; NosingLength: 0 m; NumberOfRiser: 0; NumberOfTreads: 0
Type - Pset_StairFlightCommon - NosingLength: 0 m; NumberOfRiser: 0; NumberOfTreads: 0
Pset_EnvironmentalImpactIndicators - Reference: Escalera prefabricada
Pset_StairCommon - Reference: Escalera prefabricada; NosingLength: 0.03 m
Pset_StairFlightCommon - Reference: Escalera prefabricada; NosingLength: 0.03 m
Name (Escalera prefabricada:Escalera:...) | In | Pset_StairCommon, NumberOfRiser = Pset_StairFlightCommon, NumberOfRiser | Pset_StairCommon, NumberOfTreads = Pset_StairFlightCommon, NumberOfTreads | Pset_StairCommon, RiserHeight (m) = Pset_StairFlightCommon, RiserHeight (m) | Pset_StairCommon, TreadLength (m) = Pset_StairCommon, TreadLengthAtOffset (m) = Pset_StairCommon, TreadLengthAtInnerSide (m) = Pset_StairFlightCommon, TreadLength (m) = Pset_StairFlightCommon, TreadLengthAtOffset (m) = Pset_StairFlightCommon, TreadLengthAtInnerSide (m) | Pset_StairCommon, WalkingLineOffset (m) = Pset_StairFlightCommon, WalkingLineOffset (m)
175604 | Nivel -1 | 4 | 3 | 0.14 | 0.3 | 1.37795
175658 | Nivel -1 | 4 | 3 | 0.14 | 0.3 | 1.37795
175675 | Nivel -1 | 4 | 3 | 0.14 | 0.3 | 1.37795
175694 | Nivel -1 | 4 | 3 | 0.14 | 0.3 | 1.37795
175709 | Nivel -1 | 4 | 3 | 0.14 | 0.3 | 1.37795
175728 | Nivel -1 | 4 | 3 | 0.14 | 0.3 | 1.37795
175826 | Nivel -1 | 3 | 3 | 0.186667 | 0.3 | 2.37861
176099 | Nivel -1 | 3 | 3 | 0.186667 | 0.3 | 2.37861
176115 | Nivel -1 | 3 | 3 | 0.14 | 0.3 | 2.37861
176131 | Nivel -1 | 3 | 3 | 0.14 | 0.3 | 2.37861
176149 | Nivel -1 | 3 | 3 | 0.14 | 0.3 | 2.37861
176165 | Nivel -1 | 3 | 3 | 0.14 | 0.3 | 2.37861
176263 | Nivel -1 | 2 | 2 | 0.21 | 0.27 | 1.37795
177085 | Nivel -1 | 2 | 2 | 0.21 | 0.27 | 1.37795
530396 | Nivel 0 | 2 | 2 | 0.155 | 0.27 | 1.80446
536798 | Nivel 1 | 3 | 3 | 0.113333 | 0.27 | 1.64042
583606 | Nivel 0 | 3 | 2 | 0.226667 | 0.27

# IfcStair: Escalera prefabricada:Escalera prefabricada, Escalera prefabricada:Escalera:175361
In: Nivel -1
Type - PredefinedType: STRAIGHT_RUN_STAIR
Type - Pset_StairCommon - IsExternal: no; NumberOfRiser: 0; NumberOfTreads: 0; NosingLength: 0 m
Type - Pset_StairFlightCommon - NosingLength: 0 m; NumberOfRiser: 0; NumberOfTreads: 0
Pset_EnvironmentalImpactIndicators - Reference: Escalera prefabricada
Pset_StairCommon - Reference: Escalera prefabricada; NumberOfRiser: 4; NumberOfTreads: 3; RiserHeight: 0.14 m; TreadLength: 0.3 m; NosingLength: 0.03 m; WalkingLineOffset: 1.37795 m; TreadLengthAtOffset: 0.3 m; TreadLengthAtInnerSide: 0.3 m
Pset_StairFlightCommon - Reference: Escalera prefabricada; NumberOfRiser: 4; NumberOfTreads: 3; RiserHeight: 0.14 m; TreadLength: 0.3 m; NosingLength: 0.03 m; WalkingLineOffset: 1.37795 m; TreadLengthAtOffset: 0.3 m; TreadLengthAtInnerSide: 0.3 m

# IfcStair: Escalera prefabricada:Escalera prefabricada (2)
In: Nivel 0
Type - Pset_StairCommon - IsExternal: no; NosingLength: 0 m; NumberOfRiser: 0; NumberOfTreads: 0
Type - Pset_StairFlightCommon - NosingLength: 0 m; NumberOfRiser: 0; NumberOfTreads: 0
Pset_EnvironmentalImpactIndicators - Reference: Escalera prefabricada
Pset_StairCommon - Reference: Escalera prefabricada; TreadLength: 0.27 m; NosingLength: 0.03 m; TreadLengthAtOffset: 0.27 m; TreadLengthAtInnerSide: 0.27 m
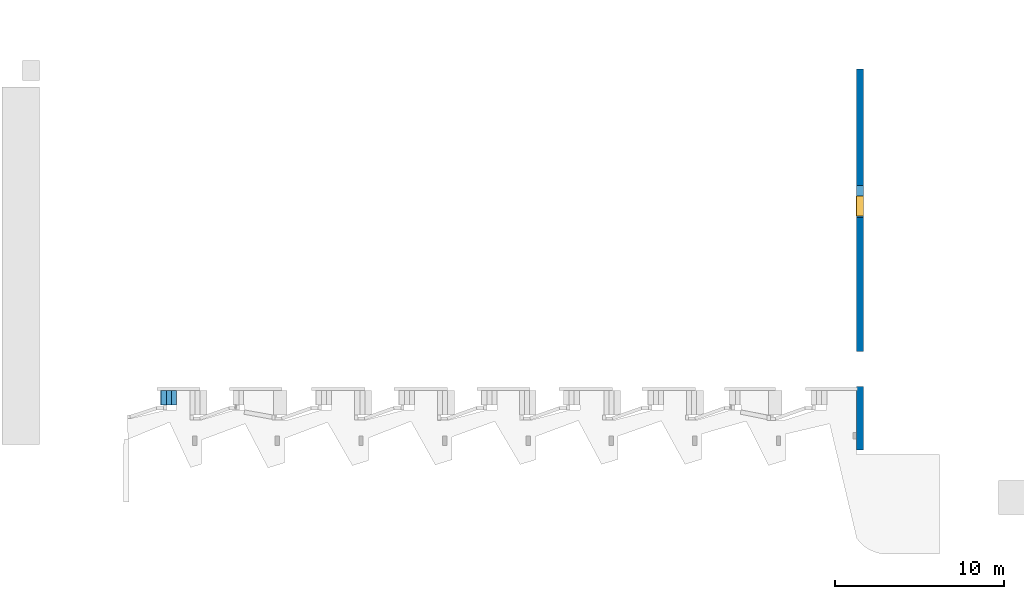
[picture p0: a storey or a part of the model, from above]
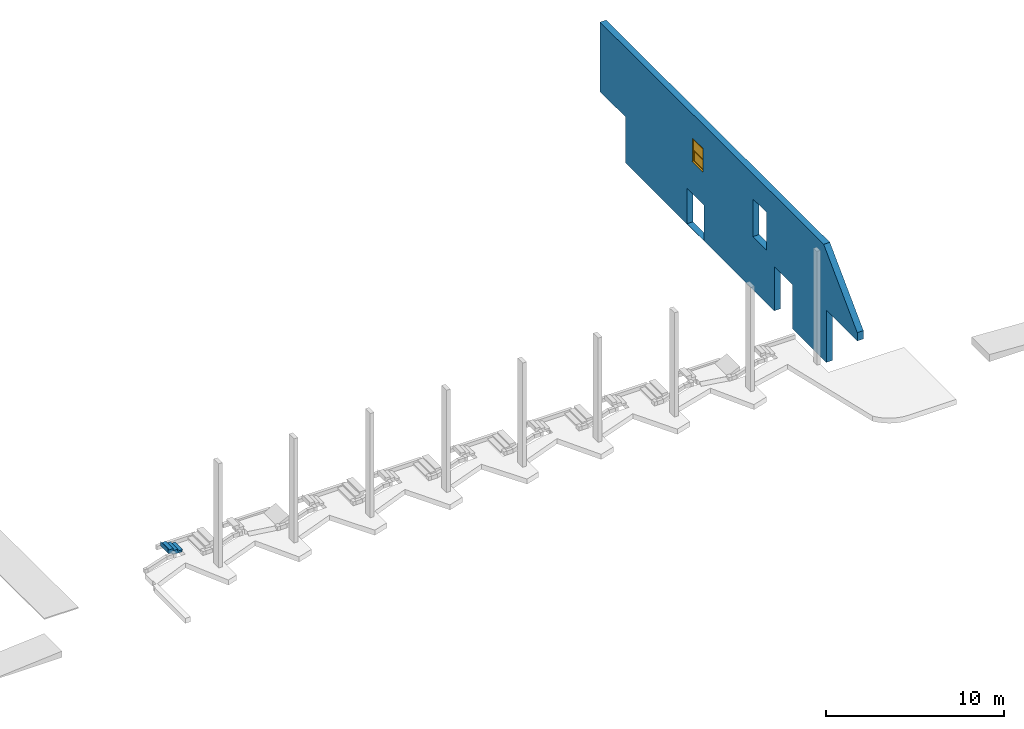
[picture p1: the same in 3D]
Properties of the parts of a building model (IFC4), part 3 of 3

# IfcStair: Escalera prefabricada:Escalera prefabricada (2)
Pset_StairFlightCommon - Reference: Escalera prefabricada; TreadLength: 0.27 m; NosingLength: 0.03 m; TreadLengthAtOffset: 0.27 m; TreadLengthAtInnerSide: 0.27 m
Name (Escalera prefabricada:Escalera:...) | Pset_StairCommon, NumberOfRiser = Pset_StairFlightCommon, NumberOfRiser | Pset_StairCommon, NumberOfTreads = Pset_StairFlightCommon, NumberOfTreads | Pset_StairCommon, RiserHeight (m) = Pset_StairFlightCommon, RiserHeight (m)
543301 | 18 | 17 | 0.1625
546754 | 9 | 8 | 0.155556

# IfcStairFlight: Tramo monolítico:Huella 40 mm Mamperlán 30 mm Contrahuella 15 mm (3)
In: Nivel 0
Material: Cerámica blanca, Hormigón
Pset_EnvironmentalImpactIndicators - Reference: Huella 40 mm Mamperlán 30 mm Contrahuella 15 mm
Pset_StairFlightCommon - Reference: Huella 40 mm Mamperlán 30 mm Contrahuella 15 mm; TreadLength: 0.27 m; NosingLength: 0.03 m; TreadLengthAtOffset: 0.27 m; TreadLengthAtInnerSide: 0.27 m
Name (Escalera prefabricada:Escalera:...) | NumberOfRiser | NumberOfTreads | RiserHeight (m)
543301 Run 1 | 18 | 17 | 0.1625
546754 Run 1 | 9 | 8 | 0.155556
583606 Run 1 | 3 | 2 | 0.226667

# IfcStairFlight: Tramo monolítico:Huella 40 mm Mamperlán 30 mm Contrahuella 15 mm (22)
Type - PredefinedType: STRAIGHT
Material: Cerámica blanca, Hormigón
Pset_EnvironmentalImpactIndicators - Reference: Huella 40 mm Mamperlán 30 mm Contrahuella 15 mm
Pset_StairFlightCommon - Reference: Huella 40 mm Mamperlán 30 mm Contrahuella 15 mm; NosingLength: 0.03 m
Name | In | NumberOfRiser | NumberOfTreads | RiserHeight (m) | TreadLength (m) = TreadLengthAtOffset (m) = TreadLengthAtInnerSide (m) | WalkingLineOffset (m)
Escalera prefabricada:Escalera:175361 Run 1 | Nivel -1 | 4 | 3 | 0.14 | 0.3 | 1.37795
Escalera prefabricada:Escalera:175604 Run 1 | Nivel -1 | 4 | 3 | 0.14 | 0.3 | 1.37795
Escalera prefabricada:Escalera:175658 Run 1 | Nivel -1 | 4 | 3 | 0.14 | 0.3 | 1.37795
Escalera prefabricada:Escalera:175675 Run 1 | Nivel -1 | 4 | 3 | 0.14 | 0.3 | 1.37795
Escalera prefabricada:Escalera:175694 Run 1 | Nivel -1 | 4 | 3 | 0.14 | 0.3 | 1.37795
Escalera prefabricada:Escalera:175709 Run 1 | Nivel -1 | 4 | 3 | 0.14 | 0.3 | 1.37795
Escalera prefabricada:Escalera:175728 Run 1 | Nivel -1 | 4 | 3 | 0.14 | 0.3 | 1.37795
Escalera prefabricada:Escalera:175826 Run 1 | Nivel -1 | 3 | 3 | 0.186667 | 0.3 | 2.37861
Escalera prefabricada:Escalera:176099 Run 1 | Nivel -1 | 3 | 3 | 0.186667 | 0.3 | 2.37861
Escalera prefabricada:Escalera:176115 Run 1 | Nivel -1 | 3 | 3 | 0.14 | 0.3 | 2.37861
Escalera prefabricada:Escalera:176131 Run 1 | Nivel -1 | 3 | 3 | 0.14 | 0.3 | 2.37861
Escalera prefabricada:Escalera:176149 Run 1 | Nivel -1 | 3 | 3 | 0.14 | 0.3 | 2.37861
Escalera prefabricada:Escalera:176165 Run 1 | Nivel -1 | 3 | 3 | 0.14 | 0.3 | 2.37861
Escalera prefabricada:Escalera:176263 Run 1 | Nivel -1 | 2 | 2 | 0.21 | 0.27 | 1.37795
Escalera prefabricada:Escalera:177085 Run 1 | Nivel -1 | 2 | 2 | 0.21 | 0.27 | 1.37795
Escalera prefabricada:Escalera:227558 Run 1 | Nivel 0 | 14 | 14 | 0.18 | 0.3 | 3.5269
Escalera prefabricada:Escalera:227558 Run 2 | Nivel 0 | 6 | 6 | 0.18 | 0.3 | 3.35466
Escalera prefabricada:Escalera:336865 Run 1 | Nivel 0 | 15 | 15 | 0.171429 | 0.27 | 3.5269
Escalera prefabricada:Escalera:336865 Run 2 | Nivel 0 | 6 | 6 | 0.171429 | 0.27 | 3.5269
Escalera moldeada in situ:Escalera:411257 Run 1 | Nivel 1 | 3 | 3 | 0.173333 | 0.27 | 1.64042
Escalera prefabricada:Escalera:530396 Run 1 | Nivel 0 | 2 | 2 | 0.155 | 0.27 | 1.80446
Escalera prefabricada:Escalera:536798 Run 1 | Nivel 1 | 3 | 3 | 0.113333 | 0.27 | 1.64042

# IfcWall: Muro básico:Por defecto - 10 cm (48)
Type - PredefinedType: STANDARD
Type - Pset_WallCommon - IsExternal: yes
Material: Muro por defecto
Pset_EnvironmentalImpactIndicators - Reference: Por defecto - 10 cm; sets with these values: 2
Pset_WallCommon - LoadBearing: no; Reference: Por defecto - 10 cm
Name (Muro básico:Por defecto - 10 cm:...) | In | ExtendToStructure
186371 | Nivel 0 | no
224065 | Nivel 0 | no
231013 | Nivel 0 | yes
231121 | Nivel 0 | yes
231203 | Nivel 0 | yes
231251 | Nivel 0 | yes
231345 | Nivel 0 | yes
231388 | Nivel 0 | yes
231470 | Nivel 0 | yes
231527 | Nivel 0 | yes
283750 | Nivel 0 | yes
284053 | Nivel 0 | yes
284103 | Nivel 0 | yes
285087 | Nivel 0 | yes
285177 | Nivel 0 | yes
285252 | Nivel 0 | yes
384465 | Nivel 0 | no
406178 | Nivel 1 | no
406418 | Nivel 1 | no
409825 | Nivel 1 | no
410711 | Nivel 1 | no
411055 | Nivel 1 | no
534731 | Nivel 1 | no
535569 | Nivel 1 | no
535685 | Nivel 1 | no
536036 | Nivel 1 | no
537640 | Nivel 1 | no
552848 | Nivel 1 | no
552940 | Nivel 1 | no
553035 | Nivel 1 | no
553136 | Nivel 1 | no
553375 | Nivel 1 | no
553439 | Nivel 1 | no
553485 | Nivel 1 | no
553551 | Nivel 1 | no
553775 | Nivel 1 | no
553807 | Nivel 1 | yes
553842 | Nivel 1 | yes
559163 | Nivel 1 | no
559239 | Nivel 1 | no
559397 | Nivel 1 | no
593011 | Nivel 0 | no
593266 | Nivel 0 | no
597237 | Nivel 0 | no
625690 | Nivel 0 | yes
625860 | Nivel 0 | yes
625969 | Nivel 0 | yes
630059 | Nivel 0 | no

# IfcWall: Muro básico:Por defecto - 12 cm 2 (12)
In: Nivel 0
Type - PredefinedType: STANDARD
Type - Pset_WallCommon - IsExternal: yes
Material: Muro por defecto
Pset_EnvironmentalImpactIndicators - Reference: Por defecto - 12 cm 2; sets with these values: 2
Pset_WallCommon - LoadBearing: no; Reference: Por defecto - 12 cm 2
Name (Muro básico:Por defecto - 12 cm 2:...) | ExtendToStructure
196055 | no
196575 | no
196729 | no
197664 | no
225624 | yes
226755 | no
229712 | no
229818 | yes
229874 | no
230248 | yes
230669 | yes
230757 | yes

# IfcWall: Muro básico:Por defecto - 15 cm 2 (37)
Type - PredefinedType: STANDARD
Type - Pset_WallCommon - IsExternal: yes
Material: Muro por defecto
Pset_EnvironmentalImpactIndicators - Reference: Por defecto - 15 cm 2; sets with these values: 2
Pset_WallCommon - LoadBearing: no; Reference: Por defecto - 15 cm 2
Name (Muro básico:Por defecto - 15 cm 2:...) | In | ExtendToStructure
195734 | Nivel 0 | no
195770 | Nivel 0 | no
224963 | Nivel 0 | yes
224998 | Nivel 0 | yes
281796 | Nivel 0 | no
282135 | Nivel 0 | yes
283243 | Nivel 0 | yes
300412 | Nivel 0 | no
300639 | Nivel 0 | no
301709 | Nivel 0 | no
410502 | Nivel 1 | no
416838 | Nivel 1 | yes
416946 | Nivel 1 | no
416983 | Nivel 1 | yes
417195 | Nivel 1 | no
417408 | Nivel 1 | yes
417665 | Nivel 1 | no
417798 | Nivel 1 | yes
417866 | Nivel 1 | no
417961 | Nivel 1 | yes
418533 | Nivel 1 | yes
419558 | Nivel 1 | yes
420379 | Nivel 1 | yes
420598 | Nivel 1 | yes
423640 | Nivel 1 | yes
423731 | Nivel 1 | yes
424180 | Nivel 1 | yes
485553 | Nivel 1 | yes
487588 | Nivel 1 | yes
542671 | Nivel 1 | yes
590387 | Nivel 1 | no
590990 | Nivel 1 | no
590994 | Nivel 1 | no
591357 | Nivel 1 | no
591361 | Nivel 1 | no
591608 | Nivel 1 | yes
591698 | Nivel 1 | no

# IfcWall: Muro básico:Por defecto - 18 cm 2 (77)
In: Nivel 0
Type - PredefinedType: STANDARD
Type - Pset_WallCommon - IsExternal: yes
Material: Muro por defecto
Pset_EnvironmentalImpactIndicators - Reference: Por defecto - 18 cm 2; sets with these values: 2
Pset_WallCommon - LoadBearing: no; Reference: Por defecto - 18 cm 2
Name (Muro básico:Por defecto - 18 cm 2:...) | ExtendToStructure
186199 | no
186491 | no
186764 | no
187437 | no
253451 | no
267867 | no
267995 | no
268105 | no
275619 | yes
275666 | no
284924 | yes
296650 | yes
296851 | yes
298925 | yes
298926 | yes
307977 | no
307990 | no
327384 | no
351703 | no
351704 | no
351706 | no
351707 | no
442484 | no
444830 | no
444894 | no
445005 | no
445026 | no
445047 | no
445254 | no
445270 | no
445286 | no
445382 | no
445398 | no
445414 | no
445510 | no
445526 | no
445542 | no
445642 | no
445658 | no
445674 | no
445979 | no
445995 | no
446011 | no
446547 | no
446563 | no
447318 | no
447334 | no
447707 | no
448735 | no
450019 | no
450256 | no
450401 | no
450430 | no
450451 | no
452463 | no
452479 | no
452495 | no
452665 | no
452681 | no
452697 | no
453910 | no
453926 | no
453942 | no
454420 | no
454436 | no
454452 | no
455606 | no
455622 | no
455638 | no
455800 | no
455816 | no
455832 | no
457841 | no
457857 | no
457873 | no
607063 | yes
629764 | no

# IfcWall: Muro básico:Por defecto - 20 cm (87)
Type - PredefinedType: STANDARD
Type - Pset_WallCommon - IsExternal: yes
Material: Muro por defecto
Pset_EnvironmentalImpactIndicators - Reference: Por defecto - 20 cm; sets with these values: 2
Pset_WallCommon - LoadBearing: no; Reference: Por defecto - 20 cm
Name (Muro básico:Por defecto - 20 cm:...) | In | ExtendToStructure
177354 | Nivel -1 | no
177402 | Nivel -1 | no
177456 | Nivel -1 | no
177522 | Nivel -1 | no
177708 | Nivel -1 | no
177898 | Nivel -1 | no
178002 | Nivel -1 | no
178043 | Nivel -1 | no
178090 | Nivel -1 | no
178131 | Nivel -1 | no
178205 | Nivel -1 | no
178245 | Nivel -1 | no
178378 | Nivel -1 | no
178424 | Nivel -1 | no
178486 | Nivel -1 | no
178526 | Nivel -1 | no
178572 | Nivel -1 | no
178667 | Nivel -1 | no
178748 | Nivel -1 | no
178816 | Nivel -1 | no
178892 | Nivel -1 | no
178939 | Nivel -1 | no
178979 | Nivel -1 | no
179099 | Nivel -1 | no
179192 | Nivel -1 | no
179295 | Nivel -1 | no
179349 | Nivel -1 | no
179428 | Nivel -1 | no
179477 | Nivel -1 | no
179515 | Nivel -1 | no
179674 | Nivel -1 | no
179766 | Nivel -1 | no
179812 | Nivel -1 | no
179899 | Nivel -1 | no
179957 | Nivel -1 | no
179993 | Nivel -1 | no
180153 | Nivel -1 | no
180264 | Nivel -1 | no
180343 | Nivel -1 | no
180410 | Nivel -1 | no
180459 | Nivel -1 | no
180499 | Nivel -1 | no
180602 | Nivel -1 | no
180674 | Nivel -1 | no
180762 | Nivel -1 | no
180826 | Nivel -1 | no
180857 | Nivel -1 | no
181023 | Nivel -1 | no
181073 | Nivel -1 | no
181182 | Nivel -1 | no
181229 | Nivel -1 | no
181263 | Nivel -1 | no
181323 | Nivel -1 | no
181404 | Nivel -1 | no
181446 | Nivel -1 | no
181581 | Nivel -1 | no
228305 | Nivel 0 | yes
363562 | Nivel 1 | no
406535 | Nivel 1 | no
406832 | Nivel 1 | no
435255 | Nivel 1 | no
435521 | Nivel 1 | no
435606 | Nivel 1 | no
435708 | Nivel 1 | no
435738 | Nivel 1 | no
435758 | Nivel 1 | no
435785 | Nivel 1 | no
435827 | Nivel 1 | no
577426 | Nivel 0 | no
577458 | Nivel 0 | no
580043 | Nivel 0 | no
580124 | Nivel 0 | no
582109 | Nivel 0 | no
582827 | Nivel 0 | no
583288 | Nivel 0 | no
585091 | Nivel 0 | no
585167 | Nivel 0 | no
585357 | Nivel 0 | no
599172 | Nivel 0 | no
599865 | Nivel 0 | no
603755 | Nivel 0 | no
603908 | Nivel 0 | no
604072 | Nivel 0 | no
604073 | Nivel 0 | no
604074 | Nivel 0 | no
621177 | Nivel 0 | no
621579 | Nivel 0 | no

# IfcWall: Muro básico:Por defecto - 22 cm 2 (7)
Type - PredefinedType: STANDARD
Type - Pset_WallCommon - IsExternal: yes
Material: Muro por defecto
Pset_EnvironmentalImpactIndicators - Reference: Por defecto - 22 cm 2; sets with these values: 2
Pset_WallCommon - LoadBearing: no; Reference: Por defecto - 22 cm 2
Name (Muro básico:Por defecto - 22 cm 2:...) | In | ExtendToStructure
284277 | Nivel 0 | yes
296194 | Nivel 0 | no
298924 | Nivel 0 | no
342739 | Nivel 1 | yes
350361 | Nivel 1 | yes
351702 | Nivel 0 | no
351705 | Nivel 0 | no

# IfcWall: Muro básico:Por defecto - 25 cm 2 (14)
In: Nivel 0
Type - PredefinedType: STANDARD
Type - Pset_WallCommon - IsExternal: yes
Material: Muro por defecto
Pset_EnvironmentalImpactIndicators - Reference: Por defecto - 25 cm 2; sets with these values: 2
Pset_WallCommon - LoadBearing: no; Reference: Por defecto - 25 cm 2
Name (Muro básico:Por defecto - 25 cm 2:...) | ExtendToStructure
184832 | no
185040 | no
185120 | no
185200 | no
218619 | no
225143 | no
230052 | no
253016 | no
272692 | no
291882 | no
308197 | no
310854 | yes
343114 | yes
351531 | no

# IfcWall: Muro básico:Por defecto - 30 cm (26)
Type - PredefinedType: STANDARD
Type - Pset_WallCommon - IsExternal: yes
Material: Muro por defecto
Pset_EnvironmentalImpactIndicators - Reference: Por defecto - 30 cm; sets with these values: 2
Pset_WallCommon - LoadBearing: no; Reference: Por defecto - 30 cm
Name (Muro básico:Por defecto - 30 cm:...) | In | ExtendToStructure
184906 | Nivel 0 | no
219780 | Nivel 0 | no
225329 | Nivel 0 | no
226228 | Nivel 0 | no
271633 | Nivel 0 | yes
279584 | Nivel 0 | yes
282441 | Nivel 0 | yes
282785 | Nivel 0 | no
284559 | Nivel 0 | no
284647 | Nivel 0 | no
285363 | Nivel 0 | no
287450 | Nivel 0 | no
289831 | Nivel 0 | no
294648 | Nivel 0 | no
294908 | Nivel 0 | no
297083 | Nivel 0 | no
308976 | Nivel 0 | no
312057 | Nivel 0 | yes
342960 | Nivel 0 | no
360312 | Nivel 1 | no
360403 | Nivel 1 | no
428511 | Nivel 0 | no
428788 | Nivel 0 | no
429060 | Nivel 0 | no
601536 | Nivel 0 | yes
601643 | Nivel 0 | no

# IfcWall: Muro básico:Por defecto - 36 cm 2 (3)
In: Nivel 1
Type - PredefinedType: STANDARD
Type - Pset_WallCommon - IsExternal: yes
Material: Muro por defecto
Pset_EnvironmentalImpactIndicators - Reference: Por defecto - 36 cm 2; sets with these values: 2
Pset_WallCommon - LoadBearing: no; ExtendToStructure: no; Reference: Por defecto - 36 cm 2
Name (Muro básico:Por defecto - 36 cm 2:...)
418173
418411
422187

# IfcWall: Muro básico:Por defecto - 40 cm 2 (11)
Type - PredefinedType: STANDARD
Type - Pset_WallCommon - IsExternal: yes
Material: Muro por defecto
Pset_EnvironmentalImpactIndicators - Reference: Por defecto - 40 cm 2; sets with these values: 2
Pset_WallCommon - LoadBearing: no; Reference: Por defecto - 40 cm 2
Name (Muro básico:Por defecto - 40 cm 2:...) | In | ExtendToStructure
183592 | Nivel 0 | no
184475 | Nivel -1 | no
225460 | Nivel 0 | no
226059 | Nivel 0 | yes
272293 | Nivel 0 | no
285576 | Nivel 0 | no
285680 | Nivel 0 | no
426475 | Nivel 1 | no
606972 | Nivel 0 | no
607381 | Nivel 0 | no
629450 | Nivel 0 | no

# IfcWall: Muro básico:Por defecto - 5 cm 2 (10)
Type - PredefinedType: STANDARD
Type - Pset_WallCommon - IsExternal: yes
Material: Muro por defecto
Pset_EnvironmentalImpactIndicators - Reference: Por defecto - 5 cm 2; sets with these values: 2
Pset_WallCommon - LoadBearing: no; Reference: Por defecto - 5 cm 2
Name (Muro básico:Por defecto - 5 cm 2:...) | In | ExtendToStructure
222298 | Nivel 0 | no
223614 | Nivel 0 | no
223872 | Nivel 0 | no
423673 | Nivel 1 | no
425152 | Nivel 1 | yes
425414 | Nivel 1 | no
425557 | Nivel 1 | no
486182 | Nivel 1 | yes
630478 | Nivel 0 | no
630571 | Nivel 0 | no

# IfcWall: Muro básico:Por defecto - 73 cm 3, Muro básico:Por defecto - 73 cm 3:620158
In: Nivel 0
Type - PredefinedType: STANDARD
Type - Pset_WallCommon - IsExternal: yes
Material: Muro por defecto
Pset_EnvironmentalImpactIndicators - Reference: Por defecto - 73 cm 3; sets with these values: 2
Pset_WallCommon - LoadBearing: no; ExtendToStructure: no; Reference: Por defecto - 73 cm 3

# IfcWindow: Deflector de ventilación simple:60 x 1.15mm 2 (4)
In: Nivel 0
Type - PredefinedType: WINDOW; Material: Madera - Abedul
Type - Pset_WindowCommon - IsExternal: no; ThermalTransmittance: 3.6886 kg/K/s3
OverallHeight: 0.6096 m; OverallWidth: 1.15 m
Pset_EnvironmentalImpactIndicators - Reference: 60 x 1.15mm 2
Pset_WindowCommon - Reference: 60 x 1.15mm 2
Name (Deflector de ventilación simple:60 x 1.15mm 2:...)
573069 | Pset_WindowCommon - IsExternal: yes
573105
576742
576743

# IfcWindow: Ventana basculante:35 x 60mm 3 (3)
In: Nivel 1
Type - PredefinedType: WINDOW; Material: <Unnamed>, Madera - Castaño (2), Vidrio
Type - Pset_WindowCommon - IsExternal: no; ThermalTransmittance: 3.6886 kg/K/s3
OverallHeight: 0.35 m; OverallWidth: 0.6 m; Material: <Unnamed>, Madera - Castaño, Vidrio
Pset_EnvironmentalImpactIndicators - Reference: 35 x 60mm 3
Pset_WindowCommon - Reference: 35 x 60mm 3
Name (Ventana basculante:35 x 60mm 3:...)
565564 | Pset_WindowCommon - IsExternal: yes
565604
565644

# IfcWindow: Ventana basculante:35 x 70mm 2, Ventana basculante:35 x 70mm 2:558207
In: Nivel 1
Type - PredefinedType: WINDOW; Material: <Unnamed>, Madera - Castaño (2), Vidrio
Type - Pset_WindowCommon - IsExternal: no; ThermalTransmittance: 3.6886 kg/K/s3
OverallHeight: 0.35 m; OverallWidth: 0.7 m; Material: <Unnamed>, Madera - Castaño, Vidrio
Pset_EnvironmentalImpactIndicators - Reference: 35 x 70mm 2
Pset_WindowCommon - IsExternal: yes; Reference: 35 x 70mm 2

# IfcWindow: Ventana basculante:45 x 100mm 4, Ventana basculante:45 x 100mm 4:591360
In: Nivel 1
Type - PredefinedType: WINDOW; Material: <Unnamed>, Madera - Castaño (2), Vidrio
Type - Pset_WindowCommon - IsExternal: no; ThermalTransmittance: 3.6886 kg/K/s3
OverallHeight: 0.45 m; OverallWidth: 1 m; Material: <Unnamed>, Madera - Castaño, Vidrio
Pset_EnvironmentalImpactIndicators - Reference: 45 x 100mm 4
Pset_WindowCommon - IsExternal: yes; Reference: 45 x 100mm 4

# IfcWindow: Ventana corredera de 2 hojas 2:1600 x 1600mm, Ventana corredera de 2 hojas 2:1600 x 1600mm:541523
In: Nivel 1
Type - PredefinedType: WINDOW; Material: Madera - Castaño (3), Vidrio
Type - Pset_WindowCommon - IsExternal: no; ThermalTransmittance: 3.6886 kg/K/s3
OverallHeight: 1.2 m; OverallWidth: 1 m; Material: Madera - Castaño, Vidrio
Pset_EnvironmentalImpactIndicators - Reference: 1600 x 1600mm
Pset_WindowCommon - IsExternal: yes; Reference: 1600 x 1600mm

# IfcWindow: Ventana corredera de 2 hojas 2:1850 x 1300mm 2, Ventana corredera de 2 hojas 2:1850 x 1300mm 2:551987
In: Nivel 1
Type - PredefinedType: WINDOW; Material: Madera - Castaño (3), Vidrio
Type - Pset_WindowCommon - IsExternal: no; ThermalTransmittance: 3.6886 kg/K/s3
OverallHeight: 1.3 m; OverallWidth: 1.85 m; Material: Madera - Castaño, Vidrio
Pset_EnvironmentalImpactIndicators - Reference: 1850 x 1300mm 2
Pset_WindowCommon - IsExternal: yes; Reference: 1850 x 1300mm 2

# IfcWindow: Ventana de guillotina de 2 hojas:1200x 1600mm 2, Ventana de guillotina de 2 hojas:1200x 1600mm 2:488622
In: Nivel 1
Type - PredefinedType: WINDOW; Material: Vidrio, Hoja, Madera - Castaño
Type - Pset_WindowCommon - IsExternal: no; ThermalTransmittance: 3.6886 kg/K/s3
OverallHeight: 1.6 m; OverallWidth: 1.2 m
Pset_EnvironmentalImpactIndicators - Reference: 1200x 1600mm 2
Pset_WindowCommon - IsExternal: yes; Reference: 1200x 1600mm 2

# IfcWindow: Ventana de guillotina de 2 hojas:1300x 1600mm 3 (6)
In: Nivel 1
Type - PredefinedType: WINDOW; Material: Vidrio, Hoja, Madera - Castaño
Type - Pset_WindowCommon - IsExternal: no; ThermalTransmittance: 3.6886 kg/K/s3
OverallHeight: 1.6 m; OverallWidth: 1.13 m
Pset_EnvironmentalImpactIndicators - Reference: 1300x 1600mm 3
Pset_WindowCommon - Reference: 1300x 1600mm 3
Name (Ventana de guillotina de 2 hojas:1300x 1600mm 3:...)
490493 | Pset_WindowCommon - IsExternal: yes
491821
492054
492250
498402
635270

# IfcWindow: Ventana de guillotina de 2 hojas:1500x 1600mm 4 (3)
In: Nivel 1
Type - PredefinedType: WINDOW; Material: Vidrio, Hoja, Madera - Castaño
Type - Pset_WindowCommon - IsExternal: no; ThermalTransmittance: 3.6886 kg/K/s3
OverallHeight: 1.6 m; OverallWidth: 1.15 m
Pset_EnvironmentalImpactIndicators - Reference: 1500x 1600mm 4
Pset_WindowCommon - Reference: 1500x 1600mm 4
Name (Ventana de guillotina de 2 hojas:1500x 1600mm 4:...)
489988 | Pset_WindowCommon - IsExternal: yes
492147
498488

# IfcWindow: Ventana de muro cortina con proyectable simple:Ventana de muro cortina con proyectable simple (32)
In: Nivel 0
Type - PredefinedType: WINDOW; Material: Vidrio, Metal - Aluminio
Type - Pset_WindowCommon - IsExternal: no; ThermalTransmittance: 3.6886 kg/K/s3
Pset_EnvironmentalImpactIndicators - Reference: Ventana de muro cortina con proyectable simple
Pset_WindowCommon - Reference: Ventana de muro cortina con proyectable simple
Name (Ventana de muro cortina con proyectable simple:Ventana de muro cortina con proyectable simple:...) | OverallHeight (m) | OverallWidth (m)
250160 | 0.615 | 0.875
250490 | 0.615 | 1.13
250809 | 0.615 | 1.13
250430 | 0.615 | 0.834435
250667 | 0.59 | 0.875
250668 | 0.59 | 1.13
250954 | 0.59 | 1.13
250669 | 0.64 | 0.834435
269515 | 0.615 | 1.85
270716 | 0.59 | 1.85
271397 | 0.615 | 2.41953
271398 | 0.59 | 2.41953
271894 | 0.615 | 1.91047
271895 | 0.59 | 1.91047
273399 | 0.64 | 2.425
273809 | 0.615 | 2.425
276644 | 0.605 | 1.63
276892 | 0.63 | 1.63
277238 | 0.605 | 1.76025
277252 | 0.63 | 1.76025
386038 | 1.075 | 2.37
386204 | 0.6 | 2.37
388808 | 0.6 | 1.19333
388809 | 0.6 | 1.21833
388810 | 0.6 | 1.19333
388727 | 0.6 | 0.885
388728 | 0.6 | 0.885
388667 | 0.6 | 1.6
388594 | 0.6 | 0.875
388595 | 0.6 | 1.725
388596 | 0.6 | 0.875
392537 | 0.5375 | 1.43

# IfcWindow: Ventana simple fija con cubrejuntas interior:0.6 x 2.05mm 2 (2)
In: Nivel 0
Type - PredefinedType: WINDOW; Material: Madera - Castaño, Vidrio
Type - Pset_WindowCommon - IsExternal: no; ThermalTransmittance: 3.6886 kg/K/s3
OverallHeight: 0.6 m; OverallWidth: 2 m
Pset_EnvironmentalImpactIndicators - Reference: 0.6 x 2.05mm 2
Pset_WindowCommon - Reference: 0.6 x 2.05mm 2
Name (Ventana simple fija con cubrejuntas interior:0.6 x 2.05mm 2:...)
576462 | Pset_WindowCommon - IsExternal: yes
576744

# IfcWindow: Ventana simple fija con cubrejuntas interior:1.15 x 1.20mm 2, Ventana simple fija con cubrejuntas interior:1.15 x 1.20mm 2:612186
In: Nivel 1
Type - PredefinedType: WINDOW; Material: Madera - Castaño, Vidrio
Type - Pset_WindowCommon - IsExternal: no; ThermalTransmittance: 3.6886 kg/K/s3
OverallHeight: 1.25 m; OverallWidth: 1.15 m
Pset_EnvironmentalImpactIndicators - Reference: 1.15 x 1.20mm 2
Pset_WindowCommon - IsExternal: yes; Reference: 1.15 x 1.20mm 2

# IfcWindow: Ventana simple fija con cubrejuntas interior:1900x 1200mm 2 (3)
In: Nivel 1
Type - PredefinedType: WINDOW; Material: Madera - Castaño, Vidrio
Type - Pset_WindowCommon - IsExternal: no; ThermalTransmittance: 3.6886 kg/K/s3
OverallHeight: 1.2 m; OverallWidth: 1.9 m
Pset_EnvironmentalImpactIndicators - Reference: 1900x 1200mm 2
Pset_WindowCommon - Reference: 1900x 1200mm 2
Name (Ventana simple fija con cubrejuntas interior:1900x 1200mm 2:...)
592107 | Pset_WindowCommon - IsExternal: yes
596059
596153

# IfcWindow: Ventana simple:109 x 100 cm 2, Ventana simple:109 x 100 cm 2:412077
In: Nivel 1
Type - PredefinedType: WINDOW; Material: Piedra - Gris, Vidrio, Madera - Castaño
Type - Pset_WindowCommon - IsExternal: no
OverallHeight: 1 m; OverallWidth: 1 m
Pset_EnvironmentalImpactIndicators - Reference: 109 x 100 cm 2
Pset_WindowCommon - IsExternal: yes; Reference: 109 x 100 cm 2
